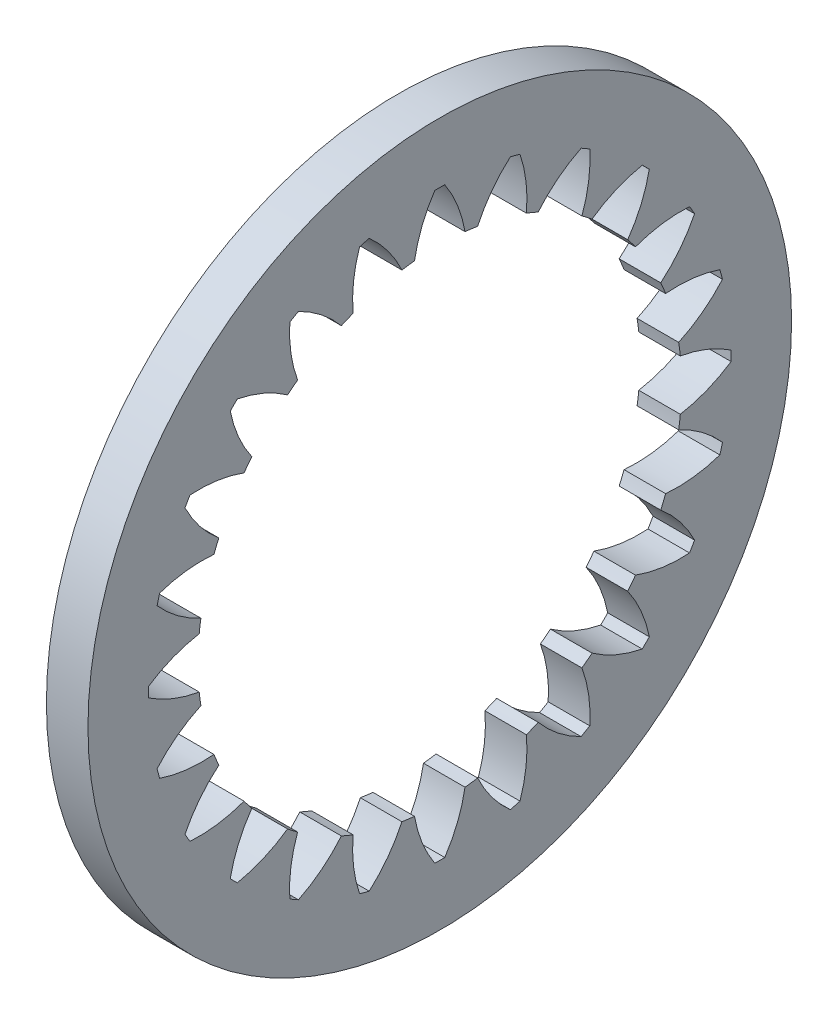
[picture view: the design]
ISO-10303-21;
HEADER;
FILE_DESCRIPTION(('STEP AP214'),'2;1');
FILE_NAME('part.step','',(''),(''),'','','');
FILE_SCHEMA(('AUTOMOTIVE_DESIGN { 1 0 10303 214 1 1 1 1 }'));
ENDSEC;
DATA;
#1=APPLICATION_CONTEXT('core data for automotive mechanical design processes');
#2=APPLICATION_PROTOCOL_DEFINITION('international standard','automotive_design',2000,#1);
#3=PRODUCT_CONTEXT('',#1,'mechanical');
#4=PRODUCT('Part','Part','',(#3));
#5=PRODUCT_RELATED_PRODUCT_CATEGORY('part','',(#4));
#6=PRODUCT_DEFINITION_FORMATION('','',#4);
#7=PRODUCT_DEFINITION_CONTEXT('part definition',#1,'design');
#8=PRODUCT_DEFINITION('design','',#6,#7);
#9=PRODUCT_DEFINITION_SHAPE('','',#8);
#10=(LENGTH_UNIT() NAMED_UNIT(*) SI_UNIT(.MILLI.,.METRE.));
#11=(NAMED_UNIT(*) PLANE_ANGLE_UNIT() SI_UNIT($,.RADIAN.));
#12=(NAMED_UNIT(*) SI_UNIT($,.STERADIAN.) SOLID_ANGLE_UNIT());
#13=UNCERTAINTY_MEASURE_WITH_UNIT(LENGTH_MEASURE(1.E-05),#10,'distance_accuracy_value','');
#14=(GEOMETRIC_REPRESENTATION_CONTEXT(3) GLOBAL_UNCERTAINTY_ASSIGNED_CONTEXT((#13)) GLOBAL_UNIT_ASSIGNED_CONTEXT((#10,
#11,#12)) REPRESENTATION_CONTEXT('',''));
#15=CARTESIAN_POINT('',(0.,0.,0.));
#16=DIRECTION('',(0.,0.,1.));
#17=DIRECTION('',(1.,0.,0.));
#18=AXIS2_PLACEMENT_3D('',#15,#16,#17);
#19=CARTESIAN_POINT('',(-10.,0.,0.));
#20=DIRECTION('',(-1.,0.,0.));
#21=DIRECTION('',(0.,0.,1.));
#22=AXIS2_PLACEMENT_3D('',#19,#20,#21);
#23=CYLINDRICAL_SURFACE('',#22,69.85);
#24=DIRECTION('',(-1.,0.,0.));
#25=VECTOR('',#24,1.);
#26=CARTESIAN_POINT('',(6.,68.9883009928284,-10.9378620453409));
#27=LINE('',#26,#25);
#28=CARTESIAN_POINT('',(12.,68.9883009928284,-10.9378620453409));
#29=VERTEX_POINT('',#28);
#30=CARTESIAN_POINT('',(0.,68.9883009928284,-10.9378620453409));
#31=VERTEX_POINT('',#30);
#32=EDGE_CURVE('E656',#29,#31,#27,.T.);
#33=ORIENTED_EDGE('',*,*,#32,.F.);
#34=CARTESIAN_POINT('',(12.,0.,0.));
#35=DIRECTION('',(-1.,0.,0.));
#36=DIRECTION('',(0.,0.,1.));
#37=AXIS2_PLACEMENT_3D('',#34,#35,#36);
#38=CIRCLE('',#37,69.85);
#39=CARTESIAN_POINT('',(12.,69.4685086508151,-7.29032275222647));
#40=VERTEX_POINT('',#39);
#41=EDGE_CURVE('E647',#40,#29,#38,.T.);
#42=ORIENTED_EDGE('',*,*,#41,.F.);
#43=DIRECTION('',(-1.,0.,0.));
#44=VECTOR('',#43,1.);
#45=CARTESIAN_POINT('',(6.,69.4685086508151,-7.29032275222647));
#46=LINE('',#45,#44);
#47=CARTESIAN_POINT('',(0.,69.4685086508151,-7.29032275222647));
#48=VERTEX_POINT('',#47);
#49=EDGE_CURVE('E1201',#48,#40,#46,.F.);
#50=ORIENTED_EDGE('',*,*,#49,.F.);
#51=CARTESIAN_POINT('',(0.,0.,0.));
#52=DIRECTION('',(-1.,0.,0.));
#53=DIRECTION('',(0.,0.,1.));
#54=AXIS2_PLACEMENT_3D('',#51,#52,#53);
#55=CIRCLE('',#54,69.85);
#56=EDGE_CURVE('E1207',#48,#31,#55,.T.);
#57=ORIENTED_EDGE('',*,*,#56,.T.);
#58=EDGE_LOOP('',(#33,#42,#50,#57));
#59=FACE_BOUND('',#58,.T.);
#60=ADVANCED_FACE('F33',(#59),#23,.F.);
#61=DIRECTION('',(-1.,0.,0.));
#62=VECTOR('',#61,1.);
#63=CARTESIAN_POINT('',(6.,65.2145522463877,-25.0216841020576));
#64=LINE('',#63,#62);
#65=CARTESIAN_POINT('',(0.,65.2145522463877,-25.0216841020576));
#66=VERTEX_POINT('',#65);
#67=CARTESIAN_POINT('',(12.,65.2145522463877,-25.0216841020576));
#68=VERTEX_POINT('',#67);
#69=EDGE_CURVE('E641',#66,#68,#64,.F.);
#70=ORIENTED_EDGE('',*,*,#69,.F.);
#71=CARTESIAN_POINT('',(0.,63.8066546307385,-28.4206496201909));
#72=VERTEX_POINT('',#71);
#73=EDGE_CURVE('E1211',#66,#72,#55,.T.);
#74=ORIENTED_EDGE('',*,*,#73,.T.);
#75=DIRECTION('',(-1.,0.,0.));
#76=VECTOR('',#75,1.);
#77=CARTESIAN_POINT('',(6.,63.8066546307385,-28.4206496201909));
#78=LINE('',#77,#76);
#79=CARTESIAN_POINT('',(12.,63.8066546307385,-28.4206496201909));
#80=VERTEX_POINT('',#79);
#81=EDGE_CURVE('E675',#80,#72,#78,.T.);
#82=ORIENTED_EDGE('',*,*,#81,.F.);
#83=EDGE_CURVE('E1220',#68,#80,#38,.T.);
#84=ORIENTED_EDGE('',*,*,#83,.F.);
#85=EDGE_LOOP('',(#70,#74,#82,#84));
#86=FACE_BOUND('',#85,.T.);
#87=ADVANCED_FACE('F1405',(#86),#23,.F.);
#88=CARTESIAN_POINT('',(12.,0.,-69.85));
#89=DIRECTION('',(-1.,0.,0.));
#90=DIRECTION('',(0.,0.,1.));
#91=AXIS2_PLACEMENT_3D('',#88,#89,#90);
#92=PLANE('',#91);
#93=CARTESIAN_POINT('',(12.,0.,0.));
#94=DIRECTION('',(-1.,0.,0.));
#95=DIRECTION('',(0.,0.,1.));
#96=AXIS2_PLACEMENT_3D('',#93,#94,#95);
#97=CIRCLE('',#96,101.6);
#98=CARTESIAN_POINT('',(12.,0.,101.6));
#99=VERTEX_POINT('',#98);
#100=EDGE_CURVE('E1214',#99,#99,#97,.T.);
#101=ORIENTED_EDGE('',*,*,#100,.F.);
#102=EDGE_LOOP('',(#101));
#103=FACE_BOUND('',#102,.T.);
#104=CARTESIAN_POINT('',(12.,53.0089651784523,-45.5250103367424));
#105=DIRECTION('',(1.,0.,0.));
#106=DIRECTION('',(0.,-0.258819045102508,-0.965925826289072));
#107=AXIS2_PLACEMENT_3D('',#104,#105,#106);
#108=CIRCLE('',#107,38.1);
#109=CARTESIAN_POINT('',(12.,81.6332099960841,-20.3801776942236));
#110=VERTEX_POINT('',#109);
#111=EDGE_CURVE('E634',#110,#29,#108,.T.);
#112=ORIENTED_EDGE('',*,*,#111,.F.);
#113=CARTESIAN_POINT('',(12.,0.,0.));
#114=DIRECTION('',(1.,0.,0.));
#115=DIRECTION('',(0.,-0.258819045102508,-0.965925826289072));
#116=AXIS2_PLACEMENT_3D('',#113,#114,#115);
#117=CIRCLE('',#116,84.13877);
#118=CARTESIAN_POINT('',(12.,80.886522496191,-23.1668533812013));
#119=VERTEX_POINT('',#118);
#120=EDGE_CURVE('E626',#119,#110,#117,.T.);
#121=ORIENTED_EDGE('',*,*,#120,.F.);
#122=CARTESIAN_POINT('',(12.,68.6696156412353,12.9213328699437));
#123=DIRECTION('',(1.,0.,0.));
#124=DIRECTION('',(0.,-0.258819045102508,-0.965925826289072));
#125=AXIS2_PLACEMENT_3D('',#122,#123,#124);
#126=CIRCLE('',#125,38.1);
#127=EDGE_CURVE('E648',#68,#119,#126,.T.);
#128=ORIENTED_EDGE('',*,*,#127,.F.);
#129=ORIENTED_EDGE('',*,*,#83,.T.);
#130=CARTESIAN_POINT('',(12.,39.4199887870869,-57.6935129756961));
#131=DIRECTION('',(1.,0.,0.));
#132=DIRECTION('',(0.,-0.499999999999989,-0.866025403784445));
#133=AXIS2_PLACEMENT_3D('',#130,#131,#132);
#134=CIRCLE('',#133,38.1);
#135=CARTESIAN_POINT('',(12.,73.5768476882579,-40.813969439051));
#136=VERTEX_POINT('',#135);
#137=EDGE_CURVE('E660',#136,#80,#134,.T.);
#138=ORIENTED_EDGE('',*,*,#137,.F.);
#139=CARTESIAN_POINT('',(12.,0.,0.));
#140=DIRECTION('',(1.,0.,0.));
#141=DIRECTION('',(0.,-0.499999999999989,-0.866025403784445));
#142=AXIS2_PLACEMENT_3D('',#139,#140,#141);
#143=CIRCLE('',#142,84.13877);
#144=CARTESIAN_POINT('',(12.,72.13435820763,-43.3124345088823));
#145=VERTEX_POINT('',#144);
#146=EDGE_CURVE('E658',#145,#136,#143,.T.);
#147=ORIENTED_EDGE('',*,*,#146,.F.);
#148=CARTESIAN_POINT('',(12.,69.6740422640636,-5.29195521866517));
#149=DIRECTION('',(1.,0.,0.));
#150=DIRECTION('',(0.,-0.499999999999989,-0.866025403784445));
#151=AXIS2_PLACEMENT_3D('',#148,#149,#150);
#152=CIRCLE('',#151,38.1);
#153=CARTESIAN_POINT('',(12.,56.5163318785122,-41.0478590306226));
#154=VERTEX_POINT('',#153);
#155=EDGE_CURVE('E664',#154,#145,#152,.T.);
#156=ORIENTED_EDGE('',*,*,#155,.F.);
#157=CARTESIAN_POINT('',(12.,54.2766902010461,-43.9666168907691));
#158=VERTEX_POINT('',#157);
#159=EDGE_CURVE('E1275',#154,#158,#38,.T.);
#160=ORIENTED_EDGE('',*,*,#159,.T.);
#161=CARTESIAN_POINT('',(12.,23.1446053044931,-65.9302980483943));
#162=DIRECTION('',(1.,0.,0.));
#163=DIRECTION('',(0.,-0.707106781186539,-0.707106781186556));
#164=AXIS2_PLACEMENT_3D('',#161,#162,#163);
#165=CIRCLE('',#164,38.1);
#166=CARTESIAN_POINT('',(12.,60.5063448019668,-58.4663566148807));
#167=VERTEX_POINT('',#166);
#168=EDGE_CURVE('E681',#167,#158,#165,.T.);
#169=ORIENTED_EDGE('',*,*,#168,.F.);
#170=CARTESIAN_POINT('',(12.,0.,0.));
#171=DIRECTION('',(1.,0.,0.));
#172=DIRECTION('',(0.,-0.707106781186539,-0.707106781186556));
#173=AXIS2_PLACEMENT_3D('',#170,#171,#172);
#174=CIRCLE('',#173,84.13877);
#175=CARTESIAN_POINT('',(12.,58.4663566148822,-60.5063448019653));
#176=VERTEX_POINT('',#175);
#177=EDGE_CURVE('E679',#176,#167,#174,.T.);
#178=ORIENTED_EDGE('',*,*,#177,.F.);
#179=CARTESIAN_POINT('',(12.,65.9302980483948,-23.1446053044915));
#180=DIRECTION('',(1.,0.,0.));
#181=DIRECTION('',(0.,-0.707106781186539,-0.707106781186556));
#182=AXIS2_PLACEMENT_3D('',#179,#180,#181);
#183=CIRCLE('',#182,38.1);
#184=CARTESIAN_POINT('',(12.,43.9666168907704,-54.2766902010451));
#185=VERTEX_POINT('',#184);
#186=EDGE_CURVE('E685',#185,#176,#183,.T.);
#187=ORIENTED_EDGE('',*,*,#186,.F.);
#188=CARTESIAN_POINT('',(12.,41.047859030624,-56.5163318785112));
#189=VERTEX_POINT('',#188);
#190=EDGE_CURVE('E1408',#185,#189,#38,.T.);
#191=ORIENTED_EDGE('',*,*,#190,.T.);
#192=CARTESIAN_POINT('',(12.,5.29195521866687,-69.6740422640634));
#193=DIRECTION('',(1.,0.,0.));
#194=DIRECTION('',(0.,-0.866025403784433,-0.50000000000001));
#195=AXIS2_PLACEMENT_3D('',#192,#193,#194);
#196=CIRCLE('',#195,38.1);
#197=CARTESIAN_POINT('',(12.,43.3124345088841,-72.1343582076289));
#198=VERTEX_POINT('',#197);
#199=EDGE_CURVE('E705',#198,#189,#196,.T.);
#200=ORIENTED_EDGE('',*,*,#199,.F.);
#201=CARTESIAN_POINT('',(12.,0.,0.));
#202=DIRECTION('',(1.,0.,0.));
#203=DIRECTION('',(0.,-0.866025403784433,-0.50000000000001));
#204=AXIS2_PLACEMENT_3D('',#201,#202,#203);
#205=CIRCLE('',#204,84.13877);
#206=CARTESIAN_POINT('',(12.,40.8139694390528,-73.5768476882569));
#207=VERTEX_POINT('',#206);
#208=EDGE_CURVE('E703',#207,#198,#205,.T.);
#209=ORIENTED_EDGE('',*,*,#208,.F.);
#210=CARTESIAN_POINT('',(12.,57.6935129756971,-39.4199887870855));
#211=DIRECTION('',(1.,0.,0.));
#212=DIRECTION('',(0.,-0.866025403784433,-0.50000000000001));
#213=AXIS2_PLACEMENT_3D('',#210,#211,#212);
#214=CIRCLE('',#213,38.1);
#215=CARTESIAN_POINT('',(12.,28.4206496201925,-63.8066546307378));
#216=VERTEX_POINT('',#215);
#217=EDGE_CURVE('E709',#216,#207,#214,.T.);
#218=ORIENTED_EDGE('',*,*,#217,.F.);
#219=CARTESIAN_POINT('',(12.,25.0216841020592,-65.2145522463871));
#220=VERTEX_POINT('',#219);
#221=EDGE_CURVE('E1410',#216,#220,#38,.T.);
#222=ORIENTED_EDGE('',*,*,#221,.T.);
#223=CARTESIAN_POINT('',(12.,-12.9213328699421,-68.6696156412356));
#224=DIRECTION('',(1.,0.,0.));
#225=DIRECTION('',(0.,-0.965925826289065,-0.258819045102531));
#226=AXIS2_PLACEMENT_3D('',#223,#224,#225);
#227=CIRCLE('',#226,38.1);
#228=CARTESIAN_POINT('',(12.,23.1668533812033,-80.8865224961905));
#229=VERTEX_POINT('',#228);
#230=EDGE_CURVE('E729',#229,#220,#227,.T.);
#231=ORIENTED_EDGE('',*,*,#230,.F.);
#232=CARTESIAN_POINT('',(12.,0.,0.));
#233=DIRECTION('',(1.,0.,0.));
#234=DIRECTION('',(0.,-0.965925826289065,-0.258819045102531));
#235=AXIS2_PLACEMENT_3D('',#232,#233,#234);
#236=CIRCLE('',#235,84.13877);
#237=CARTESIAN_POINT('',(12.,20.3801776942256,-81.6332099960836));
#238=VERTEX_POINT('',#237);
#239=EDGE_CURVE('E727',#238,#229,#236,.T.);
#240=ORIENTED_EDGE('',*,*,#239,.F.);
#241=CARTESIAN_POINT('',(12.,45.5250103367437,-53.0089651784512));
#242=DIRECTION('',(1.,0.,0.));
#243=DIRECTION('',(0.,-0.965925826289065,-0.258819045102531));
#244=AXIS2_PLACEMENT_3D('',#241,#242,#243);
#245=CIRCLE('',#244,38.1);
#246=CARTESIAN_POINT('',(12.,10.9378620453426,-68.9883009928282));
#247=VERTEX_POINT('',#246);
#248=EDGE_CURVE('E733',#247,#238,#245,.T.);
#249=ORIENTED_EDGE('',*,*,#248,.F.);
#250=CARTESIAN_POINT('',(12.,7.2903227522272,-69.468508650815));
#251=VERTEX_POINT('',#250);
#252=EDGE_CURVE('E1414',#247,#251,#38,.T.);
#253=ORIENTED_EDGE('',*,*,#252,.T.);
#254=CARTESIAN_POINT('',(12.,-30.2540534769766,-62.985468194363));
#255=DIRECTION('',(1.,0.,0.));
#256=DIRECTION('',(0.,-1.,0.));
#257=AXIS2_PLACEMENT_3D('',#254,#255,#256);
#258=CIRCLE('',#257,38.1);
#259=CARTESIAN_POINT('',(12.,1.44248948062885,-84.1264039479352));
#260=VERTEX_POINT('',#259);
#261=EDGE_CURVE('E753',#260,#251,#258,.T.);
#262=ORIENTED_EDGE('',*,*,#261,.F.);
#263=CARTESIAN_POINT('',(12.,0.,0.));
#264=DIRECTION('',(1.,0.,0.));
#265=DIRECTION('',(0.,-1.,0.));
#266=AXIS2_PLACEMENT_3D('',#263,#264,#265);
#267=CIRCLE('',#266,84.13877);
#268=CARTESIAN_POINT('',(12.,-1.44248948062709,-84.1264039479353));
#269=VERTEX_POINT('',#268);
#270=EDGE_CURVE('E751',#269,#260,#267,.T.);
#271=ORIENTED_EDGE('',*,*,#270,.F.);
#272=CARTESIAN_POINT('',(12.,30.254053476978,-62.9854681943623));
#273=DIRECTION('',(1.,0.,0.));
#274=DIRECTION('',(0.,-1.,0.));
#275=AXIS2_PLACEMENT_3D('',#272,#273,#274);
#276=CIRCLE('',#275,38.1);
#277=CARTESIAN_POINT('',(12.,-7.29032275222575,-69.4685086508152));
#278=VERTEX_POINT('',#277);
#279=EDGE_CURVE('E757',#278,#269,#276,.T.);
#280=ORIENTED_EDGE('',*,*,#279,.F.);
#281=CARTESIAN_POINT('',(12.,-10.9378620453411,-68.9883009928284));
#282=VERTEX_POINT('',#281);
#283=EDGE_CURVE('E1418',#278,#282,#38,.T.);
#284=ORIENTED_EDGE('',*,*,#283,.T.);
#285=CARTESIAN_POINT('',(12.,-45.5250103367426,-53.0089651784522));
#286=DIRECTION('',(1.,0.,0.));
#287=DIRECTION('',(0.,-0.965925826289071,0.258819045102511));
#288=AXIS2_PLACEMENT_3D('',#285,#286,#287);
#289=CIRCLE('',#288,38.1);
#290=CARTESIAN_POINT('',(12.,-20.3801776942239,-81.6332099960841));
#291=VERTEX_POINT('',#290);
#292=EDGE_CURVE('E777',#291,#282,#289,.T.);
#293=ORIENTED_EDGE('',*,*,#292,.F.);
#294=CARTESIAN_POINT('',(12.,0.,0.));
#295=DIRECTION('',(1.,0.,0.));
#296=DIRECTION('',(0.,-0.965925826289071,0.258819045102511));
#297=AXIS2_PLACEMENT_3D('',#294,#295,#296);
#298=CIRCLE('',#297,84.13877);
#299=CARTESIAN_POINT('',(12.,-23.1668533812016,-80.886522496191));
#300=VERTEX_POINT('',#299);
#301=EDGE_CURVE('E775',#300,#291,#298,.T.);
#302=ORIENTED_EDGE('',*,*,#301,.F.);
#303=CARTESIAN_POINT('',(12.,12.9213328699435,-68.6696156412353));
#304=DIRECTION('',(1.,0.,0.));
#305=DIRECTION('',(0.,-0.965925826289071,0.258819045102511));
#306=AXIS2_PLACEMENT_3D('',#303,#304,#305);
#307=CIRCLE('',#306,38.1);
#308=CARTESIAN_POINT('',(12.,-25.0216841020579,-65.2145522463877));
#309=VERTEX_POINT('',#308);
#310=EDGE_CURVE('E781',#309,#300,#307,.T.);
#311=ORIENTED_EDGE('',*,*,#310,.F.);
#312=CARTESIAN_POINT('',(12.,-28.4206496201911,-63.8066546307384));
#313=VERTEX_POINT('',#312);
#314=EDGE_CURVE('E1422',#309,#313,#38,.T.);
#315=ORIENTED_EDGE('',*,*,#314,.T.);
#316=CARTESIAN_POINT('',(12.,-57.6935129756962,-39.4199887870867));
#317=DIRECTION('',(1.,0.,0.));
#318=DIRECTION('',(0.,-0.866025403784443,0.499999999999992));
#319=AXIS2_PLACEMENT_3D('',#316,#317,#318);
#320=CIRCLE('',#319,38.1);
#321=CARTESIAN_POINT('',(12.,-40.8139694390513,-73.5768476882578));
#322=VERTEX_POINT('',#321);
#323=EDGE_CURVE('E801',#322,#313,#320,.T.);
#324=ORIENTED_EDGE('',*,*,#323,.F.);
#325=CARTESIAN_POINT('',(12.,0.,0.));
#326=DIRECTION('',(1.,0.,0.));
#327=DIRECTION('',(0.,-0.866025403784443,0.499999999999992));
#328=AXIS2_PLACEMENT_3D('',#325,#326,#327);
#329=CIRCLE('',#328,84.13877);
#330=CARTESIAN_POINT('',(12.,-43.3124345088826,-72.1343582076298));
#331=VERTEX_POINT('',#330);
#332=EDGE_CURVE('E799',#331,#322,#329,.T.);
#333=ORIENTED_EDGE('',*,*,#332,.F.);
#334=CARTESIAN_POINT('',(12.,-5.29195521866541,-69.6740422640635));
#335=DIRECTION('',(1.,0.,0.));
#336=DIRECTION('',(0.,-0.866025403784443,0.499999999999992));
#337=AXIS2_PLACEMENT_3D('',#334,#335,#336);
#338=CIRCLE('',#337,38.1);
#339=CARTESIAN_POINT('',(12.,-41.0478590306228,-56.516331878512));
#340=VERTEX_POINT('',#339);
#341=EDGE_CURVE('E805',#340,#331,#338,.T.);
#342=ORIENTED_EDGE('',*,*,#341,.F.);
#343=CARTESIAN_POINT('',(12.,-43.9666168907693,-54.276690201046));
#344=VERTEX_POINT('',#343);
#345=EDGE_CURVE('E1426',#340,#344,#38,.T.);
#346=ORIENTED_EDGE('',*,*,#345,.T.);
#347=CARTESIAN_POINT('',(12.,-65.9302980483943,-23.1446053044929));
#348=DIRECTION('',(1.,0.,0.));
#349=DIRECTION('',(0.,-0.707106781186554,0.707106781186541));
#350=AXIS2_PLACEMENT_3D('',#347,#348,#349);
#351=CIRCLE('',#350,38.1);
#352=CARTESIAN_POINT('',(12.,-58.4663566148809,-60.5063448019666));
#353=VERTEX_POINT('',#352);
#354=EDGE_CURVE('E825',#353,#344,#351,.T.);
#355=ORIENTED_EDGE('',*,*,#354,.F.);
#356=CARTESIAN_POINT('',(12.,0.,0.));
#357=DIRECTION('',(1.,0.,0.));
#358=DIRECTION('',(0.,-0.707106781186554,0.707106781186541));
#359=AXIS2_PLACEMENT_3D('',#356,#357,#358);
#360=CIRCLE('',#359,84.13877);
#361=CARTESIAN_POINT('',(12.,-60.5063448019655,-58.466356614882));
#362=VERTEX_POINT('',#361);
#363=EDGE_CURVE('E823',#362,#353,#360,.T.);
#364=ORIENTED_EDGE('',*,*,#363,.F.);
#365=CARTESIAN_POINT('',(12.,-23.1446053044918,-65.9302980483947));
#366=DIRECTION('',(1.,0.,0.));
#367=DIRECTION('',(0.,-0.707106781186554,0.707106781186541));
#368=AXIS2_PLACEMENT_3D('',#365,#366,#367);
#369=CIRCLE('',#368,38.1);
#370=CARTESIAN_POINT('',(12.,-54.2766902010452,-43.9666168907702));
#371=VERTEX_POINT('',#370);
#372=EDGE_CURVE('E829',#371,#362,#369,.T.);
#373=ORIENTED_EDGE('',*,*,#372,.F.);
#374=CARTESIAN_POINT('',(12.,-56.5163318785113,-41.0478590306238));
#375=VERTEX_POINT('',#374);
#376=EDGE_CURVE('E1430',#371,#375,#38,.T.);
#377=ORIENTED_EDGE('',*,*,#376,.T.);
#378=CARTESIAN_POINT('',(12.,-69.6740422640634,-5.29195521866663));
#379=DIRECTION('',(1.,0.,0.));
#380=DIRECTION('',(0.,-0.500000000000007,0.866025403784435));
#381=AXIS2_PLACEMENT_3D('',#378,#379,#380);
#382=CIRCLE('',#381,38.1);
#383=CARTESIAN_POINT('',(12.,-72.1343582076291,-43.3124345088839));
#384=VERTEX_POINT('',#383);
#385=EDGE_CURVE('E849',#384,#375,#382,.T.);
#386=ORIENTED_EDGE('',*,*,#385,.F.);
#387=CARTESIAN_POINT('',(12.,0.,0.));
#388=DIRECTION('',(1.,0.,0.));
#389=DIRECTION('',(0.,-0.500000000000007,0.866025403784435));
#390=AXIS2_PLACEMENT_3D('',#387,#388,#389);
#391=CIRCLE('',#390,84.13877);
#392=CARTESIAN_POINT('',(12.,-73.5768476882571,-40.8139694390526));
#393=VERTEX_POINT('',#392);
#394=EDGE_CURVE('E847',#393,#384,#391,.T.);
#395=ORIENTED_EDGE('',*,*,#394,.F.);
#396=CARTESIAN_POINT('',(12.,-39.4199887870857,-57.6935129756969));
#397=DIRECTION('',(1.,0.,0.));
#398=DIRECTION('',(0.,-0.500000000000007,0.866025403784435));
#399=AXIS2_PLACEMENT_3D('',#396,#397,#398);
#400=CIRCLE('',#399,38.1);
#401=CARTESIAN_POINT('',(12.,-63.8066546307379,-28.4206496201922));
#402=VERTEX_POINT('',#401);
#403=EDGE_CURVE('E853',#402,#393,#400,.T.);
#404=ORIENTED_EDGE('',*,*,#403,.F.);
#405=CARTESIAN_POINT('',(12.,-65.2145522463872,-25.021684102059));
#406=VERTEX_POINT('',#405);
#407=EDGE_CURVE('E1434',#402,#406,#38,.T.);
#408=ORIENTED_EDGE('',*,*,#407,.T.);
#409=CARTESIAN_POINT('',(12.,-68.6696156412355,12.9213328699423));
#410=DIRECTION('',(1.,0.,0.));
#411=DIRECTION('',(0.,-0.258819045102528,0.965925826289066));
#412=AXIS2_PLACEMENT_3D('',#409,#410,#411);
#413=CIRCLE('',#412,38.1);
#414=CARTESIAN_POINT('',(12.,-80.8865224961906,-23.166853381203));
#415=VERTEX_POINT('',#414);
#416=EDGE_CURVE('E873',#415,#406,#413,.T.);
#417=ORIENTED_EDGE('',*,*,#416,.F.);
#418=CARTESIAN_POINT('',(12.,0.,0.));
#419=DIRECTION('',(1.,0.,0.));
#420=DIRECTION('',(0.,-0.258819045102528,0.965925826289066));
#421=AXIS2_PLACEMENT_3D('',#418,#419,#420);
#422=CIRCLE('',#421,84.13877);
#423=CARTESIAN_POINT('',(12.,-81.6332099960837,-20.3801776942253));
#424=VERTEX_POINT('',#423);
#425=EDGE_CURVE('E871',#424,#415,#422,.T.);
#426=ORIENTED_EDGE('',*,*,#425,.F.);
#427=CARTESIAN_POINT('',(12.,-53.0089651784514,-45.5250103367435));
#428=DIRECTION('',(1.,0.,0.));
#429=DIRECTION('',(0.,-0.258819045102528,0.965925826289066));
#430=AXIS2_PLACEMENT_3D('',#427,#428,#429);
#431=CIRCLE('',#430,38.1);
#432=CARTESIAN_POINT('',(12.,-68.9883009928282,-10.9378620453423));
#433=VERTEX_POINT('',#432);
#434=EDGE_CURVE('E877',#433,#424,#431,.T.);
#435=ORIENTED_EDGE('',*,*,#434,.F.);
#436=CARTESIAN_POINT('',(12.,-69.468508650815,-7.29032275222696));
#437=VERTEX_POINT('',#436);
#438=EDGE_CURVE('E1438',#433,#437,#38,.T.);
#439=ORIENTED_EDGE('',*,*,#438,.T.);
#440=CARTESIAN_POINT('',(12.,-62.9854681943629,30.2540534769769));
#441=DIRECTION('',(1.,0.,0.));
#442=DIRECTION('',(0.,0.,1.));
#443=AXIS2_PLACEMENT_3D('',#440,#441,#442);
#444=CIRCLE('',#443,38.1);
#445=CARTESIAN_POINT('',(12.,-84.1264039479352,-1.44248948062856));
#446=VERTEX_POINT('',#445);
#447=EDGE_CURVE('E897',#446,#437,#444,.T.);
#448=ORIENTED_EDGE('',*,*,#447,.F.);
#449=CARTESIAN_POINT('',(12.,0.,0.));
#450=DIRECTION('',(1.,0.,0.));
#451=DIRECTION('',(0.,0.,1.));
#452=AXIS2_PLACEMENT_3D('',#449,#450,#451);
#453=CIRCLE('',#452,84.13877);
#454=CARTESIAN_POINT('',(12.,-84.1264039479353,1.44248948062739));
#455=VERTEX_POINT('',#454);
#456=EDGE_CURVE('E895',#455,#446,#453,.T.);
#457=ORIENTED_EDGE('',*,*,#456,.F.);
#458=CARTESIAN_POINT('',(12.,-62.9854681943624,-30.2540534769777));
#459=DIRECTION('',(1.,0.,0.));
#460=DIRECTION('',(0.,0.,1.));
#461=AXIS2_PLACEMENT_3D('',#458,#459,#460);
#462=CIRCLE('',#461,38.1);
#463=CARTESIAN_POINT('',(12.,-69.4685086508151,7.29032275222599));
#464=VERTEX_POINT('',#463);
#465=EDGE_CURVE('E901',#464,#455,#462,.T.);
#466=ORIENTED_EDGE('',*,*,#465,.F.);
#467=CARTESIAN_POINT('',(12.,-68.9883009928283,10.9378620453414));
#468=VERTEX_POINT('',#467);
#469=EDGE_CURVE('E1442',#464,#468,#38,.T.);
#470=ORIENTED_EDGE('',*,*,#469,.T.);
#471=CARTESIAN_POINT('',(12.,-53.008965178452,45.5250103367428));
#472=DIRECTION('',(1.,0.,0.));
#473=DIRECTION('',(0.,0.258819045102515,0.96592582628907));
#474=AXIS2_PLACEMENT_3D('',#471,#472,#473);
#475=CIRCLE('',#474,38.1);
#476=CARTESIAN_POINT('',(12.,-81.633209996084,20.3801776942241));
#477=VERTEX_POINT('',#476);
#478=EDGE_CURVE('E921',#477,#468,#475,.T.);
#479=ORIENTED_EDGE('',*,*,#478,.F.);
#480=CARTESIAN_POINT('',(12.,0.,0.));
#481=DIRECTION('',(1.,0.,0.));
#482=DIRECTION('',(0.,0.258819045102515,0.96592582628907));
#483=AXIS2_PLACEMENT_3D('',#480,#481,#482);
#484=CIRCLE('',#483,84.13877);
#485=CARTESIAN_POINT('',(12.,-80.8865224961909,23.1668533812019));
#486=VERTEX_POINT('',#485);
#487=EDGE_CURVE('E919',#486,#477,#484,.T.);
#488=ORIENTED_EDGE('',*,*,#487,.F.);
#489=CARTESIAN_POINT('',(12.,-68.6696156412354,-12.9213328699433));
#490=DIRECTION('',(1.,0.,0.));
#491=DIRECTION('',(0.,0.258819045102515,0.96592582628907));
#492=AXIS2_PLACEMENT_3D('',#489,#490,#491);
#493=CIRCLE('',#492,38.1);
#494=CARTESIAN_POINT('',(12.,-65.2145522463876,25.0216841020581));
#495=VERTEX_POINT('',#494);
#496=EDGE_CURVE('E925',#495,#486,#493,.T.);
#497=ORIENTED_EDGE('',*,*,#496,.F.);
#498=CARTESIAN_POINT('',(12.,-63.8066546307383,28.4206496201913));
#499=VERTEX_POINT('',#498);
#500=EDGE_CURVE('E1446',#495,#499,#38,.T.);
#501=ORIENTED_EDGE('',*,*,#500,.T.);
#502=CARTESIAN_POINT('',(12.,-39.4199887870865,57.6935129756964));
#503=DIRECTION('',(1.,0.,0.));
#504=DIRECTION('',(0.,0.499999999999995,0.866025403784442));
#505=AXIS2_PLACEMENT_3D('',#502,#503,#504);
#506=CIRCLE('',#505,38.1);
#507=CARTESIAN_POINT('',(12.,-73.5768476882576,40.8139694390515));
#508=VERTEX_POINT('',#507);
#509=EDGE_CURVE('E945',#508,#499,#506,.T.);
#510=ORIENTED_EDGE('',*,*,#509,.F.);
#511=CARTESIAN_POINT('',(12.,0.,0.));
#512=DIRECTION('',(1.,0.,0.));
#513=DIRECTION('',(0.,0.499999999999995,0.866025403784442));
#514=AXIS2_PLACEMENT_3D('',#511,#512,#513);
#515=CIRCLE('',#514,84.13877);
#516=CARTESIAN_POINT('',(12.,-72.1343582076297,43.3124345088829));
#517=VERTEX_POINT('',#516);
#518=EDGE_CURVE('E943',#517,#508,#515,.T.);
#519=ORIENTED_EDGE('',*,*,#518,.F.);
#520=CARTESIAN_POINT('',(12.,-69.6740422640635,5.29195521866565));
#521=DIRECTION('',(1.,0.,0.));
#522=DIRECTION('',(0.,0.499999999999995,0.866025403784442));
#523=AXIS2_PLACEMENT_3D('',#520,#521,#522);
#524=CIRCLE('',#523,38.1);
#525=CARTESIAN_POINT('',(12.,-56.5163318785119,41.047859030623));
#526=VERTEX_POINT('',#525);
#527=EDGE_CURVE('E949',#526,#517,#524,.T.);
#528=ORIENTED_EDGE('',*,*,#527,.F.);
#529=CARTESIAN_POINT('',(12.,-54.2766902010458,43.9666168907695));
#530=VERTEX_POINT('',#529);
#531=EDGE_CURVE('E1450',#526,#530,#38,.T.);
#532=ORIENTED_EDGE('',*,*,#531,.T.);
#533=CARTESIAN_POINT('',(12.,-23.1446053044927,65.9302980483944));
#534=DIRECTION('',(1.,0.,0.));
#535=DIRECTION('',(0.,0.707106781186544,0.707106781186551));
#536=AXIS2_PLACEMENT_3D('',#533,#534,#535);
#537=CIRCLE('',#536,38.1);
#538=CARTESIAN_POINT('',(12.,-60.5063448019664,58.4663566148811));
#539=VERTEX_POINT('',#538);
#540=EDGE_CURVE('E969',#539,#530,#537,.T.);
#541=ORIENTED_EDGE('',*,*,#540,.F.);
#542=CARTESIAN_POINT('',(12.,0.,0.));
#543=DIRECTION('',(1.,0.,0.));
#544=DIRECTION('',(0.,0.707106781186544,0.707106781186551));
#545=AXIS2_PLACEMENT_3D('',#542,#543,#544);
#546=CIRCLE('',#545,84.13877);
#547=CARTESIAN_POINT('',(12.,-58.4663566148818,60.5063448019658));
#548=VERTEX_POINT('',#547);
#549=EDGE_CURVE('E967',#548,#539,#546,.T.);
#550=ORIENTED_EDGE('',*,*,#549,.F.);
#551=CARTESIAN_POINT('',(12.,-65.9302980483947,23.144605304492));
#552=DIRECTION('',(1.,0.,0.));
#553=DIRECTION('',(0.,0.707106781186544,0.707106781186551));
#554=AXIS2_PLACEMENT_3D('',#551,#552,#553);
#555=CIRCLE('',#554,38.1);
#556=CARTESIAN_POINT('',(12.,-43.9666168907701,54.2766902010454));
#557=VERTEX_POINT('',#556);
#558=EDGE_CURVE('E973',#557,#548,#555,.T.);
#559=ORIENTED_EDGE('',*,*,#558,.F.);
#560=CARTESIAN_POINT('',(12.,-41.0478590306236,56.5163318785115));
#561=VERTEX_POINT('',#560);
#562=EDGE_CURVE('E1454',#557,#561,#38,.T.);
#563=ORIENTED_EDGE('',*,*,#562,.T.);
#564=CARTESIAN_POINT('',(12.,-5.29195521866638,69.6740422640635));
#565=DIRECTION('',(1.,0.,0.));
#566=DIRECTION('',(0.,0.866025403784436,0.500000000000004));
#567=AXIS2_PLACEMENT_3D('',#564,#565,#566);
#568=CIRCLE('',#567,38.1);
#569=CARTESIAN_POINT('',(12.,-43.3124345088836,72.1343582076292));
#570=VERTEX_POINT('',#569);
#571=EDGE_CURVE('E993',#570,#561,#568,.T.);
#572=ORIENTED_EDGE('',*,*,#571,.F.);
#573=CARTESIAN_POINT('',(12.,0.,0.));
#574=DIRECTION('',(1.,0.,0.));
#575=DIRECTION('',(0.,0.866025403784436,0.500000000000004));
#576=AXIS2_PLACEMENT_3D('',#573,#574,#575);
#577=CIRCLE('',#576,84.13877);
#578=CARTESIAN_POINT('',(12.,-40.8139694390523,73.5768476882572));
#579=VERTEX_POINT('',#578);
#580=EDGE_CURVE('E991',#579,#570,#577,.T.);
#581=ORIENTED_EDGE('',*,*,#580,.F.);
#582=CARTESIAN_POINT('',(12.,-57.6935129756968,39.4199887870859));
#583=DIRECTION('',(1.,0.,0.));
#584=DIRECTION('',(0.,0.866025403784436,0.500000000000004));
#585=AXIS2_PLACEMENT_3D('',#582,#583,#584);
#586=CIRCLE('',#585,38.1);
#587=CARTESIAN_POINT('',(12.,-28.420649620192,63.806654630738));
#588=VERTEX_POINT('',#587);
#589=EDGE_CURVE('E997',#588,#579,#586,.T.);
#590=ORIENTED_EDGE('',*,*,#589,.F.);
#591=CARTESIAN_POINT('',(12.,-25.0216841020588,65.2145522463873));
#592=VERTEX_POINT('',#591);
#593=EDGE_CURVE('E1458',#588,#592,#38,.T.);
#594=ORIENTED_EDGE('',*,*,#593,.T.);
#595=CARTESIAN_POINT('',(12.,12.9213328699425,68.6696156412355));
#596=DIRECTION('',(1.,0.,0.));
#597=DIRECTION('',(0.,0.965925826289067,0.258819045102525));
#598=AXIS2_PLACEMENT_3D('',#595,#596,#597);
#599=CIRCLE('',#598,38.1);
#600=CARTESIAN_POINT('',(12.,-23.1668533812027,80.8865224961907));
#601=VERTEX_POINT('',#600);
#602=EDGE_CURVE('E1017',#601,#592,#599,.T.);
#603=ORIENTED_EDGE('',*,*,#602,.F.);
#604=CARTESIAN_POINT('',(12.,0.,0.));
#605=DIRECTION('',(1.,0.,0.));
#606=DIRECTION('',(0.,0.965925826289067,0.258819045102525));
#607=AXIS2_PLACEMENT_3D('',#604,#605,#606);
#608=CIRCLE('',#607,84.13877);
#609=CARTESIAN_POINT('',(12.,-20.380177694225,81.6332099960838));
#610=VERTEX_POINT('',#609);
#611=EDGE_CURVE('E1015',#610,#601,#608,.T.);
#612=ORIENTED_EDGE('',*,*,#611,.F.);
#613=CARTESIAN_POINT('',(12.,-45.5250103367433,53.0089651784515));
#614=DIRECTION('',(1.,0.,0.));
#615=DIRECTION('',(0.,0.965925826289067,0.258819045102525));
#616=AXIS2_PLACEMENT_3D('',#613,#614,#615);
#617=CIRCLE('',#616,38.1);
#618=CARTESIAN_POINT('',(12.,-10.9378620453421,68.9883009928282));
#619=VERTEX_POINT('',#618);
#620=EDGE_CURVE('E1021',#619,#610,#617,.T.);
#621=ORIENTED_EDGE('',*,*,#620,.F.);
#622=CARTESIAN_POINT('',(12.,-7.29032275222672,69.4685086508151));
#623=VERTEX_POINT('',#622);
#624=EDGE_CURVE('E1462',#619,#623,#38,.T.);
#625=ORIENTED_EDGE('',*,*,#624,.T.);
#626=CARTESIAN_POINT('',(12.,30.2540534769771,62.9854681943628));
#627=DIRECTION('',(1.,0.,0.));
#628=DIRECTION('',(0.,1.,0.));
#629=AXIS2_PLACEMENT_3D('',#626,#627,#628);
#630=CIRCLE('',#629,38.1);
#631=CARTESIAN_POINT('',(12.,-1.44248948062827,84.1264039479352));
#632=VERTEX_POINT('',#631);
#633=EDGE_CURVE('E1041',#632,#623,#630,.T.);
#634=ORIENTED_EDGE('',*,*,#633,.F.);
#635=CARTESIAN_POINT('',(12.,0.,0.));
#636=DIRECTION('',(1.,0.,0.));
#637=DIRECTION('',(0.,1.,0.));
#638=AXIS2_PLACEMENT_3D('',#635,#636,#637);
#639=CIRCLE('',#638,84.13877);
#640=CARTESIAN_POINT('',(12.,1.44248948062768,84.1264039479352));
#641=VERTEX_POINT('',#640);
#642=EDGE_CURVE('E1039',#641,#632,#639,.T.);
#643=ORIENTED_EDGE('',*,*,#642,.F.);
#644=CARTESIAN_POINT('',(12.,-30.2540534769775,62.9854681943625));
#645=DIRECTION('',(1.,0.,0.));
#646=DIRECTION('',(0.,1.,0.));
#647=AXIS2_PLACEMENT_3D('',#644,#645,#646);
#648=CIRCLE('',#647,38.1);
#649=CARTESIAN_POINT('',(12.,7.29032275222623,69.4685086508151));
#650=VERTEX_POINT('',#649);
#651=EDGE_CURVE('E1045',#650,#641,#648,.T.);
#652=ORIENTED_EDGE('',*,*,#651,.F.);
#653=CARTESIAN_POINT('',(12.,10.9378620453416,68.9883009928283));
#654=VERTEX_POINT('',#653);
#655=EDGE_CURVE('E1466',#650,#654,#38,.T.);
#656=ORIENTED_EDGE('',*,*,#655,.T.);
#657=CARTESIAN_POINT('',(12.,45.5250103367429,53.0089651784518));
#658=DIRECTION('',(1.,0.,0.));
#659=DIRECTION('',(0.,0.965925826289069,-0.258819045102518));
#660=AXIS2_PLACEMENT_3D('',#657,#658,#659);
#661=CIRCLE('',#660,38.1);
#662=CARTESIAN_POINT('',(12.,20.3801776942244,81.6332099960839));
#663=VERTEX_POINT('',#662);
#664=EDGE_CURVE('E1065',#663,#654,#661,.T.);
#665=ORIENTED_EDGE('',*,*,#664,.F.);
#666=CARTESIAN_POINT('',(12.,0.,0.));
#667=DIRECTION('',(1.,0.,0.));
#668=DIRECTION('',(0.,0.965925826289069,-0.258819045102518));
#669=AXIS2_PLACEMENT_3D('',#666,#667,#668);
#670=CIRCLE('',#669,84.13877);
#671=CARTESIAN_POINT('',(12.,23.1668533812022,80.8865224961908));
#672=VERTEX_POINT('',#671);
#673=EDGE_CURVE('E1063',#672,#663,#670,.T.);
#674=ORIENTED_EDGE('',*,*,#673,.F.);
#675=CARTESIAN_POINT('',(12.,-12.921332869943,68.6696156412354));
#676=DIRECTION('',(1.,0.,0.));
#677=DIRECTION('',(0.,0.965925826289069,-0.258819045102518));
#678=AXIS2_PLACEMENT_3D('',#675,#676,#677);
#679=CIRCLE('',#678,38.1);
#680=CARTESIAN_POINT('',(12.,25.0216841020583,65.2145522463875));
#681=VERTEX_POINT('',#680);
#682=EDGE_CURVE('E1069',#681,#672,#679,.T.);
#683=ORIENTED_EDGE('',*,*,#682,.F.);
#684=CARTESIAN_POINT('',(12.,28.4206496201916,63.8066546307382));
#685=VERTEX_POINT('',#684);
#686=EDGE_CURVE('E1470',#681,#685,#38,.T.);
#687=ORIENTED_EDGE('',*,*,#686,.T.);
#688=CARTESIAN_POINT('',(12.,57.6935129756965,39.4199887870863));
#689=DIRECTION('',(1.,0.,0.));
#690=DIRECTION('',(0.,0.86602540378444,-0.499999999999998));
#691=AXIS2_PLACEMENT_3D('',#688,#689,#690);
#692=CIRCLE('',#691,38.1);
#693=CARTESIAN_POINT('',(12.,40.8139694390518,73.5768476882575));
#694=VERTEX_POINT('',#693);
#695=EDGE_CURVE('E1089',#694,#685,#692,.T.);
#696=ORIENTED_EDGE('',*,*,#695,.F.);
#697=CARTESIAN_POINT('',(12.,0.,0.));
#698=DIRECTION('',(1.,0.,0.));
#699=DIRECTION('',(0.,0.86602540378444,-0.499999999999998));
#700=AXIS2_PLACEMENT_3D('',#697,#698,#699);
#701=CIRCLE('',#700,84.13877);
#702=CARTESIAN_POINT('',(12.,43.3124345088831,72.1343582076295));
#703=VERTEX_POINT('',#702);
#704=EDGE_CURVE('E1087',#703,#694,#701,.T.);
#705=ORIENTED_EDGE('',*,*,#704,.F.);
#706=CARTESIAN_POINT('',(12.,5.2919552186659,69.6740422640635));
#707=DIRECTION('',(1.,0.,0.));
#708=DIRECTION('',(0.,0.86602540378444,-0.499999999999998));
#709=AXIS2_PLACEMENT_3D('',#706,#707,#708);
#710=CIRCLE('',#709,38.1);
#711=CARTESIAN_POINT('',(12.,41.0478590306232,56.5163318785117));
#712=VERTEX_POINT('',#711);
#713=EDGE_CURVE('E1093',#712,#703,#710,.T.);
#714=ORIENTED_EDGE('',*,*,#713,.F.);
#715=CARTESIAN_POINT('',(12.,43.9666168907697,54.2766902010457));
#716=VERTEX_POINT('',#715);
#717=EDGE_CURVE('E1474',#712,#716,#38,.T.);
#718=ORIENTED_EDGE('',*,*,#717,.T.);
#719=CARTESIAN_POINT('',(12.,65.9302980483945,23.1446053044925));
#720=DIRECTION('',(1.,0.,0.));
#721=DIRECTION('',(0.,0.707106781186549,-0.707106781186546));
#722=AXIS2_PLACEMENT_3D('',#719,#720,#721);
#723=CIRCLE('',#722,38.1);
#724=CARTESIAN_POINT('',(12.,58.4663566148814,60.5063448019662));
#725=VERTEX_POINT('',#724);
#726=EDGE_CURVE('E1113',#725,#716,#723,.T.);
#727=ORIENTED_EDGE('',*,*,#726,.F.);
#728=CARTESIAN_POINT('',(12.,0.,0.));
#729=DIRECTION('',(1.,0.,0.));
#730=DIRECTION('',(0.,0.707106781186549,-0.707106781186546));
#731=AXIS2_PLACEMENT_3D('',#728,#729,#730);
#732=CIRCLE('',#731,84.13877);
#733=CARTESIAN_POINT('',(12.,60.506344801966,58.4663566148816));
#734=VERTEX_POINT('',#733);
#735=EDGE_CURVE('E1111',#734,#725,#732,.T.);
#736=ORIENTED_EDGE('',*,*,#735,.F.);
#737=CARTESIAN_POINT('',(12.,23.1446053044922,65.9302980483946));
#738=DIRECTION('',(1.,0.,0.));
#739=DIRECTION('',(0.,0.707106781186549,-0.707106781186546));
#740=AXIS2_PLACEMENT_3D('',#737,#738,#739);
#741=CIRCLE('',#740,38.1);
#742=CARTESIAN_POINT('',(12.,54.2766902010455,43.9666168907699));
#743=VERTEX_POINT('',#742);
#744=EDGE_CURVE('E1117',#743,#734,#741,.T.);
#745=ORIENTED_EDGE('',*,*,#744,.F.);
#746=CARTESIAN_POINT('',(12.,56.5163318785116,41.0478590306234));
#747=VERTEX_POINT('',#746);
#748=EDGE_CURVE('E1478',#743,#747,#38,.T.);
#749=ORIENTED_EDGE('',*,*,#748,.T.);
#750=CARTESIAN_POINT('',(12.,69.6740422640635,5.29195521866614));
#751=DIRECTION('',(1.,0.,0.));
#752=DIRECTION('',(0.,0.500000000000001,-0.866025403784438));
#753=AXIS2_PLACEMENT_3D('',#750,#751,#752);
#754=CIRCLE('',#753,38.1);
#755=CARTESIAN_POINT('',(12.,72.1343582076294,43.3124345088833));
#756=VERTEX_POINT('',#755);
#757=EDGE_CURVE('E1137',#756,#747,#754,.T.);
#758=ORIENTED_EDGE('',*,*,#757,.F.);
#759=CARTESIAN_POINT('',(12.,0.,0.));
#760=DIRECTION('',(1.,0.,0.));
#761=DIRECTION('',(0.,0.500000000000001,-0.866025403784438));
#762=AXIS2_PLACEMENT_3D('',#759,#760,#761);
#763=CIRCLE('',#762,84.13877);
#764=CARTESIAN_POINT('',(12.,73.5768476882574,40.8139694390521));
#765=VERTEX_POINT('',#764);
#766=EDGE_CURVE('E1135',#765,#756,#763,.T.);
#767=ORIENTED_EDGE('',*,*,#766,.F.);
#768=CARTESIAN_POINT('',(12.,39.4199887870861,57.6935129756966));
#769=DIRECTION('',(1.,0.,0.));
#770=DIRECTION('',(0.,0.500000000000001,-0.866025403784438));
#771=AXIS2_PLACEMENT_3D('',#768,#769,#770);
#772=CIRCLE('',#771,38.1);
#773=CARTESIAN_POINT('',(12.,63.8066546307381,28.4206496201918));
#774=VERTEX_POINT('',#773);
#775=EDGE_CURVE('E1141',#774,#765,#772,.T.);
#776=ORIENTED_EDGE('',*,*,#775,.F.);
#777=CARTESIAN_POINT('',(12.,65.2145522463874,25.0216841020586));
#778=VERTEX_POINT('',#777);
#779=EDGE_CURVE('E1482',#774,#778,#38,.T.);
#780=ORIENTED_EDGE('',*,*,#779,.T.);
#781=CARTESIAN_POINT('',(12.,68.6696156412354,-12.9213328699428));
#782=DIRECTION('',(1.,0.,0.));
#783=DIRECTION('',(0.,0.258819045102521,-0.965925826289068));
#784=AXIS2_PLACEMENT_3D('',#781,#782,#783);
#785=CIRCLE('',#784,38.1);
#786=CARTESIAN_POINT('',(12.,80.8865224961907,23.1668533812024));
#787=VERTEX_POINT('',#786);
#788=EDGE_CURVE('E1161',#787,#778,#785,.T.);
#789=ORIENTED_EDGE('',*,*,#788,.F.);
#790=CARTESIAN_POINT('',(12.,0.,0.));
#791=DIRECTION('',(1.,0.,0.));
#792=DIRECTION('',(0.,0.258819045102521,-0.965925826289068));
#793=AXIS2_PLACEMENT_3D('',#790,#791,#792);
#794=CIRCLE('',#793,84.13877);
#795=CARTESIAN_POINT('',(12.,81.6332099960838,20.3801776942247));
#796=VERTEX_POINT('',#795);
#797=EDGE_CURVE('E1159',#796,#787,#794,.T.);
#798=ORIENTED_EDGE('',*,*,#797,.F.);
#799=CARTESIAN_POINT('',(12.,53.0089651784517,45.5250103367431));
#800=DIRECTION('',(1.,0.,0.));
#801=DIRECTION('',(0.,0.258819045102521,-0.965925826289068));
#802=AXIS2_PLACEMENT_3D('',#799,#800,#801);
#803=CIRCLE('',#802,38.1);
#804=CARTESIAN_POINT('',(12.,68.9883009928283,10.9378620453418));
#805=VERTEX_POINT('',#804);
#806=EDGE_CURVE('E1165',#805,#796,#803,.T.);
#807=ORIENTED_EDGE('',*,*,#806,.F.);
#808=CARTESIAN_POINT('',(12.,69.4685086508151,7.29032275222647));
#809=VERTEX_POINT('',#808);
#810=EDGE_CURVE('E1217',#805,#809,#38,.T.);
#811=ORIENTED_EDGE('',*,*,#810,.T.);
#812=CARTESIAN_POINT('',(12.,62.9854681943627,-30.2540534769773));
#813=DIRECTION('',(1.,0.,0.));
#814=DIRECTION('',(0.,0.,-1.));
#815=AXIS2_PLACEMENT_3D('',#812,#813,#814);
#816=CIRCLE('',#815,38.1);
#817=CARTESIAN_POINT('',(12.,84.1264039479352,1.44248948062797));
#818=VERTEX_POINT('',#817);
#819=EDGE_CURVE('E1185',#818,#809,#816,.T.);
#820=ORIENTED_EDGE('',*,*,#819,.F.);
#821=CARTESIAN_POINT('',(12.,0.,0.));
#822=DIRECTION('',(1.,0.,0.));
#823=DIRECTION('',(0.,0.,-1.));
#824=AXIS2_PLACEMENT_3D('',#821,#822,#823);
#825=CIRCLE('',#824,84.13877);
#826=CARTESIAN_POINT('',(12.,84.1264039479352,-1.44248948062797));
#827=VERTEX_POINT('',#826);
#828=EDGE_CURVE('E1183',#827,#818,#825,.T.);
#829=ORIENTED_EDGE('',*,*,#828,.F.);
#830=CARTESIAN_POINT('',(12.,62.9854681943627,30.2540534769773));
#831=DIRECTION('',(1.,0.,0.));
#832=DIRECTION('',(0.,0.,-1.));
#833=AXIS2_PLACEMENT_3D('',#830,#831,#832);
#834=CIRCLE('',#833,38.1);
#835=EDGE_CURVE('E1189',#40,#827,#834,.T.);
#836=ORIENTED_EDGE('',*,*,#835,.F.);
#837=ORIENTED_EDGE('',*,*,#41,.T.);
#838=EDGE_LOOP('',(#112,#121,#128,#129,#138,#147,#156,#160,#169,#178,#187,#191,#200,#209,#218,
#222,#231,#240,#249,#253,#262,#271,#280,#284,#293,#302,#311,#315,#324,#333,#342,#346,#355,#364,
#373,#377,#386,#395,#404,#408,#417,#426,#435,#439,#448,#457,#466,#470,#479,#488,#497,#501,#510,
#519,#528,#532,#541,#550,#559,#563,#572,#581,#590,#594,#603,#612,#621,#625,#634,#643,#652,#656,
#665,#674,#683,#687,#696,#705,#714,#718,#727,#736,#745,#749,#758,#767,#776,#780,#789,#798,#807,
#811,#820,#829,#836,#837));
#839=FACE_BOUND('',#838,.T.);
#840=ADVANCED_FACE('F644',(#103,#839),#92,.F.);
#841=CARTESIAN_POINT('',(0.,0.,-69.85));
#842=DIRECTION('',(1.,0.,0.));
#843=DIRECTION('',(0.,0.,-1.));
#844=AXIS2_PLACEMENT_3D('',#841,#842,#843);
#845=PLANE('',#844);
#846=CARTESIAN_POINT('',(0.,0.,0.));
#847=DIRECTION('',(-1.,0.,0.));
#848=DIRECTION('',(0.,0.,1.));
#849=AXIS2_PLACEMENT_3D('',#846,#847,#848);
#850=CIRCLE('',#849,101.6);
#851=CARTESIAN_POINT('',(0.,0.,101.6));
#852=VERTEX_POINT('',#851);
#853=EDGE_CURVE('E1210',#852,#852,#850,.T.);
#854=ORIENTED_EDGE('',*,*,#853,.T.);
#855=EDGE_LOOP('',(#854));
#856=FACE_BOUND('',#855,.T.);
#857=CARTESIAN_POINT('',(0.,53.0089651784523,-45.5250103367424));
#858=DIRECTION('',(1.,0.,0.));
#859=DIRECTION('',(0.,-0.258819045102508,-0.965925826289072));
#860=AXIS2_PLACEMENT_3D('',#857,#858,#859);
#861=CIRCLE('',#860,38.1);
#862=CARTESIAN_POINT('',(0.,81.6332099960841,-20.3801776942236));
#863=VERTEX_POINT('',#862);
#864=EDGE_CURVE('E635',#863,#31,#861,.T.);
#865=ORIENTED_EDGE('',*,*,#864,.T.);
#866=ORIENTED_EDGE('',*,*,#56,.F.);
#867=CARTESIAN_POINT('',(0.,62.9854681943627,30.2540534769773));
#868=DIRECTION('',(1.,0.,0.));
#869=DIRECTION('',(0.,0.,-1.));
#870=AXIS2_PLACEMENT_3D('',#867,#868,#869);
#871=CIRCLE('',#870,38.1);
#872=CARTESIAN_POINT('',(0.,84.1264039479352,-1.44248948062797));
#873=VERTEX_POINT('',#872);
#874=EDGE_CURVE('E1219',#873,#48,#871,.F.);
#875=ORIENTED_EDGE('',*,*,#874,.F.);
#876=CARTESIAN_POINT('',(0.,0.,0.));
#877=DIRECTION('',(1.,0.,0.));
#878=DIRECTION('',(0.,0.,-1.));
#879=AXIS2_PLACEMENT_3D('',#876,#877,#878);
#880=CIRCLE('',#879,84.13877);
#881=CARTESIAN_POINT('',(0.,84.1264039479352,1.44248948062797));
#882=VERTEX_POINT('',#881);
#883=EDGE_CURVE('E1182',#873,#882,#880,.T.);
#884=ORIENTED_EDGE('',*,*,#883,.T.);
#885=CARTESIAN_POINT('',(0.,62.9854681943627,-30.2540534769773));
#886=DIRECTION('',(1.,0.,0.));
#887=DIRECTION('',(0.,0.,-1.));
#888=AXIS2_PLACEMENT_3D('',#885,#886,#887);
#889=CIRCLE('',#888,38.1);
#890=CARTESIAN_POINT('',(0.,69.4685086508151,7.29032275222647));
#891=VERTEX_POINT('',#890);
#892=EDGE_CURVE('E1186',#882,#891,#889,.T.);
#893=ORIENTED_EDGE('',*,*,#892,.T.);
#894=CARTESIAN_POINT('',(0.,68.9883009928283,10.9378620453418));
#895=VERTEX_POINT('',#894);
#896=EDGE_CURVE('E1206',#895,#891,#55,.T.);
#897=ORIENTED_EDGE('',*,*,#896,.F.);
#898=CARTESIAN_POINT('',(0.,53.0089651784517,45.5250103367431));
#899=DIRECTION('',(1.,0.,0.));
#900=DIRECTION('',(0.,0.,-1.));
#901=AXIS2_PLACEMENT_3D('',#898,#899,#900);
#902=CIRCLE('',#901,38.1);
#903=CARTESIAN_POINT('',(0.,81.6332099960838,20.3801776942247));
#904=VERTEX_POINT('',#903);
#905=EDGE_CURVE('E1222',#904,#895,#902,.F.);
#906=ORIENTED_EDGE('',*,*,#905,.F.);
#907=CARTESIAN_POINT('',(0.,0.,0.));
#908=DIRECTION('',(1.,0.,0.));
#909=DIRECTION('',(0.,0.258819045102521,-0.965925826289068));
#910=AXIS2_PLACEMENT_3D('',#907,#908,#909);
#911=CIRCLE('',#910,84.13877);
#912=CARTESIAN_POINT('',(0.,80.8865224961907,23.1668533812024));
#913=VERTEX_POINT('',#912);
#914=EDGE_CURVE('E1158',#904,#913,#911,.T.);
#915=ORIENTED_EDGE('',*,*,#914,.T.);
#916=CARTESIAN_POINT('',(0.,68.6696156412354,-12.9213328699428));
#917=DIRECTION('',(1.,0.,0.));
#918=DIRECTION('',(0.,0.258819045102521,-0.965925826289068));
#919=AXIS2_PLACEMENT_3D('',#916,#917,#918);
#920=CIRCLE('',#919,38.1);
#921=CARTESIAN_POINT('',(0.,65.2145522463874,25.0216841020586));
#922=VERTEX_POINT('',#921);
#923=EDGE_CURVE('E1162',#913,#922,#920,.T.);
#924=ORIENTED_EDGE('',*,*,#923,.T.);
#925=CARTESIAN_POINT('',(0.,63.8066546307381,28.4206496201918));
#926=VERTEX_POINT('',#925);
#927=EDGE_CURVE('E1368',#926,#922,#55,.T.);
#928=ORIENTED_EDGE('',*,*,#927,.F.);
#929=CARTESIAN_POINT('',(0.,39.4199887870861,57.6935129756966));
#930=DIRECTION('',(1.,0.,0.));
#931=DIRECTION('',(0.,0.,-1.));
#932=AXIS2_PLACEMENT_3D('',#929,#930,#931);
#933=CIRCLE('',#932,38.1);
#934=CARTESIAN_POINT('',(0.,73.5768476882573,40.8139694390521));
#935=VERTEX_POINT('',#934);
#936=EDGE_CURVE('E1224',#935,#926,#933,.F.);
#937=ORIENTED_EDGE('',*,*,#936,.F.);
#938=CARTESIAN_POINT('',(0.,0.,0.));
#939=DIRECTION('',(1.,0.,0.));
#940=DIRECTION('',(0.,0.500000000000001,-0.866025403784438));
#941=AXIS2_PLACEMENT_3D('',#938,#939,#940);
#942=CIRCLE('',#941,84.13877);
#943=CARTESIAN_POINT('',(0.,72.1343582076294,43.3124345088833));
#944=VERTEX_POINT('',#943);
#945=EDGE_CURVE('E1134',#935,#944,#942,.T.);
#946=ORIENTED_EDGE('',*,*,#945,.T.);
#947=CARTESIAN_POINT('',(0.,69.6740422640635,5.29195521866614));
#948=DIRECTION('',(1.,0.,0.));
#949=DIRECTION('',(0.,0.500000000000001,-0.866025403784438));
#950=AXIS2_PLACEMENT_3D('',#947,#948,#949);
#951=CIRCLE('',#950,38.1);
#952=CARTESIAN_POINT('',(0.,56.5163318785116,41.0478590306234));
#953=VERTEX_POINT('',#952);
#954=EDGE_CURVE('E1138',#944,#953,#951,.T.);
#955=ORIENTED_EDGE('',*,*,#954,.T.);
#956=CARTESIAN_POINT('',(0.,54.2766902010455,43.9666168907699));
#957=VERTEX_POINT('',#956);
#958=EDGE_CURVE('E1363',#957,#953,#55,.T.);
#959=ORIENTED_EDGE('',*,*,#958,.F.);
#960=CARTESIAN_POINT('',(0.,23.1446053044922,65.9302980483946));
#961=DIRECTION('',(1.,0.,0.));
#962=DIRECTION('',(0.,0.,-1.));
#963=AXIS2_PLACEMENT_3D('',#960,#961,#962);
#964=CIRCLE('',#963,38.1);
#965=CARTESIAN_POINT('',(0.,60.506344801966,58.4663566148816));
#966=VERTEX_POINT('',#965);
#967=EDGE_CURVE('E1226',#966,#957,#964,.F.);
#968=ORIENTED_EDGE('',*,*,#967,.F.);
#969=CARTESIAN_POINT('',(0.,0.,0.));
#970=DIRECTION('',(1.,0.,0.));
#971=DIRECTION('',(0.,0.707106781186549,-0.707106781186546));
#972=AXIS2_PLACEMENT_3D('',#969,#970,#971);
#973=CIRCLE('',#972,84.13877);
#974=CARTESIAN_POINT('',(0.,58.4663566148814,60.5063448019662));
#975=VERTEX_POINT('',#974);
#976=EDGE_CURVE('E1110',#966,#975,#973,.T.);
#977=ORIENTED_EDGE('',*,*,#976,.T.);
#978=CARTESIAN_POINT('',(0.,65.9302980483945,23.1446053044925));
#979=DIRECTION('',(1.,0.,0.));
#980=DIRECTION('',(0.,0.707106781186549,-0.707106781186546));
#981=AXIS2_PLACEMENT_3D('',#978,#979,#980);
#982=CIRCLE('',#981,38.1);
#983=CARTESIAN_POINT('',(0.,43.9666168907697,54.2766902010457));
#984=VERTEX_POINT('',#983);
#985=EDGE_CURVE('E1114',#975,#984,#982,.T.);
#986=ORIENTED_EDGE('',*,*,#985,.T.);
#987=CARTESIAN_POINT('',(0.,41.0478590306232,56.5163318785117));
#988=VERTEX_POINT('',#987);
#989=EDGE_CURVE('E1358',#988,#984,#55,.T.);
#990=ORIENTED_EDGE('',*,*,#989,.F.);
#991=CARTESIAN_POINT('',(0.,5.2919552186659,69.6740422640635));
#992=DIRECTION('',(1.,0.,0.));
#993=DIRECTION('',(0.,0.,-1.));
#994=AXIS2_PLACEMENT_3D('',#991,#992,#993);
#995=CIRCLE('',#994,38.1);
#996=CARTESIAN_POINT('',(0.,43.3124345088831,72.1343582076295));
#997=VERTEX_POINT('',#996);
#998=EDGE_CURVE('E1228',#997,#988,#995,.F.);
#999=ORIENTED_EDGE('',*,*,#998,.F.);
#1000=CARTESIAN_POINT('',(0.,0.,0.));
#1001=DIRECTION('',(1.,0.,0.));
#1002=DIRECTION('',(0.,0.86602540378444,-0.499999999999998));
#1003=AXIS2_PLACEMENT_3D('',#1000,#1001,#1002);
#1004=CIRCLE('',#1003,84.13877);
#1005=CARTESIAN_POINT('',(0.,40.8139694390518,73.5768476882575));
#1006=VERTEX_POINT('',#1005);
#1007=EDGE_CURVE('E1086',#997,#1006,#1004,.T.);
#1008=ORIENTED_EDGE('',*,*,#1007,.T.);
#1009=CARTESIAN_POINT('',(0.,57.6935129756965,39.4199887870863));
#1010=DIRECTION('',(1.,0.,0.));
#1011=DIRECTION('',(0.,0.86602540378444,-0.499999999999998));
#1012=AXIS2_PLACEMENT_3D('',#1009,#1010,#1011);
#1013=CIRCLE('',#1012,38.1);
#1014=CARTESIAN_POINT('',(0.,28.4206496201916,63.8066546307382));
#1015=VERTEX_POINT('',#1014);
#1016=EDGE_CURVE('E1090',#1006,#1015,#1013,.T.);
#1017=ORIENTED_EDGE('',*,*,#1016,.T.);
#1018=CARTESIAN_POINT('',(0.,25.0216841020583,65.2145522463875));
#1019=VERTEX_POINT('',#1018);
#1020=EDGE_CURVE('E1353',#1019,#1015,#55,.T.);
#1021=ORIENTED_EDGE('',*,*,#1020,.F.);
#1022=CARTESIAN_POINT('',(0.,-12.921332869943,68.6696156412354));
#1023=DIRECTION('',(1.,0.,0.));
#1024=DIRECTION('',(0.,0.,-1.));
#1025=AXIS2_PLACEMENT_3D('',#1022,#1023,#1024);
#1026=CIRCLE('',#1025,38.1);
#1027=CARTESIAN_POINT('',(0.,23.1668533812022,80.8865224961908));
#1028=VERTEX_POINT('',#1027);
#1029=EDGE_CURVE('E1230',#1028,#1019,#1026,.F.);
#1030=ORIENTED_EDGE('',*,*,#1029,.F.);
#1031=CARTESIAN_POINT('',(0.,0.,0.));
#1032=DIRECTION('',(1.,0.,0.));
#1033=DIRECTION('',(0.,0.965925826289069,-0.258819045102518));
#1034=AXIS2_PLACEMENT_3D('',#1031,#1032,#1033);
#1035=CIRCLE('',#1034,84.13877);
#1036=CARTESIAN_POINT('',(0.,20.3801776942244,81.6332099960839));
#1037=VERTEX_POINT('',#1036);
#1038=EDGE_CURVE('E1062',#1028,#1037,#1035,.T.);
#1039=ORIENTED_EDGE('',*,*,#1038,.T.);
#1040=CARTESIAN_POINT('',(0.,45.5250103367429,53.0089651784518));
#1041=DIRECTION('',(1.,0.,0.));
#1042=DIRECTION('',(0.,0.965925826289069,-0.258819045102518));
#1043=AXIS2_PLACEMENT_3D('',#1040,#1041,#1042);
#1044=CIRCLE('',#1043,38.1);
#1045=CARTESIAN_POINT('',(0.,10.9378620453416,68.9883009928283));
#1046=VERTEX_POINT('',#1045);
#1047=EDGE_CURVE('E1066',#1037,#1046,#1044,.T.);
#1048=ORIENTED_EDGE('',*,*,#1047,.T.);
#1049=CARTESIAN_POINT('',(0.,7.29032275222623,69.4685086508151));
#1050=VERTEX_POINT('',#1049);
#1051=EDGE_CURVE('E1348',#1050,#1046,#55,.T.);
#1052=ORIENTED_EDGE('',*,*,#1051,.F.);
#1053=CARTESIAN_POINT('',(0.,-30.2540534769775,62.9854681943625));
#1054=DIRECTION('',(1.,0.,0.));
#1055=DIRECTION('',(0.,0.,-1.));
#1056=AXIS2_PLACEMENT_3D('',#1053,#1054,#1055);
#1057=CIRCLE('',#1056,38.1);
#1058=CARTESIAN_POINT('',(0.,1.44248948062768,84.1264039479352));
#1059=VERTEX_POINT('',#1058);
#1060=EDGE_CURVE('E1232',#1059,#1050,#1057,.F.);
#1061=ORIENTED_EDGE('',*,*,#1060,.F.);
#1062=CARTESIAN_POINT('',(0.,0.,0.));
#1063=DIRECTION('',(1.,0.,0.));
#1064=DIRECTION('',(0.,1.,0.));
#1065=AXIS2_PLACEMENT_3D('',#1062,#1063,#1064);
#1066=CIRCLE('',#1065,84.13877);
#1067=CARTESIAN_POINT('',(0.,-1.44248948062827,84.1264039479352));
#1068=VERTEX_POINT('',#1067);
#1069=EDGE_CURVE('E1038',#1059,#1068,#1066,.T.);
#1070=ORIENTED_EDGE('',*,*,#1069,.T.);
#1071=CARTESIAN_POINT('',(0.,30.2540534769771,62.9854681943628));
#1072=DIRECTION('',(1.,0.,0.));
#1073=DIRECTION('',(0.,1.,0.));
#1074=AXIS2_PLACEMENT_3D('',#1071,#1072,#1073);
#1075=CIRCLE('',#1074,38.1);
#1076=CARTESIAN_POINT('',(0.,-7.29032275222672,69.4685086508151));
#1077=VERTEX_POINT('',#1076);
#1078=EDGE_CURVE('E1042',#1068,#1077,#1075,.T.);
#1079=ORIENTED_EDGE('',*,*,#1078,.T.);
#1080=CARTESIAN_POINT('',(0.,-10.9378620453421,68.9883009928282));
#1081=VERTEX_POINT('',#1080);
#1082=EDGE_CURVE('E1343',#1081,#1077,#55,.T.);
#1083=ORIENTED_EDGE('',*,*,#1082,.F.);
#1084=CARTESIAN_POINT('',(0.,-45.5250103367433,53.0089651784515));
#1085=DIRECTION('',(1.,0.,0.));
#1086=DIRECTION('',(0.,0.,-1.));
#1087=AXIS2_PLACEMENT_3D('',#1084,#1085,#1086);
#1088=CIRCLE('',#1087,38.1);
#1089=CARTESIAN_POINT('',(0.,-20.380177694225,81.6332099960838));
#1090=VERTEX_POINT('',#1089);
#1091=EDGE_CURVE('E1234',#1090,#1081,#1088,.F.);
#1092=ORIENTED_EDGE('',*,*,#1091,.F.);
#1093=CARTESIAN_POINT('',(0.,0.,0.));
#1094=DIRECTION('',(1.,0.,0.));
#1095=DIRECTION('',(0.,0.965925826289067,0.258819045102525));
#1096=AXIS2_PLACEMENT_3D('',#1093,#1094,#1095);
#1097=CIRCLE('',#1096,84.13877);
#1098=CARTESIAN_POINT('',(0.,-23.1668533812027,80.8865224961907));
#1099=VERTEX_POINT('',#1098);
#1100=EDGE_CURVE('E1014',#1090,#1099,#1097,.T.);
#1101=ORIENTED_EDGE('',*,*,#1100,.T.);
#1102=CARTESIAN_POINT('',(0.,12.9213328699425,68.6696156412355));
#1103=DIRECTION('',(1.,0.,0.));
#1104=DIRECTION('',(0.,0.965925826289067,0.258819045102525));
#1105=AXIS2_PLACEMENT_3D('',#1102,#1103,#1104);
#1106=CIRCLE('',#1105,38.1);
#1107=CARTESIAN_POINT('',(0.,-25.0216841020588,65.2145522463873));
#1108=VERTEX_POINT('',#1107);
#1109=EDGE_CURVE('E1018',#1099,#1108,#1106,.T.);
#1110=ORIENTED_EDGE('',*,*,#1109,.T.);
#1111=CARTESIAN_POINT('',(0.,-28.420649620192,63.806654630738));
#1112=VERTEX_POINT('',#1111);
#1113=EDGE_CURVE('E1338',#1112,#1108,#55,.T.);
#1114=ORIENTED_EDGE('',*,*,#1113,.F.);
#1115=CARTESIAN_POINT('',(0.,-57.6935129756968,39.4199887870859));
#1116=DIRECTION('',(1.,0.,0.));
#1117=DIRECTION('',(0.,0.,-1.));
#1118=AXIS2_PLACEMENT_3D('',#1115,#1116,#1117);
#1119=CIRCLE('',#1118,38.1);
#1120=CARTESIAN_POINT('',(0.,-40.8139694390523,73.5768476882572));
#1121=VERTEX_POINT('',#1120);
#1122=EDGE_CURVE('E1236',#1121,#1112,#1119,.F.);
#1123=ORIENTED_EDGE('',*,*,#1122,.F.);
#1124=CARTESIAN_POINT('',(0.,0.,0.));
#1125=DIRECTION('',(1.,0.,0.));
#1126=DIRECTION('',(0.,0.866025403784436,0.500000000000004));
#1127=AXIS2_PLACEMENT_3D('',#1124,#1125,#1126);
#1128=CIRCLE('',#1127,84.13877);
#1129=CARTESIAN_POINT('',(0.,-43.3124345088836,72.1343582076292));
#1130=VERTEX_POINT('',#1129);
#1131=EDGE_CURVE('E990',#1121,#1130,#1128,.T.);
#1132=ORIENTED_EDGE('',*,*,#1131,.T.);
#1133=CARTESIAN_POINT('',(0.,-5.29195521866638,69.6740422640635));
#1134=DIRECTION('',(1.,0.,0.));
#1135=DIRECTION('',(0.,0.866025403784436,0.500000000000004));
#1136=AXIS2_PLACEMENT_3D('',#1133,#1134,#1135);
#1137=CIRCLE('',#1136,38.1);
#1138=CARTESIAN_POINT('',(0.,-41.0478590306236,56.5163318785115));
#1139=VERTEX_POINT('',#1138);
#1140=EDGE_CURVE('E994',#1130,#1139,#1137,.T.);
#1141=ORIENTED_EDGE('',*,*,#1140,.T.);
#1142=CARTESIAN_POINT('',(0.,-43.9666168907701,54.2766902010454));
#1143=VERTEX_POINT('',#1142);
#1144=EDGE_CURVE('E1333',#1143,#1139,#55,.T.);
#1145=ORIENTED_EDGE('',*,*,#1144,.F.);
#1146=CARTESIAN_POINT('',(0.,-65.9302980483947,23.144605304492));
#1147=DIRECTION('',(1.,0.,0.));
#1148=DIRECTION('',(0.,0.,-1.));
#1149=AXIS2_PLACEMENT_3D('',#1146,#1147,#1148);
#1150=CIRCLE('',#1149,38.1);
#1151=CARTESIAN_POINT('',(0.,-58.4663566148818,60.5063448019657));
#1152=VERTEX_POINT('',#1151);
#1153=EDGE_CURVE('E1238',#1152,#1143,#1150,.F.);
#1154=ORIENTED_EDGE('',*,*,#1153,.F.);
#1155=CARTESIAN_POINT('',(0.,0.,0.));
#1156=DIRECTION('',(1.,0.,0.));
#1157=DIRECTION('',(0.,0.707106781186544,0.707106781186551));
#1158=AXIS2_PLACEMENT_3D('',#1155,#1156,#1157);
#1159=CIRCLE('',#1158,84.13877);
#1160=CARTESIAN_POINT('',(0.,-60.5063448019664,58.4663566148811));
#1161=VERTEX_POINT('',#1160);
#1162=EDGE_CURVE('E966',#1152,#1161,#1159,.T.);
#1163=ORIENTED_EDGE('',*,*,#1162,.T.);
#1164=CARTESIAN_POINT('',(0.,-23.1446053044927,65.9302980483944));
#1165=DIRECTION('',(1.,0.,0.));
#1166=DIRECTION('',(0.,0.707106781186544,0.707106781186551));
#1167=AXIS2_PLACEMENT_3D('',#1164,#1165,#1166);
#1168=CIRCLE('',#1167,38.1);
#1169=CARTESIAN_POINT('',(0.,-54.2766902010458,43.9666168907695));
#1170=VERTEX_POINT('',#1169);
#1171=EDGE_CURVE('E970',#1161,#1170,#1168,.T.);
#1172=ORIENTED_EDGE('',*,*,#1171,.T.);
#1173=CARTESIAN_POINT('',(0.,-56.5163318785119,41.047859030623));
#1174=VERTEX_POINT('',#1173);
#1175=EDGE_CURVE('E1328',#1174,#1170,#55,.T.);
#1176=ORIENTED_EDGE('',*,*,#1175,.F.);
#1177=CARTESIAN_POINT('',(0.,-69.6740422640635,5.29195521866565));
#1178=DIRECTION('',(1.,0.,0.));
#1179=DIRECTION('',(0.,0.,-1.));
#1180=AXIS2_PLACEMENT_3D('',#1177,#1178,#1179);
#1181=CIRCLE('',#1180,38.1);
#1182=CARTESIAN_POINT('',(0.,-72.1343582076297,43.3124345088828));
#1183=VERTEX_POINT('',#1182);
#1184=EDGE_CURVE('E1240',#1183,#1174,#1181,.F.);
#1185=ORIENTED_EDGE('',*,*,#1184,.F.);
#1186=CARTESIAN_POINT('',(0.,0.,0.));
#1187=DIRECTION('',(1.,0.,0.));
#1188=DIRECTION('',(0.,0.499999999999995,0.866025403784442));
#1189=AXIS2_PLACEMENT_3D('',#1186,#1187,#1188);
#1190=CIRCLE('',#1189,84.13877);
#1191=CARTESIAN_POINT('',(0.,-73.5768476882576,40.8139694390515));
#1192=VERTEX_POINT('',#1191);
#1193=EDGE_CURVE('E942',#1183,#1192,#1190,.T.);
#1194=ORIENTED_EDGE('',*,*,#1193,.T.);
#1195=CARTESIAN_POINT('',(0.,-39.4199887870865,57.6935129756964));
#1196=DIRECTION('',(1.,0.,0.));
#1197=DIRECTION('',(0.,0.499999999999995,0.866025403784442));
#1198=AXIS2_PLACEMENT_3D('',#1195,#1196,#1197);
#1199=CIRCLE('',#1198,38.1);
#1200=CARTESIAN_POINT('',(0.,-63.8066546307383,28.4206496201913));
#1201=VERTEX_POINT('',#1200);
#1202=EDGE_CURVE('E946',#1192,#1201,#1199,.T.);
#1203=ORIENTED_EDGE('',*,*,#1202,.T.);
#1204=CARTESIAN_POINT('',(0.,-65.2145522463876,25.0216841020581));
#1205=VERTEX_POINT('',#1204);
#1206=EDGE_CURVE('E1323',#1205,#1201,#55,.T.);
#1207=ORIENTED_EDGE('',*,*,#1206,.F.);
#1208=CARTESIAN_POINT('',(0.,-68.6696156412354,-12.9213328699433));
#1209=DIRECTION('',(1.,0.,0.));
#1210=DIRECTION('',(0.,0.,-1.));
#1211=AXIS2_PLACEMENT_3D('',#1208,#1209,#1210);
#1212=CIRCLE('',#1211,38.1);
#1213=CARTESIAN_POINT('',(0.,-80.8865224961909,23.1668533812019));
#1214=VERTEX_POINT('',#1213);
#1215=EDGE_CURVE('E1242',#1214,#1205,#1212,.F.);
#1216=ORIENTED_EDGE('',*,*,#1215,.F.);
#1217=CARTESIAN_POINT('',(0.,0.,0.));
#1218=DIRECTION('',(1.,0.,0.));
#1219=DIRECTION('',(0.,0.258819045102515,0.96592582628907));
#1220=AXIS2_PLACEMENT_3D('',#1217,#1218,#1219);
#1221=CIRCLE('',#1220,84.13877);
#1222=CARTESIAN_POINT('',(0.,-81.633209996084,20.3801776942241));
#1223=VERTEX_POINT('',#1222);
#1224=EDGE_CURVE('E918',#1214,#1223,#1221,.T.);
#1225=ORIENTED_EDGE('',*,*,#1224,.T.);
#1226=CARTESIAN_POINT('',(0.,-53.008965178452,45.5250103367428));
#1227=DIRECTION('',(1.,0.,0.));
#1228=DIRECTION('',(0.,0.258819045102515,0.96592582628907));
#1229=AXIS2_PLACEMENT_3D('',#1226,#1227,#1228);
#1230=CIRCLE('',#1229,38.1);
#1231=CARTESIAN_POINT('',(0.,-68.9883009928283,10.9378620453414));
#1232=VERTEX_POINT('',#1231);
#1233=EDGE_CURVE('E922',#1223,#1232,#1230,.T.);
#1234=ORIENTED_EDGE('',*,*,#1233,.T.);
#1235=CARTESIAN_POINT('',(0.,-69.4685086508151,7.29032275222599));
#1236=VERTEX_POINT('',#1235);
#1237=EDGE_CURVE('E1318',#1236,#1232,#55,.T.);
#1238=ORIENTED_EDGE('',*,*,#1237,.F.);
#1239=CARTESIAN_POINT('',(0.,-62.9854681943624,-30.2540534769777));
#1240=DIRECTION('',(1.,0.,0.));
#1241=DIRECTION('',(0.,0.,-1.));
#1242=AXIS2_PLACEMENT_3D('',#1239,#1240,#1241);
#1243=CIRCLE('',#1242,38.1);
#1244=CARTESIAN_POINT('',(0.,-84.1264039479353,1.44248948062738));
#1245=VERTEX_POINT('',#1244);
#1246=EDGE_CURVE('E1244',#1245,#1236,#1243,.F.);
#1247=ORIENTED_EDGE('',*,*,#1246,.F.);
#1248=CARTESIAN_POINT('',(0.,0.,0.));
#1249=DIRECTION('',(1.,0.,0.));
#1250=DIRECTION('',(0.,0.,1.));
#1251=AXIS2_PLACEMENT_3D('',#1248,#1249,#1250);
#1252=CIRCLE('',#1251,84.13877);
#1253=CARTESIAN_POINT('',(0.,-84.1264039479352,-1.44248948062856));
#1254=VERTEX_POINT('',#1253);
#1255=EDGE_CURVE('E894',#1245,#1254,#1252,.T.);
#1256=ORIENTED_EDGE('',*,*,#1255,.T.);
#1257=CARTESIAN_POINT('',(0.,-62.9854681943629,30.2540534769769));
#1258=DIRECTION('',(1.,0.,0.));
#1259=DIRECTION('',(0.,0.,1.));
#1260=AXIS2_PLACEMENT_3D('',#1257,#1258,#1259);
#1261=CIRCLE('',#1260,38.1);
#1262=CARTESIAN_POINT('',(0.,-69.468508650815,-7.29032275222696));
#1263=VERTEX_POINT('',#1262);
#1264=EDGE_CURVE('E898',#1254,#1263,#1261,.T.);
#1265=ORIENTED_EDGE('',*,*,#1264,.T.);
#1266=CARTESIAN_POINT('',(0.,-68.9883009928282,-10.9378620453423));
#1267=VERTEX_POINT('',#1266);
#1268=EDGE_CURVE('E1313',#1267,#1263,#55,.T.);
#1269=ORIENTED_EDGE('',*,*,#1268,.F.);
#1270=CARTESIAN_POINT('',(0.,-53.0089651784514,-45.5250103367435));
#1271=DIRECTION('',(1.,0.,0.));
#1272=DIRECTION('',(0.,0.,-1.));
#1273=AXIS2_PLACEMENT_3D('',#1270,#1271,#1272);
#1274=CIRCLE('',#1273,38.1);
#1275=CARTESIAN_POINT('',(0.,-81.6332099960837,-20.3801776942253));
#1276=VERTEX_POINT('',#1275);
#1277=EDGE_CURVE('E1246',#1276,#1267,#1274,.F.);
#1278=ORIENTED_EDGE('',*,*,#1277,.F.);
#1279=CARTESIAN_POINT('',(0.,0.,0.));
#1280=DIRECTION('',(1.,0.,0.));
#1281=DIRECTION('',(0.,-0.258819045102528,0.965925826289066));
#1282=AXIS2_PLACEMENT_3D('',#1279,#1280,#1281);
#1283=CIRCLE('',#1282,84.13877);
#1284=CARTESIAN_POINT('',(0.,-80.8865224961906,-23.166853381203));
#1285=VERTEX_POINT('',#1284);
#1286=EDGE_CURVE('E870',#1276,#1285,#1283,.T.);
#1287=ORIENTED_EDGE('',*,*,#1286,.T.);
#1288=CARTESIAN_POINT('',(0.,-68.6696156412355,12.9213328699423));
#1289=DIRECTION('',(1.,0.,0.));
#1290=DIRECTION('',(0.,-0.258819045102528,0.965925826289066));
#1291=AXIS2_PLACEMENT_3D('',#1288,#1289,#1290);
#1292=CIRCLE('',#1291,38.1);
#1293=CARTESIAN_POINT('',(0.,-65.2145522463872,-25.021684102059));
#1294=VERTEX_POINT('',#1293);
#1295=EDGE_CURVE('E874',#1285,#1294,#1292,.T.);
#1296=ORIENTED_EDGE('',*,*,#1295,.T.);
#1297=CARTESIAN_POINT('',(0.,-63.8066546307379,-28.4206496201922));
#1298=VERTEX_POINT('',#1297);
#1299=EDGE_CURVE('E1308',#1298,#1294,#55,.T.);
#1300=ORIENTED_EDGE('',*,*,#1299,.F.);
#1301=CARTESIAN_POINT('',(0.,-39.4199887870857,-57.6935129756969));
#1302=DIRECTION('',(1.,0.,0.));
#1303=DIRECTION('',(0.,0.,-1.));
#1304=AXIS2_PLACEMENT_3D('',#1301,#1302,#1303);
#1305=CIRCLE('',#1304,38.1);
#1306=CARTESIAN_POINT('',(0.,-73.5768476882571,-40.8139694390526));
#1307=VERTEX_POINT('',#1306);
#1308=EDGE_CURVE('E1248',#1307,#1298,#1305,.F.);
#1309=ORIENTED_EDGE('',*,*,#1308,.F.);
#1310=CARTESIAN_POINT('',(0.,0.,0.));
#1311=DIRECTION('',(1.,0.,0.));
#1312=DIRECTION('',(0.,-0.500000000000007,0.866025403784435));
#1313=AXIS2_PLACEMENT_3D('',#1310,#1311,#1312);
#1314=CIRCLE('',#1313,84.13877);
#1315=CARTESIAN_POINT('',(0.,-72.1343582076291,-43.3124345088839));
#1316=VERTEX_POINT('',#1315);
#1317=EDGE_CURVE('E846',#1307,#1316,#1314,.T.);
#1318=ORIENTED_EDGE('',*,*,#1317,.T.);
#1319=CARTESIAN_POINT('',(0.,-69.6740422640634,-5.29195521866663));
#1320=DIRECTION('',(1.,0.,0.));
#1321=DIRECTION('',(0.,-0.500000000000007,0.866025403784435));
#1322=AXIS2_PLACEMENT_3D('',#1319,#1320,#1321);
#1323=CIRCLE('',#1322,38.1);
#1324=CARTESIAN_POINT('',(0.,-56.5163318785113,-41.0478590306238));
#1325=VERTEX_POINT('',#1324);
#1326=EDGE_CURVE('E850',#1316,#1325,#1323,.T.);
#1327=ORIENTED_EDGE('',*,*,#1326,.T.);
#1328=CARTESIAN_POINT('',(0.,-54.2766902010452,-43.9666168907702));
#1329=VERTEX_POINT('',#1328);
#1330=EDGE_CURVE('E1303',#1329,#1325,#55,.T.);
#1331=ORIENTED_EDGE('',*,*,#1330,.F.);
#1332=CARTESIAN_POINT('',(0.,-23.1446053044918,-65.9302980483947));
#1333=DIRECTION('',(1.,0.,0.));
#1334=DIRECTION('',(0.,0.,-1.));
#1335=AXIS2_PLACEMENT_3D('',#1332,#1333,#1334);
#1336=CIRCLE('',#1335,38.1);
#1337=CARTESIAN_POINT('',(0.,-60.5063448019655,-58.466356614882));
#1338=VERTEX_POINT('',#1337);
#1339=EDGE_CURVE('E1250',#1338,#1329,#1336,.F.);
#1340=ORIENTED_EDGE('',*,*,#1339,.F.);
#1341=CARTESIAN_POINT('',(0.,0.,0.));
#1342=DIRECTION('',(1.,0.,0.));
#1343=DIRECTION('',(0.,-0.707106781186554,0.707106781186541));
#1344=AXIS2_PLACEMENT_3D('',#1341,#1342,#1343);
#1345=CIRCLE('',#1344,84.13877);
#1346=CARTESIAN_POINT('',(0.,-58.4663566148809,-60.5063448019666));
#1347=VERTEX_POINT('',#1346);
#1348=EDGE_CURVE('E822',#1338,#1347,#1345,.T.);
#1349=ORIENTED_EDGE('',*,*,#1348,.T.);
#1350=CARTESIAN_POINT('',(0.,-65.9302980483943,-23.1446053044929));
#1351=DIRECTION('',(1.,0.,0.));
#1352=DIRECTION('',(0.,-0.707106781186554,0.707106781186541));
#1353=AXIS2_PLACEMENT_3D('',#1350,#1351,#1352);
#1354=CIRCLE('',#1353,38.1);
#1355=CARTESIAN_POINT('',(0.,-43.9666168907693,-54.276690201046));
#1356=VERTEX_POINT('',#1355);
#1357=EDGE_CURVE('E826',#1347,#1356,#1354,.T.);
#1358=ORIENTED_EDGE('',*,*,#1357,.T.);
#1359=CARTESIAN_POINT('',(0.,-41.0478590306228,-56.516331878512));
#1360=VERTEX_POINT('',#1359);
#1361=EDGE_CURVE('E1298',#1360,#1356,#55,.T.);
#1362=ORIENTED_EDGE('',*,*,#1361,.F.);
#1363=CARTESIAN_POINT('',(0.,-5.29195521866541,-69.6740422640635));
#1364=DIRECTION('',(1.,0.,0.));
#1365=DIRECTION('',(0.,0.,-1.));
#1366=AXIS2_PLACEMENT_3D('',#1363,#1364,#1365);
#1367=CIRCLE('',#1366,38.1);
#1368=CARTESIAN_POINT('',(0.,-43.3124345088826,-72.1343582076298));
#1369=VERTEX_POINT('',#1368);
#1370=EDGE_CURVE('E1252',#1369,#1360,#1367,.F.);
#1371=ORIENTED_EDGE('',*,*,#1370,.F.);
#1372=CARTESIAN_POINT('',(0.,0.,0.));
#1373=DIRECTION('',(1.,0.,0.));
#1374=DIRECTION('',(0.,-0.866025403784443,0.499999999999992));
#1375=AXIS2_PLACEMENT_3D('',#1372,#1373,#1374);
#1376=CIRCLE('',#1375,84.13877);
#1377=CARTESIAN_POINT('',(0.,-40.8139694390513,-73.5768476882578));
#1378=VERTEX_POINT('',#1377);
#1379=EDGE_CURVE('E798',#1369,#1378,#1376,.T.);
#1380=ORIENTED_EDGE('',*,*,#1379,.T.);
#1381=CARTESIAN_POINT('',(0.,-57.6935129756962,-39.4199887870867));
#1382=DIRECTION('',(1.,0.,0.));
#1383=DIRECTION('',(0.,-0.866025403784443,0.499999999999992));
#1384=AXIS2_PLACEMENT_3D('',#1381,#1382,#1383);
#1385=CIRCLE('',#1384,38.1);
#1386=CARTESIAN_POINT('',(0.,-28.4206496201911,-63.8066546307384));
#1387=VERTEX_POINT('',#1386);
#1388=EDGE_CURVE('E802',#1378,#1387,#1385,.T.);
#1389=ORIENTED_EDGE('',*,*,#1388,.T.);
#1390=CARTESIAN_POINT('',(0.,-25.0216841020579,-65.2145522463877));
#1391=VERTEX_POINT('',#1390);
#1392=EDGE_CURVE('E1293',#1391,#1387,#55,.T.);
#1393=ORIENTED_EDGE('',*,*,#1392,.F.);
#1394=CARTESIAN_POINT('',(0.,12.9213328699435,-68.6696156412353));
#1395=DIRECTION('',(1.,0.,0.));
#1396=DIRECTION('',(0.,0.,-1.));
#1397=AXIS2_PLACEMENT_3D('',#1394,#1395,#1396);
#1398=CIRCLE('',#1397,38.1);
#1399=CARTESIAN_POINT('',(0.,-23.1668533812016,-80.886522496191));
#1400=VERTEX_POINT('',#1399);
#1401=EDGE_CURVE('E1254',#1400,#1391,#1398,.F.);
#1402=ORIENTED_EDGE('',*,*,#1401,.F.);
#1403=CARTESIAN_POINT('',(0.,0.,0.));
#1404=DIRECTION('',(1.,0.,0.));
#1405=DIRECTION('',(0.,-0.965925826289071,0.258819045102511));
#1406=AXIS2_PLACEMENT_3D('',#1403,#1404,#1405);
#1407=CIRCLE('',#1406,84.13877);
#1408=CARTESIAN_POINT('',(0.,-20.3801776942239,-81.6332099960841));
#1409=VERTEX_POINT('',#1408);
#1410=EDGE_CURVE('E774',#1400,#1409,#1407,.T.);
#1411=ORIENTED_EDGE('',*,*,#1410,.T.);
#1412=CARTESIAN_POINT('',(0.,-45.5250103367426,-53.0089651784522));
#1413=DIRECTION('',(1.,0.,0.));
#1414=DIRECTION('',(0.,-0.965925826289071,0.258819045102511));
#1415=AXIS2_PLACEMENT_3D('',#1412,#1413,#1414);
#1416=CIRCLE('',#1415,38.1);
#1417=CARTESIAN_POINT('',(0.,-10.9378620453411,-68.9883009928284));
#1418=VERTEX_POINT('',#1417);
#1419=EDGE_CURVE('E778',#1409,#1418,#1416,.T.);
#1420=ORIENTED_EDGE('',*,*,#1419,.T.);
#1421=CARTESIAN_POINT('',(0.,-7.29032275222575,-69.4685086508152));
#1422=VERTEX_POINT('',#1421);
#1423=EDGE_CURVE('E1288',#1422,#1418,#55,.T.);
#1424=ORIENTED_EDGE('',*,*,#1423,.F.);
#1425=CARTESIAN_POINT('',(0.,30.254053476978,-62.9854681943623));
#1426=DIRECTION('',(1.,0.,0.));
#1427=DIRECTION('',(0.,0.,-1.));
#1428=AXIS2_PLACEMENT_3D('',#1425,#1426,#1427);
#1429=CIRCLE('',#1428,38.1);
#1430=CARTESIAN_POINT('',(0.,-1.44248948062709,-84.1264039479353));
#1431=VERTEX_POINT('',#1430);
#1432=EDGE_CURVE('E1256',#1431,#1422,#1429,.F.);
#1433=ORIENTED_EDGE('',*,*,#1432,.F.);
#1434=CARTESIAN_POINT('',(0.,0.,0.));
#1435=DIRECTION('',(1.,0.,0.));
#1436=DIRECTION('',(0.,-1.,0.));
#1437=AXIS2_PLACEMENT_3D('',#1434,#1435,#1436);
#1438=CIRCLE('',#1437,84.13877);
#1439=CARTESIAN_POINT('',(0.,1.44248948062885,-84.1264039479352));
#1440=VERTEX_POINT('',#1439);
#1441=EDGE_CURVE('E750',#1431,#1440,#1438,.T.);
#1442=ORIENTED_EDGE('',*,*,#1441,.T.);
#1443=CARTESIAN_POINT('',(0.,-30.2540534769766,-62.985468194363));
#1444=DIRECTION('',(1.,0.,0.));
#1445=DIRECTION('',(0.,-1.,0.));
#1446=AXIS2_PLACEMENT_3D('',#1443,#1444,#1445);
#1447=CIRCLE('',#1446,38.1);
#1448=CARTESIAN_POINT('',(0.,7.2903227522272,-69.468508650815));
#1449=VERTEX_POINT('',#1448);
#1450=EDGE_CURVE('E754',#1440,#1449,#1447,.T.);
#1451=ORIENTED_EDGE('',*,*,#1450,.T.);
#1452=CARTESIAN_POINT('',(0.,10.9378620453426,-68.9883009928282));
#1453=VERTEX_POINT('',#1452);
#1454=EDGE_CURVE('E1283',#1453,#1449,#55,.T.);
#1455=ORIENTED_EDGE('',*,*,#1454,.F.);
#1456=CARTESIAN_POINT('',(0.,45.5250103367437,-53.0089651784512));
#1457=DIRECTION('',(1.,0.,0.));
#1458=DIRECTION('',(0.,0.,-1.));
#1459=AXIS2_PLACEMENT_3D('',#1456,#1457,#1458);
#1460=CIRCLE('',#1459,38.1);
#1461=CARTESIAN_POINT('',(0.,20.3801776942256,-81.6332099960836));
#1462=VERTEX_POINT('',#1461);
#1463=EDGE_CURVE('E1258',#1462,#1453,#1460,.F.);
#1464=ORIENTED_EDGE('',*,*,#1463,.F.);
#1465=CARTESIAN_POINT('',(0.,0.,0.));
#1466=DIRECTION('',(1.,0.,0.));
#1467=DIRECTION('',(0.,-0.965925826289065,-0.258819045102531));
#1468=AXIS2_PLACEMENT_3D('',#1465,#1466,#1467);
#1469=CIRCLE('',#1468,84.13877);
#1470=CARTESIAN_POINT('',(0.,23.1668533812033,-80.8865224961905));
#1471=VERTEX_POINT('',#1470);
#1472=EDGE_CURVE('E726',#1462,#1471,#1469,.T.);
#1473=ORIENTED_EDGE('',*,*,#1472,.T.);
#1474=CARTESIAN_POINT('',(0.,-12.9213328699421,-68.6696156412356));
#1475=DIRECTION('',(1.,0.,0.));
#1476=DIRECTION('',(0.,-0.965925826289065,-0.258819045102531));
#1477=AXIS2_PLACEMENT_3D('',#1474,#1475,#1476);
#1478=CIRCLE('',#1477,38.1);
#1479=CARTESIAN_POINT('',(0.,25.0216841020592,-65.2145522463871));
#1480=VERTEX_POINT('',#1479);
#1481=EDGE_CURVE('E730',#1471,#1480,#1478,.T.);
#1482=ORIENTED_EDGE('',*,*,#1481,.T.);
#1483=CARTESIAN_POINT('',(0.,28.4206496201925,-63.8066546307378));
#1484=VERTEX_POINT('',#1483);
#1485=EDGE_CURVE('E1278',#1484,#1480,#55,.T.);
#1486=ORIENTED_EDGE('',*,*,#1485,.F.);
#1487=CARTESIAN_POINT('',(0.,57.6935129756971,-39.4199887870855));
#1488=DIRECTION('',(1.,0.,0.));
#1489=DIRECTION('',(0.,0.,-1.));
#1490=AXIS2_PLACEMENT_3D('',#1487,#1488,#1489);
#1491=CIRCLE('',#1490,38.1);
#1492=CARTESIAN_POINT('',(0.,40.8139694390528,-73.5768476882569));
#1493=VERTEX_POINT('',#1492);
#1494=EDGE_CURVE('E1260',#1493,#1484,#1491,.F.);
#1495=ORIENTED_EDGE('',*,*,#1494,.F.);
#1496=CARTESIAN_POINT('',(0.,0.,0.));
#1497=DIRECTION('',(1.,0.,0.));
#1498=DIRECTION('',(0.,-0.866025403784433,-0.50000000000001));
#1499=AXIS2_PLACEMENT_3D('',#1496,#1497,#1498);
#1500=CIRCLE('',#1499,84.13877);
#1501=CARTESIAN_POINT('',(0.,43.3124345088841,-72.1343582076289));
#1502=VERTEX_POINT('',#1501);
#1503=EDGE_CURVE('E702',#1493,#1502,#1500,.T.);
#1504=ORIENTED_EDGE('',*,*,#1503,.T.);
#1505=CARTESIAN_POINT('',(0.,5.29195521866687,-69.6740422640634));
#1506=DIRECTION('',(1.,0.,0.));
#1507=DIRECTION('',(0.,-0.866025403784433,-0.50000000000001));
#1508=AXIS2_PLACEMENT_3D('',#1505,#1506,#1507);
#1509=CIRCLE('',#1508,38.1);
#1510=CARTESIAN_POINT('',(0.,41.047859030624,-56.5163318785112));
#1511=VERTEX_POINT('',#1510);
#1512=EDGE_CURVE('E706',#1502,#1511,#1509,.T.);
#1513=ORIENTED_EDGE('',*,*,#1512,.T.);
#1514=CARTESIAN_POINT('',(0.,43.9666168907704,-54.2766902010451));
#1515=VERTEX_POINT('',#1514);
#1516=EDGE_CURVE('E1277',#1515,#1511,#55,.T.);
#1517=ORIENTED_EDGE('',*,*,#1516,.F.);
#1518=CARTESIAN_POINT('',(0.,65.9302980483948,-23.1446053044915));
#1519=DIRECTION('',(1.,0.,0.));
#1520=DIRECTION('',(0.,0.,-1.));
#1521=AXIS2_PLACEMENT_3D('',#1518,#1519,#1520);
#1522=CIRCLE('',#1521,38.1);
#1523=CARTESIAN_POINT('',(0.,58.4663566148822,-60.5063448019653));
#1524=VERTEX_POINT('',#1523);
#1525=EDGE_CURVE('E1262',#1524,#1515,#1522,.F.);
#1526=ORIENTED_EDGE('',*,*,#1525,.F.);
#1527=CARTESIAN_POINT('',(0.,0.,0.));
#1528=DIRECTION('',(1.,0.,0.));
#1529=DIRECTION('',(0.,-0.707106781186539,-0.707106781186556));
#1530=AXIS2_PLACEMENT_3D('',#1527,#1528,#1529);
#1531=CIRCLE('',#1530,84.13877);
#1532=CARTESIAN_POINT('',(0.,60.5063448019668,-58.4663566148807));
#1533=VERTEX_POINT('',#1532);
#1534=EDGE_CURVE('E678',#1524,#1533,#1531,.T.);
#1535=ORIENTED_EDGE('',*,*,#1534,.T.);
#1536=CARTESIAN_POINT('',(0.,23.1446053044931,-65.9302980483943));
#1537=DIRECTION('',(1.,0.,0.));
#1538=DIRECTION('',(0.,-0.707106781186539,-0.707106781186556));
#1539=AXIS2_PLACEMENT_3D('',#1536,#1537,#1538);
#1540=CIRCLE('',#1539,38.1);
#1541=CARTESIAN_POINT('',(0.,54.2766902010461,-43.9666168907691));
#1542=VERTEX_POINT('',#1541);
#1543=EDGE_CURVE('E682',#1533,#1542,#1540,.T.);
#1544=ORIENTED_EDGE('',*,*,#1543,.T.);
#1545=CARTESIAN_POINT('',(0.,56.5163318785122,-41.0478590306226));
#1546=VERTEX_POINT('',#1545);
#1547=EDGE_CURVE('E1274',#1546,#1542,#55,.T.);
#1548=ORIENTED_EDGE('',*,*,#1547,.F.);
#1549=CARTESIAN_POINT('',(0.,69.6740422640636,-5.29195521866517));
#1550=DIRECTION('',(1.,0.,0.));
#1551=DIRECTION('',(0.,0.,-1.));
#1552=AXIS2_PLACEMENT_3D('',#1549,#1550,#1551);
#1553=CIRCLE('',#1552,38.1);
#1554=CARTESIAN_POINT('',(0.,72.13435820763,-43.3124345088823));
#1555=VERTEX_POINT('',#1554);
#1556=EDGE_CURVE('E40',#1555,#1546,#1553,.F.);
#1557=ORIENTED_EDGE('',*,*,#1556,.F.);
#1558=CARTESIAN_POINT('',(0.,0.,0.));
#1559=DIRECTION('',(1.,0.,0.));
#1560=DIRECTION('',(0.,-0.499999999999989,-0.866025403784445));
#1561=AXIS2_PLACEMENT_3D('',#1558,#1559,#1560);
#1562=CIRCLE('',#1561,84.13877);
#1563=CARTESIAN_POINT('',(0.,73.5768476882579,-40.813969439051));
#1564=VERTEX_POINT('',#1563);
#1565=EDGE_CURVE('E55',#1555,#1564,#1562,.T.);
#1566=ORIENTED_EDGE('',*,*,#1565,.T.);
#1567=CARTESIAN_POINT('',(0.,39.4199887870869,-57.6935129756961));
#1568=DIRECTION('',(1.,0.,0.));
#1569=DIRECTION('',(0.,-0.499999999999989,-0.866025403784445));
#1570=AXIS2_PLACEMENT_3D('',#1567,#1568,#1569);
#1571=CIRCLE('',#1570,38.1);
#1572=EDGE_CURVE('E661',#1564,#72,#1571,.T.);
#1573=ORIENTED_EDGE('',*,*,#1572,.T.);
#1574=ORIENTED_EDGE('',*,*,#73,.F.);
#1575=CARTESIAN_POINT('',(0.,68.6696156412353,12.9213328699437));
#1576=DIRECTION('',(1.,0.,0.));
#1577=DIRECTION('',(0.,0.,-1.));
#1578=AXIS2_PLACEMENT_3D('',#1575,#1576,#1577);
#1579=CIRCLE('',#1578,38.1);
#1580=CARTESIAN_POINT('',(0.,80.886522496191,-23.1668533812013));
#1581=VERTEX_POINT('',#1580);
#1582=EDGE_CURVE('E11',#1581,#66,#1579,.F.);
#1583=ORIENTED_EDGE('',*,*,#1582,.F.);
#1584=CARTESIAN_POINT('',(0.,0.,0.));
#1585=DIRECTION('',(1.,0.,0.));
#1586=DIRECTION('',(0.,-0.258819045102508,-0.965925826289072));
#1587=AXIS2_PLACEMENT_3D('',#1584,#1585,#1586);
#1588=CIRCLE('',#1587,84.13877);
#1589=EDGE_CURVE('E47',#1581,#863,#1588,.T.);
#1590=ORIENTED_EDGE('',*,*,#1589,.T.);
#1591=EDGE_LOOP('',(#865,#866,#875,#884,#893,#897,#906,#915,#924,#928,#937,#946,#955,#959,#968,
#977,#986,#990,#999,#1008,#1017,#1021,#1030,#1039,#1048,#1052,#1061,#1070,#1079,#1083,#1092,
#1101,#1110,#1114,#1123,#1132,#1141,#1145,#1154,#1163,#1172,#1176,#1185,#1194,#1203,#1207,#1216,
#1225,#1234,#1238,#1247,#1256,#1265,#1269,#1278,#1287,#1296,#1300,#1309,#1318,#1327,#1331,#1340,
#1349,#1358,#1362,#1371,#1380,#1389,#1393,#1402,#1411,#1420,#1424,#1433,#1442,#1451,#1455,#1464,
#1473,#1482,#1486,#1495,#1504,#1513,#1517,#1526,#1535,#1544,#1548,#1557,#1566,#1573,#1574,#1583,#1590));
#1592=FACE_BOUND('',#1591,.T.);
#1593=ADVANCED_FACE('F1276',(#856,#1592),#845,.F.);
#1594=DIRECTION('',(-1.,0.,0.));
#1595=VECTOR('',#1594,1.);
#1596=CARTESIAN_POINT('',(6.,56.5163318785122,-41.0478590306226));
#1597=LINE('',#1596,#1595);
#1598=EDGE_CURVE('E673',#1546,#154,#1597,.F.);
#1599=ORIENTED_EDGE('',*,*,#1598,.F.);
#1600=ORIENTED_EDGE('',*,*,#1547,.T.);
#1601=DIRECTION('',(-1.,0.,0.));
#1602=VECTOR('',#1601,1.);
#1603=CARTESIAN_POINT('',(6.,54.2766902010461,-43.9666168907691));
#1604=LINE('',#1603,#1602);
#1605=EDGE_CURVE('E699',#158,#1542,#1604,.T.);
#1606=ORIENTED_EDGE('',*,*,#1605,.F.);
#1607=ORIENTED_EDGE('',*,*,#159,.F.);
#1608=EDGE_LOOP('',(#1599,#1600,#1606,#1607));
#1609=FACE_BOUND('',#1608,.T.);
#1610=ADVANCED_FACE('F1272',(#1609),#23,.F.);
#1611=DIRECTION('',(-1.,0.,0.));
#1612=VECTOR('',#1611,1.);
#1613=CARTESIAN_POINT('',(6.,43.9666168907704,-54.2766902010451));
#1614=LINE('',#1613,#1612);
#1615=EDGE_CURVE('E697',#1515,#185,#1614,.F.);
#1616=ORIENTED_EDGE('',*,*,#1615,.F.);
#1617=ORIENTED_EDGE('',*,*,#1516,.T.);
#1618=DIRECTION('',(-1.,0.,0.));
#1619=VECTOR('',#1618,1.);
#1620=CARTESIAN_POINT('',(6.,41.047859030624,-56.5163318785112));
#1621=LINE('',#1620,#1619);
#1622=EDGE_CURVE('E723',#189,#1511,#1621,.T.);
#1623=ORIENTED_EDGE('',*,*,#1622,.F.);
#1624=ORIENTED_EDGE('',*,*,#190,.F.);
#1625=EDGE_LOOP('',(#1616,#1617,#1623,#1624));
#1626=FACE_BOUND('',#1625,.T.);
#1627=ADVANCED_FACE('F1551',(#1626),#23,.F.);
#1628=DIRECTION('',(-1.,0.,0.));
#1629=VECTOR('',#1628,1.);
#1630=CARTESIAN_POINT('',(6.,28.4206496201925,-63.8066546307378));
#1631=LINE('',#1630,#1629);
#1632=EDGE_CURVE('E721',#1484,#216,#1631,.F.);
#1633=ORIENTED_EDGE('',*,*,#1632,.F.);
#1634=ORIENTED_EDGE('',*,*,#1485,.T.);
#1635=DIRECTION('',(-1.,0.,0.));
#1636=VECTOR('',#1635,1.);
#1637=CARTESIAN_POINT('',(6.,25.0216841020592,-65.2145522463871));
#1638=LINE('',#1637,#1636);
#1639=EDGE_CURVE('E747',#220,#1480,#1638,.T.);
#1640=ORIENTED_EDGE('',*,*,#1639,.F.);
#1641=ORIENTED_EDGE('',*,*,#221,.F.);
#1642=EDGE_LOOP('',(#1633,#1634,#1640,#1641));
#1643=FACE_BOUND('',#1642,.T.);
#1644=ADVANCED_FACE('F1555',(#1643),#23,.F.);
#1645=DIRECTION('',(-1.,0.,0.));
#1646=VECTOR('',#1645,1.);
#1647=CARTESIAN_POINT('',(6.,10.9378620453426,-68.9883009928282));
#1648=LINE('',#1647,#1646);
#1649=EDGE_CURVE('E745',#1453,#247,#1648,.F.);
#1650=ORIENTED_EDGE('',*,*,#1649,.F.);
#1651=ORIENTED_EDGE('',*,*,#1454,.T.);
#1652=DIRECTION('',(-1.,0.,0.));
#1653=VECTOR('',#1652,1.);
#1654=CARTESIAN_POINT('',(6.,7.2903227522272,-69.468508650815));
#1655=LINE('',#1654,#1653);
#1656=EDGE_CURVE('E771',#251,#1449,#1655,.T.);
#1657=ORIENTED_EDGE('',*,*,#1656,.F.);
#1658=ORIENTED_EDGE('',*,*,#252,.F.);
#1659=EDGE_LOOP('',(#1650,#1651,#1657,#1658));
#1660=FACE_BOUND('',#1659,.T.);
#1661=ADVANCED_FACE('F1559',(#1660),#23,.F.);
#1662=DIRECTION('',(-1.,0.,0.));
#1663=VECTOR('',#1662,1.);
#1664=CARTESIAN_POINT('',(6.,-7.29032275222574,-69.4685086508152));
#1665=LINE('',#1664,#1663);
#1666=EDGE_CURVE('E769',#1422,#278,#1665,.F.);
#1667=ORIENTED_EDGE('',*,*,#1666,.F.);
#1668=ORIENTED_EDGE('',*,*,#1423,.T.);
#1669=DIRECTION('',(-1.,0.,0.));
#1670=VECTOR('',#1669,1.);
#1671=CARTESIAN_POINT('',(6.,-10.9378620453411,-68.9883009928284));
#1672=LINE('',#1671,#1670);
#1673=EDGE_CURVE('E795',#282,#1418,#1672,.T.);
#1674=ORIENTED_EDGE('',*,*,#1673,.F.);
#1675=ORIENTED_EDGE('',*,*,#283,.F.);
#1676=EDGE_LOOP('',(#1667,#1668,#1674,#1675));
#1677=FACE_BOUND('',#1676,.T.);
#1678=ADVANCED_FACE('F1591',(#1677),#23,.F.);
#1679=DIRECTION('',(-1.,0.,0.));
#1680=VECTOR('',#1679,1.);
#1681=CARTESIAN_POINT('',(6.,-25.0216841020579,-65.2145522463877));
#1682=LINE('',#1681,#1680);
#1683=EDGE_CURVE('E793',#1391,#309,#1682,.F.);
#1684=ORIENTED_EDGE('',*,*,#1683,.F.);
#1685=ORIENTED_EDGE('',*,*,#1392,.T.);
#1686=DIRECTION('',(-1.,0.,0.));
#1687=VECTOR('',#1686,1.);
#1688=CARTESIAN_POINT('',(6.,-28.4206496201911,-63.8066546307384));
#1689=LINE('',#1688,#1687);
#1690=EDGE_CURVE('E819',#313,#1387,#1689,.T.);
#1691=ORIENTED_EDGE('',*,*,#1690,.F.);
#1692=ORIENTED_EDGE('',*,*,#314,.F.);
#1693=EDGE_LOOP('',(#1684,#1685,#1691,#1692));
#1694=FACE_BOUND('',#1693,.T.);
#1695=ADVANCED_FACE('F1602',(#1694),#23,.F.);
#1696=DIRECTION('',(-1.,0.,0.));
#1697=VECTOR('',#1696,1.);
#1698=CARTESIAN_POINT('',(6.,-41.0478590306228,-56.516331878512));
#1699=LINE('',#1698,#1697);
#1700=EDGE_CURVE('E817',#1360,#340,#1699,.F.);
#1701=ORIENTED_EDGE('',*,*,#1700,.F.);
#1702=ORIENTED_EDGE('',*,*,#1361,.T.);
#1703=DIRECTION('',(-1.,0.,0.));
#1704=VECTOR('',#1703,1.);
#1705=CARTESIAN_POINT('',(6.,-43.9666168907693,-54.276690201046));
#1706=LINE('',#1705,#1704);
#1707=EDGE_CURVE('E843',#344,#1356,#1706,.T.);
#1708=ORIENTED_EDGE('',*,*,#1707,.F.);
#1709=ORIENTED_EDGE('',*,*,#345,.F.);
#1710=EDGE_LOOP('',(#1701,#1702,#1708,#1709));
#1711=FACE_BOUND('',#1710,.T.);
#1712=ADVANCED_FACE('F1613',(#1711),#23,.F.);
#1713=DIRECTION('',(-1.,0.,0.));
#1714=VECTOR('',#1713,1.);
#1715=CARTESIAN_POINT('',(6.,-54.2766902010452,-43.9666168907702));
#1716=LINE('',#1715,#1714);
#1717=EDGE_CURVE('E841',#1329,#371,#1716,.F.);
#1718=ORIENTED_EDGE('',*,*,#1717,.F.);
#1719=ORIENTED_EDGE('',*,*,#1330,.T.);
#1720=DIRECTION('',(-1.,0.,0.));
#1721=VECTOR('',#1720,1.);
#1722=CARTESIAN_POINT('',(6.,-56.5163318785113,-41.0478590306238));
#1723=LINE('',#1722,#1721);
#1724=EDGE_CURVE('E867',#375,#1325,#1723,.T.);
#1725=ORIENTED_EDGE('',*,*,#1724,.F.);
#1726=ORIENTED_EDGE('',*,*,#376,.F.);
#1727=EDGE_LOOP('',(#1718,#1719,#1725,#1726));
#1728=FACE_BOUND('',#1727,.T.);
#1729=ADVANCED_FACE('F1624',(#1728),#23,.F.);
#1730=DIRECTION('',(-1.,0.,0.));
#1731=VECTOR('',#1730,1.);
#1732=CARTESIAN_POINT('',(6.,-63.8066546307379,-28.4206496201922));
#1733=LINE('',#1732,#1731);
#1734=EDGE_CURVE('E865',#1298,#402,#1733,.F.);
#1735=ORIENTED_EDGE('',*,*,#1734,.F.);
#1736=ORIENTED_EDGE('',*,*,#1299,.T.);
#1737=DIRECTION('',(-1.,0.,0.));
#1738=VECTOR('',#1737,1.);
#1739=CARTESIAN_POINT('',(6.,-65.2145522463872,-25.021684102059));
#1740=LINE('',#1739,#1738);
#1741=EDGE_CURVE('E891',#406,#1294,#1740,.T.);
#1742=ORIENTED_EDGE('',*,*,#1741,.F.);
#1743=ORIENTED_EDGE('',*,*,#407,.F.);
#1744=EDGE_LOOP('',(#1735,#1736,#1742,#1743));
#1745=FACE_BOUND('',#1744,.T.);
#1746=ADVANCED_FACE('F1635',(#1745),#23,.F.);
#1747=DIRECTION('',(-1.,0.,0.));
#1748=VECTOR('',#1747,1.);
#1749=CARTESIAN_POINT('',(6.,-68.9883009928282,-10.9378620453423));
#1750=LINE('',#1749,#1748);
#1751=EDGE_CURVE('E889',#1267,#433,#1750,.F.);
#1752=ORIENTED_EDGE('',*,*,#1751,.F.);
#1753=ORIENTED_EDGE('',*,*,#1268,.T.);
#1754=DIRECTION('',(-1.,0.,0.));
#1755=VECTOR('',#1754,1.);
#1756=CARTESIAN_POINT('',(6.,-69.468508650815,-7.29032275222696));
#1757=LINE('',#1756,#1755);
#1758=EDGE_CURVE('E915',#437,#1263,#1757,.T.);
#1759=ORIENTED_EDGE('',*,*,#1758,.F.);
#1760=ORIENTED_EDGE('',*,*,#438,.F.);
#1761=EDGE_LOOP('',(#1752,#1753,#1759,#1760));
#1762=FACE_BOUND('',#1761,.T.);
#1763=ADVANCED_FACE('F1646',(#1762),#23,.F.);
#1764=DIRECTION('',(-1.,0.,0.));
#1765=VECTOR('',#1764,1.);
#1766=CARTESIAN_POINT('',(6.,-69.4685086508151,7.29032275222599));
#1767=LINE('',#1766,#1765);
#1768=EDGE_CURVE('E913',#1236,#464,#1767,.F.);
#1769=ORIENTED_EDGE('',*,*,#1768,.F.);
#1770=ORIENTED_EDGE('',*,*,#1237,.T.);
#1771=DIRECTION('',(-1.,0.,0.));
#1772=VECTOR('',#1771,1.);
#1773=CARTESIAN_POINT('',(6.,-68.9883009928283,10.9378620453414));
#1774=LINE('',#1773,#1772);
#1775=EDGE_CURVE('E939',#468,#1232,#1774,.T.);
#1776=ORIENTED_EDGE('',*,*,#1775,.F.);
#1777=ORIENTED_EDGE('',*,*,#469,.F.);
#1778=EDGE_LOOP('',(#1769,#1770,#1776,#1777));
#1779=FACE_BOUND('',#1778,.T.);
#1780=ADVANCED_FACE('F1657',(#1779),#23,.F.);
#1781=DIRECTION('',(-1.,0.,0.));
#1782=VECTOR('',#1781,1.);
#1783=CARTESIAN_POINT('',(6.,-65.2145522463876,25.0216841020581));
#1784=LINE('',#1783,#1782);
#1785=EDGE_CURVE('E937',#1205,#495,#1784,.F.);
#1786=ORIENTED_EDGE('',*,*,#1785,.F.);
#1787=ORIENTED_EDGE('',*,*,#1206,.T.);
#1788=DIRECTION('',(-1.,0.,0.));
#1789=VECTOR('',#1788,1.);
#1790=CARTESIAN_POINT('',(6.,-63.8066546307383,28.4206496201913));
#1791=LINE('',#1790,#1789);
#1792=EDGE_CURVE('E963',#499,#1201,#1791,.T.);
#1793=ORIENTED_EDGE('',*,*,#1792,.F.);
#1794=ORIENTED_EDGE('',*,*,#500,.F.);
#1795=EDGE_LOOP('',(#1786,#1787,#1793,#1794));
#1796=FACE_BOUND('',#1795,.T.);
#1797=ADVANCED_FACE('F1668',(#1796),#23,.F.);
#1798=DIRECTION('',(-1.,0.,0.));
#1799=VECTOR('',#1798,1.);
#1800=CARTESIAN_POINT('',(6.,-56.5163318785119,41.047859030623));
#1801=LINE('',#1800,#1799);
#1802=EDGE_CURVE('E961',#1174,#526,#1801,.F.);
#1803=ORIENTED_EDGE('',*,*,#1802,.F.);
#1804=ORIENTED_EDGE('',*,*,#1175,.T.);
#1805=DIRECTION('',(-1.,0.,0.));
#1806=VECTOR('',#1805,1.);
#1807=CARTESIAN_POINT('',(6.,-54.2766902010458,43.9666168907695));
#1808=LINE('',#1807,#1806);
#1809=EDGE_CURVE('E987',#530,#1170,#1808,.T.);
#1810=ORIENTED_EDGE('',*,*,#1809,.F.);
#1811=ORIENTED_EDGE('',*,*,#531,.F.);
#1812=EDGE_LOOP('',(#1803,#1804,#1810,#1811));
#1813=FACE_BOUND('',#1812,.T.);
#1814=ADVANCED_FACE('F1679',(#1813),#23,.F.);
#1815=DIRECTION('',(-1.,0.,0.));
#1816=VECTOR('',#1815,1.);
#1817=CARTESIAN_POINT('',(6.,-43.9666168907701,54.2766902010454));
#1818=LINE('',#1817,#1816);
#1819=EDGE_CURVE('E985',#1143,#557,#1818,.F.);
#1820=ORIENTED_EDGE('',*,*,#1819,.F.);
#1821=ORIENTED_EDGE('',*,*,#1144,.T.);
#1822=DIRECTION('',(-1.,0.,0.));
#1823=VECTOR('',#1822,1.);
#1824=CARTESIAN_POINT('',(6.,-41.0478590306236,56.5163318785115));
#1825=LINE('',#1824,#1823);
#1826=EDGE_CURVE('E1011',#561,#1139,#1825,.T.);
#1827=ORIENTED_EDGE('',*,*,#1826,.F.);
#1828=ORIENTED_EDGE('',*,*,#562,.F.);
#1829=EDGE_LOOP('',(#1820,#1821,#1827,#1828));
#1830=FACE_BOUND('',#1829,.T.);
#1831=ADVANCED_FACE('F1690',(#1830),#23,.F.);
#1832=DIRECTION('',(-1.,0.,0.));
#1833=VECTOR('',#1832,1.);
#1834=CARTESIAN_POINT('',(6.,-28.420649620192,63.806654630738));
#1835=LINE('',#1834,#1833);
#1836=EDGE_CURVE('E1009',#1112,#588,#1835,.F.);
#1837=ORIENTED_EDGE('',*,*,#1836,.F.);
#1838=ORIENTED_EDGE('',*,*,#1113,.T.);
#1839=DIRECTION('',(-1.,0.,0.));
#1840=VECTOR('',#1839,1.);
#1841=CARTESIAN_POINT('',(6.,-25.0216841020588,65.2145522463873));
#1842=LINE('',#1841,#1840);
#1843=EDGE_CURVE('E1035',#592,#1108,#1842,.T.);
#1844=ORIENTED_EDGE('',*,*,#1843,.F.);
#1845=ORIENTED_EDGE('',*,*,#593,.F.);
#1846=EDGE_LOOP('',(#1837,#1838,#1844,#1845));
#1847=FACE_BOUND('',#1846,.T.);
#1848=ADVANCED_FACE('F1701',(#1847),#23,.F.);
#1849=DIRECTION('',(-1.,0.,0.));
#1850=VECTOR('',#1849,1.);
#1851=CARTESIAN_POINT('',(6.,-10.9378620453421,68.9883009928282));
#1852=LINE('',#1851,#1850);
#1853=EDGE_CURVE('E1033',#1081,#619,#1852,.F.);
#1854=ORIENTED_EDGE('',*,*,#1853,.F.);
#1855=ORIENTED_EDGE('',*,*,#1082,.T.);
#1856=DIRECTION('',(-1.,0.,0.));
#1857=VECTOR('',#1856,1.);
#1858=CARTESIAN_POINT('',(6.,-7.29032275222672,69.4685086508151));
#1859=LINE('',#1858,#1857);
#1860=EDGE_CURVE('E1059',#623,#1077,#1859,.T.);
#1861=ORIENTED_EDGE('',*,*,#1860,.F.);
#1862=ORIENTED_EDGE('',*,*,#624,.F.);
#1863=EDGE_LOOP('',(#1854,#1855,#1861,#1862));
#1864=FACE_BOUND('',#1863,.T.);
#1865=ADVANCED_FACE('F1712',(#1864),#23,.F.);
#1866=DIRECTION('',(-1.,0.,0.));
#1867=VECTOR('',#1866,1.);
#1868=CARTESIAN_POINT('',(6.,7.29032275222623,69.4685086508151));
#1869=LINE('',#1868,#1867);
#1870=EDGE_CURVE('E1057',#1050,#650,#1869,.F.);
#1871=ORIENTED_EDGE('',*,*,#1870,.F.);
#1872=ORIENTED_EDGE('',*,*,#1051,.T.);
#1873=DIRECTION('',(-1.,0.,0.));
#1874=VECTOR('',#1873,1.);
#1875=CARTESIAN_POINT('',(6.,10.9378620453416,68.9883009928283));
#1876=LINE('',#1875,#1874);
#1877=EDGE_CURVE('E1083',#654,#1046,#1876,.T.);
#1878=ORIENTED_EDGE('',*,*,#1877,.F.);
#1879=ORIENTED_EDGE('',*,*,#655,.F.);
#1880=EDGE_LOOP('',(#1871,#1872,#1878,#1879));
#1881=FACE_BOUND('',#1880,.T.);
#1882=ADVANCED_FACE('F1723',(#1881),#23,.F.);
#1883=DIRECTION('',(-1.,0.,0.));
#1884=VECTOR('',#1883,1.);
#1885=CARTESIAN_POINT('',(6.,25.0216841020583,65.2145522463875));
#1886=LINE('',#1885,#1884);
#1887=EDGE_CURVE('E1081',#1019,#681,#1886,.F.);
#1888=ORIENTED_EDGE('',*,*,#1887,.F.);
#1889=ORIENTED_EDGE('',*,*,#1020,.T.);
#1890=DIRECTION('',(-1.,0.,0.));
#1891=VECTOR('',#1890,1.);
#1892=CARTESIAN_POINT('',(6.,28.4206496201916,63.8066546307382));
#1893=LINE('',#1892,#1891);
#1894=EDGE_CURVE('E1107',#685,#1015,#1893,.T.);
#1895=ORIENTED_EDGE('',*,*,#1894,.F.);
#1896=ORIENTED_EDGE('',*,*,#686,.F.);
#1897=EDGE_LOOP('',(#1888,#1889,#1895,#1896));
#1898=FACE_BOUND('',#1897,.T.);
#1899=ADVANCED_FACE('F1521',(#1898),#23,.F.);
#1900=DIRECTION('',(-1.,0.,0.));
#1901=VECTOR('',#1900,1.);
#1902=CARTESIAN_POINT('',(6.,41.0478590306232,56.5163318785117));
#1903=LINE('',#1902,#1901);
#1904=EDGE_CURVE('E1105',#988,#712,#1903,.F.);
#1905=ORIENTED_EDGE('',*,*,#1904,.F.);
#1906=ORIENTED_EDGE('',*,*,#989,.T.);
#1907=DIRECTION('',(-1.,0.,0.));
#1908=VECTOR('',#1907,1.);
#1909=CARTESIAN_POINT('',(6.,43.9666168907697,54.2766902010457));
#1910=LINE('',#1909,#1908);
#1911=EDGE_CURVE('E1131',#716,#984,#1910,.T.);
#1912=ORIENTED_EDGE('',*,*,#1911,.F.);
#1913=ORIENTED_EDGE('',*,*,#717,.F.);
#1914=EDGE_LOOP('',(#1905,#1906,#1912,#1913));
#1915=FACE_BOUND('',#1914,.T.);
#1916=ADVANCED_FACE('F1516',(#1915),#23,.F.);
#1917=DIRECTION('',(-1.,0.,0.));
#1918=VECTOR('',#1917,1.);
#1919=CARTESIAN_POINT('',(6.,54.2766902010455,43.9666168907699));
#1920=LINE('',#1919,#1918);
#1921=EDGE_CURVE('E1129',#957,#743,#1920,.F.);
#1922=ORIENTED_EDGE('',*,*,#1921,.F.);
#1923=ORIENTED_EDGE('',*,*,#958,.T.);
#1924=DIRECTION('',(-1.,0.,0.));
#1925=VECTOR('',#1924,1.);
#1926=CARTESIAN_POINT('',(6.,56.5163318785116,41.0478590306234));
#1927=LINE('',#1926,#1925);
#1928=EDGE_CURVE('E1155',#747,#953,#1927,.T.);
#1929=ORIENTED_EDGE('',*,*,#1928,.F.);
#1930=ORIENTED_EDGE('',*,*,#748,.F.);
#1931=EDGE_LOOP('',(#1922,#1923,#1929,#1930));
#1932=FACE_BOUND('',#1931,.T.);
#1933=ADVANCED_FACE('F1514',(#1932),#23,.F.);
#1934=DIRECTION('',(-1.,0.,0.));
#1935=VECTOR('',#1934,1.);
#1936=CARTESIAN_POINT('',(6.,63.8066546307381,28.4206496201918));
#1937=LINE('',#1936,#1935);
#1938=EDGE_CURVE('E1153',#926,#774,#1937,.F.);
#1939=ORIENTED_EDGE('',*,*,#1938,.F.);
#1940=ORIENTED_EDGE('',*,*,#927,.T.);
#1941=DIRECTION('',(-1.,0.,0.));
#1942=VECTOR('',#1941,1.);
#1943=CARTESIAN_POINT('',(6.,65.2145522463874,25.0216841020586));
#1944=LINE('',#1943,#1942);
#1945=EDGE_CURVE('E1179',#778,#922,#1944,.T.);
#1946=ORIENTED_EDGE('',*,*,#1945,.F.);
#1947=ORIENTED_EDGE('',*,*,#779,.F.);
#1948=EDGE_LOOP('',(#1939,#1940,#1946,#1947));
#1949=FACE_BOUND('',#1948,.T.);
#1950=ADVANCED_FACE('F1500',(#1949),#23,.F.);
#1951=DIRECTION('',(-1.,0.,0.));
#1952=VECTOR('',#1951,1.);
#1953=CARTESIAN_POINT('',(6.,68.9883009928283,10.9378620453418));
#1954=LINE('',#1953,#1952);
#1955=EDGE_CURVE('E1177',#895,#805,#1954,.F.);
#1956=ORIENTED_EDGE('',*,*,#1955,.F.);
#1957=ORIENTED_EDGE('',*,*,#896,.T.);
#1958=DIRECTION('',(-1.,0.,0.));
#1959=VECTOR('',#1958,1.);
#1960=CARTESIAN_POINT('',(6.,69.4685086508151,7.29032275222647));
#1961=LINE('',#1960,#1959);
#1962=EDGE_CURVE('E1203',#809,#891,#1961,.T.);
#1963=ORIENTED_EDGE('',*,*,#1962,.F.);
#1964=ORIENTED_EDGE('',*,*,#810,.F.);
#1965=EDGE_LOOP('',(#1956,#1957,#1963,#1964));
#1966=FACE_BOUND('',#1965,.T.);
#1967=ADVANCED_FACE('F1381',(#1966),#23,.F.);
#1968=CARTESIAN_POINT('',(-10.,0.,0.));
#1969=DIRECTION('',(-1.,0.,0.));
#1970=DIRECTION('',(0.,0.,1.));
#1971=AXIS2_PLACEMENT_3D('',#1968,#1969,#1970);
#1972=CYLINDRICAL_SURFACE('',#1971,101.6);
#1973=ORIENTED_EDGE('',*,*,#853,.F.);
#1974=EDGE_LOOP('',(#1973));
#1975=FACE_BOUND('',#1974,.T.);
#1976=ORIENTED_EDGE('',*,*,#100,.T.);
#1977=EDGE_LOOP('',(#1976));
#1978=FACE_BOUND('',#1977,.T.);
#1979=ADVANCED_FACE('F1527',(#1975,#1978),#1972,.T.);
#1980=CARTESIAN_POINT('',(12.,62.9854681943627,-30.2540534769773));
#1981=DIRECTION('',(-1.,0.,0.));
#1982=DIRECTION('',(0.,0.,1.));
#1983=AXIS2_PLACEMENT_3D('',#1980,#1981,#1982);
#1984=CYLINDRICAL_SURFACE('',#1983,38.1);
#1985=ORIENTED_EDGE('',*,*,#1962,.T.);
#1986=ORIENTED_EDGE('',*,*,#892,.F.);
#1987=DIRECTION('',(-1.,0.,0.));
#1988=VECTOR('',#1987,1.);
#1989=CARTESIAN_POINT('',(12.,84.1264039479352,1.44248948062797));
#1990=LINE('',#1989,#1988);
#1991=EDGE_CURVE('E1198',#818,#882,#1990,.T.);
#1992=ORIENTED_EDGE('',*,*,#1991,.F.);
#1993=ORIENTED_EDGE('',*,*,#819,.T.);
#1994=EDGE_LOOP('',(#1985,#1986,#1992,#1993));
#1995=FACE_BOUND('',#1994,.T.);
#1996=ADVANCED_FACE('F1385',(#1995),#1984,.F.);
#1997=CARTESIAN_POINT('',(12.,62.9854681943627,30.2540534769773));
#1998=DIRECTION('',(-1.,0.,0.));
#1999=DIRECTION('',(0.,0.,1.));
#2000=AXIS2_PLACEMENT_3D('',#1997,#1998,#1999);
#2001=CYLINDRICAL_SURFACE('',#2000,38.1);
#2002=ORIENTED_EDGE('',*,*,#49,.T.);
#2003=ORIENTED_EDGE('',*,*,#835,.T.);
#2004=DIRECTION('',(-1.,0.,0.));
#2005=VECTOR('',#2004,1.);
#2006=CARTESIAN_POINT('',(12.,84.1264039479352,-1.44248948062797));
#2007=LINE('',#2006,#2005);
#2008=EDGE_CURVE('E1191',#827,#873,#2007,.T.);
#2009=ORIENTED_EDGE('',*,*,#2008,.T.);
#2010=ORIENTED_EDGE('',*,*,#874,.T.);
#2011=EDGE_LOOP('',(#2002,#2003,#2009,#2010));
#2012=FACE_BOUND('',#2011,.T.);
#2013=ADVANCED_FACE('F1395',(#2012),#2001,.F.);
#2014=CARTESIAN_POINT('',(12.,0.,0.));
#2015=DIRECTION('',(-1.,0.,0.));
#2016=DIRECTION('',(0.,0.,1.));
#2017=AXIS2_PLACEMENT_3D('',#2014,#2015,#2016);
#2018=CYLINDRICAL_SURFACE('',#2017,84.13877);
#2019=ORIENTED_EDGE('',*,*,#883,.F.);
#2020=ORIENTED_EDGE('',*,*,#2008,.F.);
#2021=ORIENTED_EDGE('',*,*,#828,.T.);
#2022=ORIENTED_EDGE('',*,*,#1991,.T.);
#2023=EDGE_LOOP('',(#2019,#2020,#2021,#2022));
#2024=FACE_BOUND('',#2023,.T.);
#2025=ADVANCED_FACE('F1392',(#2024),#2018,.F.);
#2026=CARTESIAN_POINT('',(12.,68.6696156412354,-12.9213328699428));
#2027=DIRECTION('',(-1.,0.,0.));
#2028=DIRECTION('',(0.,0.,1.));
#2029=AXIS2_PLACEMENT_3D('',#2026,#2027,#2028);
#2030=CYLINDRICAL_SURFACE('',#2029,38.1);
#2031=ORIENTED_EDGE('',*,*,#1945,.T.);
#2032=ORIENTED_EDGE('',*,*,#923,.F.);
#2033=DIRECTION('',(-1.,0.,0.));
#2034=VECTOR('',#2033,1.);
#2035=CARTESIAN_POINT('',(12.,80.8865224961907,23.1668533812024));
#2036=LINE('',#2035,#2034);
#2037=EDGE_CURVE('E1174',#787,#913,#2036,.T.);
#2038=ORIENTED_EDGE('',*,*,#2037,.F.);
#2039=ORIENTED_EDGE('',*,*,#788,.T.);
#2040=EDGE_LOOP('',(#2031,#2032,#2038,#2039));
#2041=FACE_BOUND('',#2040,.T.);
#2042=ADVANCED_FACE('F1499',(#2041),#2030,.F.);
#2043=CARTESIAN_POINT('',(12.,53.0089651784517,45.5250103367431));
#2044=DIRECTION('',(-1.,0.,0.));
#2045=DIRECTION('',(0.,0.,1.));
#2046=AXIS2_PLACEMENT_3D('',#2043,#2044,#2045);
#2047=CYLINDRICAL_SURFACE('',#2046,38.1);
#2048=ORIENTED_EDGE('',*,*,#1955,.T.);
#2049=ORIENTED_EDGE('',*,*,#806,.T.);
#2050=DIRECTION('',(-1.,0.,0.));
#2051=VECTOR('',#2050,1.);
#2052=CARTESIAN_POINT('',(12.,81.6332099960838,20.3801776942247));
#2053=LINE('',#2052,#2051);
#2054=EDGE_CURVE('E1167',#796,#904,#2053,.T.);
#2055=ORIENTED_EDGE('',*,*,#2054,.T.);
#2056=ORIENTED_EDGE('',*,*,#905,.T.);
#2057=EDGE_LOOP('',(#2048,#2049,#2055,#2056));
#2058=FACE_BOUND('',#2057,.T.);
#2059=ADVANCED_FACE('F1493',(#2058),#2047,.F.);
#2060=CARTESIAN_POINT('',(12.,0.,0.));
#2061=DIRECTION('',(-1.,0.,0.));
#2062=DIRECTION('',(0.,0.,1.));
#2063=AXIS2_PLACEMENT_3D('',#2060,#2061,#2062);
#2064=CYLINDRICAL_SURFACE('',#2063,84.13877);
#2065=ORIENTED_EDGE('',*,*,#914,.F.);
#2066=ORIENTED_EDGE('',*,*,#2054,.F.);
#2067=ORIENTED_EDGE('',*,*,#797,.T.);
#2068=ORIENTED_EDGE('',*,*,#2037,.T.);
#2069=EDGE_LOOP('',(#2065,#2066,#2067,#2068));
#2070=FACE_BOUND('',#2069,.T.);
#2071=ADVANCED_FACE('F1495',(#2070),#2064,.F.);
#2072=CARTESIAN_POINT('',(12.,69.6740422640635,5.29195521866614));
#2073=DIRECTION('',(-1.,0.,0.));
#2074=DIRECTION('',(0.,0.,1.));
#2075=AXIS2_PLACEMENT_3D('',#2072,#2073,#2074);
#2076=CYLINDRICAL_SURFACE('',#2075,38.1);
#2077=ORIENTED_EDGE('',*,*,#1928,.T.);
#2078=ORIENTED_EDGE('',*,*,#954,.F.);
#2079=DIRECTION('',(-1.,0.,0.));
#2080=VECTOR('',#2079,1.);
#2081=CARTESIAN_POINT('',(12.,72.1343582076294,43.3124345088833));
#2082=LINE('',#2081,#2080);
#2083=EDGE_CURVE('E1150',#756,#944,#2082,.T.);
#2084=ORIENTED_EDGE('',*,*,#2083,.F.);
#2085=ORIENTED_EDGE('',*,*,#757,.T.);
#2086=EDGE_LOOP('',(#2077,#2078,#2084,#2085));
#2087=FACE_BOUND('',#2086,.T.);
#2088=ADVANCED_FACE('F1509',(#2087),#2076,.F.);
#2089=CARTESIAN_POINT('',(12.,39.4199887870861,57.6935129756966));
#2090=DIRECTION('',(-1.,0.,0.));
#2091=DIRECTION('',(0.,0.,1.));
#2092=AXIS2_PLACEMENT_3D('',#2089,#2090,#2091);
#2093=CYLINDRICAL_SURFACE('',#2092,38.1);
#2094=ORIENTED_EDGE('',*,*,#1938,.T.);
#2095=ORIENTED_EDGE('',*,*,#775,.T.);
#2096=DIRECTION('',(-1.,0.,0.));
#2097=VECTOR('',#2096,1.);
#2098=CARTESIAN_POINT('',(12.,73.5768476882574,40.8139694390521));
#2099=LINE('',#2098,#2097);
#2100=EDGE_CURVE('E1143',#765,#935,#2099,.T.);
#2101=ORIENTED_EDGE('',*,*,#2100,.T.);
#2102=ORIENTED_EDGE('',*,*,#936,.T.);
#2103=EDGE_LOOP('',(#2094,#2095,#2101,#2102));
#2104=FACE_BOUND('',#2103,.T.);
#2105=ADVANCED_FACE('F1502',(#2104),#2093,.F.);
#2106=CARTESIAN_POINT('',(12.,0.,0.));
#2107=DIRECTION('',(-1.,0.,0.));
#2108=DIRECTION('',(0.,0.,1.));
#2109=AXIS2_PLACEMENT_3D('',#2106,#2107,#2108);
#2110=CYLINDRICAL_SURFACE('',#2109,84.13877);
#2111=ORIENTED_EDGE('',*,*,#945,.F.);
#2112=ORIENTED_EDGE('',*,*,#2100,.F.);
#2113=ORIENTED_EDGE('',*,*,#766,.T.);
#2114=ORIENTED_EDGE('',*,*,#2083,.T.);
#2115=EDGE_LOOP('',(#2111,#2112,#2113,#2114));
#2116=FACE_BOUND('',#2115,.T.);
#2117=ADVANCED_FACE('F1507',(#2116),#2110,.F.);
#2118=CARTESIAN_POINT('',(12.,65.9302980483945,23.1446053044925));
#2119=DIRECTION('',(-1.,0.,0.));
#2120=DIRECTION('',(0.,0.,1.));
#2121=AXIS2_PLACEMENT_3D('',#2118,#2119,#2120);
#2122=CYLINDRICAL_SURFACE('',#2121,38.1);
#2123=ORIENTED_EDGE('',*,*,#1911,.T.);
#2124=ORIENTED_EDGE('',*,*,#985,.F.);
#2125=DIRECTION('',(-1.,0.,0.));
#2126=VECTOR('',#2125,1.);
#2127=CARTESIAN_POINT('',(12.,58.4663566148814,60.5063448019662));
#2128=LINE('',#2127,#2126);
#2129=EDGE_CURVE('E1126',#725,#975,#2128,.T.);
#2130=ORIENTED_EDGE('',*,*,#2129,.F.);
#2131=ORIENTED_EDGE('',*,*,#726,.T.);
#2132=EDGE_LOOP('',(#2123,#2124,#2130,#2131));
#2133=FACE_BOUND('',#2132,.T.);
#2134=ADVANCED_FACE('F1745',(#2133),#2122,.F.);
#2135=CARTESIAN_POINT('',(12.,23.1446053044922,65.9302980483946));
#2136=DIRECTION('',(-1.,0.,0.));
#2137=DIRECTION('',(0.,0.,1.));
#2138=AXIS2_PLACEMENT_3D('',#2135,#2136,#2137);
#2139=CYLINDRICAL_SURFACE('',#2138,38.1);
#2140=ORIENTED_EDGE('',*,*,#1921,.T.);
#2141=ORIENTED_EDGE('',*,*,#744,.T.);
#2142=DIRECTION('',(-1.,0.,0.));
#2143=VECTOR('',#2142,1.);
#2144=CARTESIAN_POINT('',(12.,60.506344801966,58.4663566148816));
#2145=LINE('',#2144,#2143);
#2146=EDGE_CURVE('E1119',#734,#966,#2145,.T.);
#2147=ORIENTED_EDGE('',*,*,#2146,.T.);
#2148=ORIENTED_EDGE('',*,*,#967,.T.);
#2149=EDGE_LOOP('',(#2140,#2141,#2147,#2148));
#2150=FACE_BOUND('',#2149,.T.);
#2151=ADVANCED_FACE('F1512',(#2150),#2139,.F.);
#2152=CARTESIAN_POINT('',(12.,0.,0.));
#2153=DIRECTION('',(-1.,0.,0.));
#2154=DIRECTION('',(0.,0.,1.));
#2155=AXIS2_PLACEMENT_3D('',#2152,#2153,#2154);
#2156=CYLINDRICAL_SURFACE('',#2155,84.13877);
#2157=ORIENTED_EDGE('',*,*,#976,.F.);
#2158=ORIENTED_EDGE('',*,*,#2146,.F.);
#2159=ORIENTED_EDGE('',*,*,#735,.T.);
#2160=ORIENTED_EDGE('',*,*,#2129,.T.);
#2161=EDGE_LOOP('',(#2157,#2158,#2159,#2160));
#2162=FACE_BOUND('',#2161,.T.);
#2163=ADVANCED_FACE('F1749',(#2162),#2156,.F.);
#2164=CARTESIAN_POINT('',(12.,57.6935129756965,39.4199887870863));
#2165=DIRECTION('',(-1.,0.,0.));
#2166=DIRECTION('',(0.,0.,1.));
#2167=AXIS2_PLACEMENT_3D('',#2164,#2165,#2166);
#2168=CYLINDRICAL_SURFACE('',#2167,38.1);
#2169=ORIENTED_EDGE('',*,*,#1894,.T.);
#2170=ORIENTED_EDGE('',*,*,#1016,.F.);
#2171=DIRECTION('',(-1.,0.,0.));
#2172=VECTOR('',#2171,1.);
#2173=CARTESIAN_POINT('',(12.,40.8139694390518,73.5768476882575));
#2174=LINE('',#2173,#2172);
#2175=EDGE_CURVE('E1102',#694,#1006,#2174,.T.);
#2176=ORIENTED_EDGE('',*,*,#2175,.F.);
#2177=ORIENTED_EDGE('',*,*,#695,.T.);
#2178=EDGE_LOOP('',(#2169,#2170,#2176,#2177));
#2179=FACE_BOUND('',#2178,.T.);
#2180=ADVANCED_FACE('F1735',(#2179),#2168,.F.);
#2181=CARTESIAN_POINT('',(12.,5.2919552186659,69.6740422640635));
#2182=DIRECTION('',(-1.,0.,0.));
#2183=DIRECTION('',(0.,0.,1.));
#2184=AXIS2_PLACEMENT_3D('',#2181,#2182,#2183);
#2185=CYLINDRICAL_SURFACE('',#2184,38.1);
#2186=ORIENTED_EDGE('',*,*,#1904,.T.);
#2187=ORIENTED_EDGE('',*,*,#713,.T.);
#2188=DIRECTION('',(-1.,0.,0.));
#2189=VECTOR('',#2188,1.);
#2190=CARTESIAN_POINT('',(12.,43.3124345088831,72.1343582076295));
#2191=LINE('',#2190,#2189);
#2192=EDGE_CURVE('E1095',#703,#997,#2191,.T.);
#2193=ORIENTED_EDGE('',*,*,#2192,.T.);
#2194=ORIENTED_EDGE('',*,*,#998,.T.);
#2195=EDGE_LOOP('',(#2186,#2187,#2193,#2194));
#2196=FACE_BOUND('',#2195,.T.);
#2197=ADVANCED_FACE('F1743',(#2196),#2185,.F.);
#2198=CARTESIAN_POINT('',(12.,0.,0.));
#2199=DIRECTION('',(-1.,0.,0.));
#2200=DIRECTION('',(0.,0.,1.));
#2201=AXIS2_PLACEMENT_3D('',#2198,#2199,#2200);
#2202=CYLINDRICAL_SURFACE('',#2201,84.13877);
#2203=ORIENTED_EDGE('',*,*,#1007,.F.);
#2204=ORIENTED_EDGE('',*,*,#2192,.F.);
#2205=ORIENTED_EDGE('',*,*,#704,.T.);
#2206=ORIENTED_EDGE('',*,*,#2175,.T.);
#2207=EDGE_LOOP('',(#2203,#2204,#2205,#2206));
#2208=FACE_BOUND('',#2207,.T.);
#2209=ADVANCED_FACE('F1740',(#2208),#2202,.F.);
#2210=CARTESIAN_POINT('',(12.,45.5250103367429,53.0089651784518));
#2211=DIRECTION('',(-1.,0.,0.));
#2212=DIRECTION('',(0.,0.,1.));
#2213=AXIS2_PLACEMENT_3D('',#2210,#2211,#2212);
#2214=CYLINDRICAL_SURFACE('',#2213,38.1);
#2215=ORIENTED_EDGE('',*,*,#1877,.T.);
#2216=ORIENTED_EDGE('',*,*,#1047,.F.);
#2217=DIRECTION('',(-1.,0.,0.));
#2218=VECTOR('',#2217,1.);
#2219=CARTESIAN_POINT('',(12.,20.3801776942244,81.6332099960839));
#2220=LINE('',#2219,#2218);
#2221=EDGE_CURVE('E1078',#663,#1037,#2220,.T.);
#2222=ORIENTED_EDGE('',*,*,#2221,.F.);
#2223=ORIENTED_EDGE('',*,*,#664,.T.);
#2224=EDGE_LOOP('',(#2215,#2216,#2222,#2223));
#2225=FACE_BOUND('',#2224,.T.);
#2226=ADVANCED_FACE('F1725',(#2225),#2214,.F.);
#2227=CARTESIAN_POINT('',(12.,-12.921332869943,68.6696156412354));
#2228=DIRECTION('',(-1.,0.,0.));
#2229=DIRECTION('',(0.,0.,1.));
#2230=AXIS2_PLACEMENT_3D('',#2227,#2228,#2229);
#2231=CYLINDRICAL_SURFACE('',#2230,38.1);
#2232=ORIENTED_EDGE('',*,*,#1887,.T.);
#2233=ORIENTED_EDGE('',*,*,#682,.T.);
#2234=DIRECTION('',(-1.,0.,0.));
#2235=VECTOR('',#2234,1.);
#2236=CARTESIAN_POINT('',(12.,23.1668533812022,80.8865224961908));
#2237=LINE('',#2236,#2235);
#2238=EDGE_CURVE('E1071',#672,#1028,#2237,.T.);
#2239=ORIENTED_EDGE('',*,*,#2238,.T.);
#2240=ORIENTED_EDGE('',*,*,#1029,.T.);
#2241=EDGE_LOOP('',(#2232,#2233,#2239,#2240));
#2242=FACE_BOUND('',#2241,.T.);
#2243=ADVANCED_FACE('F1733',(#2242),#2231,.F.);
#2244=CARTESIAN_POINT('',(12.,0.,0.));
#2245=DIRECTION('',(-1.,0.,0.));
#2246=DIRECTION('',(0.,0.,1.));
#2247=AXIS2_PLACEMENT_3D('',#2244,#2245,#2246);
#2248=CYLINDRICAL_SURFACE('',#2247,84.13877);
#2249=ORIENTED_EDGE('',*,*,#1038,.F.);
#2250=ORIENTED_EDGE('',*,*,#2238,.F.);
#2251=ORIENTED_EDGE('',*,*,#673,.T.);
#2252=ORIENTED_EDGE('',*,*,#2221,.T.);
#2253=EDGE_LOOP('',(#2249,#2250,#2251,#2252));
#2254=FACE_BOUND('',#2253,.T.);
#2255=ADVANCED_FACE('F1730',(#2254),#2248,.F.);
#2256=CARTESIAN_POINT('',(12.,30.2540534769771,62.9854681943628));
#2257=DIRECTION('',(-1.,0.,0.));
#2258=DIRECTION('',(0.,0.,1.));
#2259=AXIS2_PLACEMENT_3D('',#2256,#2257,#2258);
#2260=CYLINDRICAL_SURFACE('',#2259,38.1);
#2261=ORIENTED_EDGE('',*,*,#1860,.T.);
#2262=ORIENTED_EDGE('',*,*,#1078,.F.);
#2263=DIRECTION('',(-1.,0.,0.));
#2264=VECTOR('',#2263,1.);
#2265=CARTESIAN_POINT('',(12.,-1.44248948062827,84.1264039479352));
#2266=LINE('',#2265,#2264);
#2267=EDGE_CURVE('E1054',#632,#1068,#2266,.T.);
#2268=ORIENTED_EDGE('',*,*,#2267,.F.);
#2269=ORIENTED_EDGE('',*,*,#633,.T.);
#2270=EDGE_LOOP('',(#2261,#2262,#2268,#2269));
#2271=FACE_BOUND('',#2270,.T.);
#2272=ADVANCED_FACE('F1714',(#2271),#2260,.F.);
#2273=CARTESIAN_POINT('',(12.,-30.2540534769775,62.9854681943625));
#2274=DIRECTION('',(-1.,0.,0.));
#2275=DIRECTION('',(0.,0.,1.));
#2276=AXIS2_PLACEMENT_3D('',#2273,#2274,#2275);
#2277=CYLINDRICAL_SURFACE('',#2276,38.1);
#2278=ORIENTED_EDGE('',*,*,#1870,.T.);
#2279=ORIENTED_EDGE('',*,*,#651,.T.);
#2280=DIRECTION('',(-1.,0.,0.));
#2281=VECTOR('',#2280,1.);
#2282=CARTESIAN_POINT('',(12.,1.44248948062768,84.1264039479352));
#2283=LINE('',#2282,#2281);
#2284=EDGE_CURVE('E1047',#641,#1059,#2283,.T.);
#2285=ORIENTED_EDGE('',*,*,#2284,.T.);
#2286=ORIENTED_EDGE('',*,*,#1060,.T.);
#2287=EDGE_LOOP('',(#2278,#2279,#2285,#2286));
#2288=FACE_BOUND('',#2287,.T.);
#2289=ADVANCED_FACE('F1722',(#2288),#2277,.F.);
#2290=CARTESIAN_POINT('',(12.,0.,0.));
#2291=DIRECTION('',(-1.,0.,0.));
#2292=DIRECTION('',(0.,0.,1.));
#2293=AXIS2_PLACEMENT_3D('',#2290,#2291,#2292);
#2294=CYLINDRICAL_SURFACE('',#2293,84.13877);
#2295=ORIENTED_EDGE('',*,*,#1069,.F.);
#2296=ORIENTED_EDGE('',*,*,#2284,.F.);
#2297=ORIENTED_EDGE('',*,*,#642,.T.);
#2298=ORIENTED_EDGE('',*,*,#2267,.T.);
#2299=EDGE_LOOP('',(#2295,#2296,#2297,#2298));
#2300=FACE_BOUND('',#2299,.T.);
#2301=ADVANCED_FACE('F1719',(#2300),#2294,.F.);
#2302=CARTESIAN_POINT('',(12.,12.9213328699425,68.6696156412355));
#2303=DIRECTION('',(-1.,0.,0.));
#2304=DIRECTION('',(0.,0.,1.));
#2305=AXIS2_PLACEMENT_3D('',#2302,#2303,#2304);
#2306=CYLINDRICAL_SURFACE('',#2305,38.1);
#2307=ORIENTED_EDGE('',*,*,#1843,.T.);
#2308=ORIENTED_EDGE('',*,*,#1109,.F.);
#2309=DIRECTION('',(-1.,0.,0.));
#2310=VECTOR('',#2309,1.);
#2311=CARTESIAN_POINT('',(12.,-23.1668533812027,80.8865224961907));
#2312=LINE('',#2311,#2310);
#2313=EDGE_CURVE('E1030',#601,#1099,#2312,.T.);
#2314=ORIENTED_EDGE('',*,*,#2313,.F.);
#2315=ORIENTED_EDGE('',*,*,#602,.T.);
#2316=EDGE_LOOP('',(#2307,#2308,#2314,#2315));
#2317=FACE_BOUND('',#2316,.T.);
#2318=ADVANCED_FACE('F1703',(#2317),#2306,.F.);
#2319=CARTESIAN_POINT('',(12.,-45.5250103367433,53.0089651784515));
#2320=DIRECTION('',(-1.,0.,0.));
#2321=DIRECTION('',(0.,0.,1.));
#2322=AXIS2_PLACEMENT_3D('',#2319,#2320,#2321);
#2323=CYLINDRICAL_SURFACE('',#2322,38.1);
#2324=ORIENTED_EDGE('',*,*,#1853,.T.);
#2325=ORIENTED_EDGE('',*,*,#620,.T.);
#2326=DIRECTION('',(-1.,0.,0.));
#2327=VECTOR('',#2326,1.);
#2328=CARTESIAN_POINT('',(12.,-20.380177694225,81.6332099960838));
#2329=LINE('',#2328,#2327);
#2330=EDGE_CURVE('E1023',#610,#1090,#2329,.T.);
#2331=ORIENTED_EDGE('',*,*,#2330,.T.);
#2332=ORIENTED_EDGE('',*,*,#1091,.T.);
#2333=EDGE_LOOP('',(#2324,#2325,#2331,#2332));
#2334=FACE_BOUND('',#2333,.T.);
#2335=ADVANCED_FACE('F1711',(#2334),#2323,.F.);
#2336=CARTESIAN_POINT('',(12.,0.,0.));
#2337=DIRECTION('',(-1.,0.,0.));
#2338=DIRECTION('',(0.,0.,1.));
#2339=AXIS2_PLACEMENT_3D('',#2336,#2337,#2338);
#2340=CYLINDRICAL_SURFACE('',#2339,84.13877);
#2341=ORIENTED_EDGE('',*,*,#1100,.F.);
#2342=ORIENTED_EDGE('',*,*,#2330,.F.);
#2343=ORIENTED_EDGE('',*,*,#611,.T.);
#2344=ORIENTED_EDGE('',*,*,#2313,.T.);
#2345=EDGE_LOOP('',(#2341,#2342,#2343,#2344));
#2346=FACE_BOUND('',#2345,.T.);
#2347=ADVANCED_FACE('F1708',(#2346),#2340,.F.);
#2348=CARTESIAN_POINT('',(12.,-5.29195521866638,69.6740422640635));
#2349=DIRECTION('',(-1.,0.,0.));
#2350=DIRECTION('',(0.,0.,1.));
#2351=AXIS2_PLACEMENT_3D('',#2348,#2349,#2350);
#2352=CYLINDRICAL_SURFACE('',#2351,38.1);
#2353=ORIENTED_EDGE('',*,*,#1826,.T.);
#2354=ORIENTED_EDGE('',*,*,#1140,.F.);
#2355=DIRECTION('',(-1.,0.,0.));
#2356=VECTOR('',#2355,1.);
#2357=CARTESIAN_POINT('',(12.,-43.3124345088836,72.1343582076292));
#2358=LINE('',#2357,#2356);
#2359=EDGE_CURVE('E1006',#570,#1130,#2358,.T.);
#2360=ORIENTED_EDGE('',*,*,#2359,.F.);
#2361=ORIENTED_EDGE('',*,*,#571,.T.);
#2362=EDGE_LOOP('',(#2353,#2354,#2360,#2361));
#2363=FACE_BOUND('',#2362,.T.);
#2364=ADVANCED_FACE('F1692',(#2363),#2352,.F.);
#2365=CARTESIAN_POINT('',(12.,-57.6935129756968,39.4199887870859));
#2366=DIRECTION('',(-1.,0.,0.));
#2367=DIRECTION('',(0.,0.,1.));
#2368=AXIS2_PLACEMENT_3D('',#2365,#2366,#2367);
#2369=CYLINDRICAL_SURFACE('',#2368,38.1);
#2370=ORIENTED_EDGE('',*,*,#1836,.T.);
#2371=ORIENTED_EDGE('',*,*,#589,.T.);
#2372=DIRECTION('',(-1.,0.,0.));
#2373=VECTOR('',#2372,1.);
#2374=CARTESIAN_POINT('',(12.,-40.8139694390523,73.5768476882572));
#2375=LINE('',#2374,#2373);
#2376=EDGE_CURVE('E999',#579,#1121,#2375,.T.);
#2377=ORIENTED_EDGE('',*,*,#2376,.T.);
#2378=ORIENTED_EDGE('',*,*,#1122,.T.);
#2379=EDGE_LOOP('',(#2370,#2371,#2377,#2378));
#2380=FACE_BOUND('',#2379,.T.);
#2381=ADVANCED_FACE('F1700',(#2380),#2369,.F.);
#2382=CARTESIAN_POINT('',(12.,0.,0.));
#2383=DIRECTION('',(-1.,0.,0.));
#2384=DIRECTION('',(0.,0.,1.));
#2385=AXIS2_PLACEMENT_3D('',#2382,#2383,#2384);
#2386=CYLINDRICAL_SURFACE('',#2385,84.13877);
#2387=ORIENTED_EDGE('',*,*,#1131,.F.);
#2388=ORIENTED_EDGE('',*,*,#2376,.F.);
#2389=ORIENTED_EDGE('',*,*,#580,.T.);
#2390=ORIENTED_EDGE('',*,*,#2359,.T.);
#2391=EDGE_LOOP('',(#2387,#2388,#2389,#2390));
#2392=FACE_BOUND('',#2391,.T.);
#2393=ADVANCED_FACE('F1697',(#2392),#2386,.F.);
#2394=CARTESIAN_POINT('',(12.,-23.1446053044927,65.9302980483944));
#2395=DIRECTION('',(-1.,0.,0.));
#2396=DIRECTION('',(0.,0.,1.));
#2397=AXIS2_PLACEMENT_3D('',#2394,#2395,#2396);
#2398=CYLINDRICAL_SURFACE('',#2397,38.1);
#2399=ORIENTED_EDGE('',*,*,#1809,.T.);
#2400=ORIENTED_EDGE('',*,*,#1171,.F.);
#2401=DIRECTION('',(-1.,0.,0.));
#2402=VECTOR('',#2401,1.);
#2403=CARTESIAN_POINT('',(12.,-60.5063448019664,58.4663566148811));
#2404=LINE('',#2403,#2402);
#2405=EDGE_CURVE('E982',#539,#1161,#2404,.T.);
#2406=ORIENTED_EDGE('',*,*,#2405,.F.);
#2407=ORIENTED_EDGE('',*,*,#540,.T.);
#2408=EDGE_LOOP('',(#2399,#2400,#2406,#2407));
#2409=FACE_BOUND('',#2408,.T.);
#2410=ADVANCED_FACE('F1681',(#2409),#2398,.F.);
#2411=CARTESIAN_POINT('',(12.,-65.9302980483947,23.144605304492));
#2412=DIRECTION('',(-1.,0.,0.));
#2413=DIRECTION('',(0.,0.,1.));
#2414=AXIS2_PLACEMENT_3D('',#2411,#2412,#2413);
#2415=CYLINDRICAL_SURFACE('',#2414,38.1);
#2416=ORIENTED_EDGE('',*,*,#1819,.T.);
#2417=ORIENTED_EDGE('',*,*,#558,.T.);
#2418=DIRECTION('',(-1.,0.,0.));
#2419=VECTOR('',#2418,1.);
#2420=CARTESIAN_POINT('',(12.,-58.4663566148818,60.5063448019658));
#2421=LINE('',#2420,#2419);
#2422=EDGE_CURVE('E975',#548,#1152,#2421,.T.);
#2423=ORIENTED_EDGE('',*,*,#2422,.T.);
#2424=ORIENTED_EDGE('',*,*,#1153,.T.);
#2425=EDGE_LOOP('',(#2416,#2417,#2423,#2424));
#2426=FACE_BOUND('',#2425,.T.);
#2427=ADVANCED_FACE('F1689',(#2426),#2415,.F.);
#2428=CARTESIAN_POINT('',(12.,0.,0.));
#2429=DIRECTION('',(-1.,0.,0.));
#2430=DIRECTION('',(0.,0.,1.));
#2431=AXIS2_PLACEMENT_3D('',#2428,#2429,#2430);
#2432=CYLINDRICAL_SURFACE('',#2431,84.13877);
#2433=ORIENTED_EDGE('',*,*,#1162,.F.);
#2434=ORIENTED_EDGE('',*,*,#2422,.F.);
#2435=ORIENTED_EDGE('',*,*,#549,.T.);
#2436=ORIENTED_EDGE('',*,*,#2405,.T.);
#2437=EDGE_LOOP('',(#2433,#2434,#2435,#2436));
#2438=FACE_BOUND('',#2437,.T.);
#2439=ADVANCED_FACE('F1686',(#2438),#2432,.F.);
#2440=CARTESIAN_POINT('',(12.,-39.4199887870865,57.6935129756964));
#2441=DIRECTION('',(-1.,0.,0.));
#2442=DIRECTION('',(0.,0.,1.));
#2443=AXIS2_PLACEMENT_3D('',#2440,#2441,#2442);
#2444=CYLINDRICAL_SURFACE('',#2443,38.1);
#2445=ORIENTED_EDGE('',*,*,#1792,.T.);
#2446=ORIENTED_EDGE('',*,*,#1202,.F.);
#2447=DIRECTION('',(-1.,0.,0.));
#2448=VECTOR('',#2447,1.);
#2449=CARTESIAN_POINT('',(12.,-73.5768476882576,40.8139694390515));
#2450=LINE('',#2449,#2448);
#2451=EDGE_CURVE('E958',#508,#1192,#2450,.T.);
#2452=ORIENTED_EDGE('',*,*,#2451,.F.);
#2453=ORIENTED_EDGE('',*,*,#509,.T.);
#2454=EDGE_LOOP('',(#2445,#2446,#2452,#2453));
#2455=FACE_BOUND('',#2454,.T.);
#2456=ADVANCED_FACE('F1670',(#2455),#2444,.F.);
#2457=CARTESIAN_POINT('',(12.,-69.6740422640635,5.29195521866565));
#2458=DIRECTION('',(-1.,0.,0.));
#2459=DIRECTION('',(0.,0.,1.));
#2460=AXIS2_PLACEMENT_3D('',#2457,#2458,#2459);
#2461=CYLINDRICAL_SURFACE('',#2460,38.1);
#2462=ORIENTED_EDGE('',*,*,#1802,.T.);
#2463=ORIENTED_EDGE('',*,*,#527,.T.);
#2464=DIRECTION('',(-1.,0.,0.));
#2465=VECTOR('',#2464,1.);
#2466=CARTESIAN_POINT('',(12.,-72.1343582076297,43.3124345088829));
#2467=LINE('',#2466,#2465);
#2468=EDGE_CURVE('E951',#517,#1183,#2467,.T.);
#2469=ORIENTED_EDGE('',*,*,#2468,.T.);
#2470=ORIENTED_EDGE('',*,*,#1184,.T.);
#2471=EDGE_LOOP('',(#2462,#2463,#2469,#2470));
#2472=FACE_BOUND('',#2471,.T.);
#2473=ADVANCED_FACE('F1678',(#2472),#2461,.F.);
#2474=CARTESIAN_POINT('',(12.,0.,0.));
#2475=DIRECTION('',(-1.,0.,0.));
#2476=DIRECTION('',(0.,0.,1.));
#2477=AXIS2_PLACEMENT_3D('',#2474,#2475,#2476);
#2478=CYLINDRICAL_SURFACE('',#2477,84.13877);
#2479=ORIENTED_EDGE('',*,*,#1193,.F.);
#2480=ORIENTED_EDGE('',*,*,#2468,.F.);
#2481=ORIENTED_EDGE('',*,*,#518,.T.);
#2482=ORIENTED_EDGE('',*,*,#2451,.T.);
#2483=EDGE_LOOP('',(#2479,#2480,#2481,#2482));
#2484=FACE_BOUND('',#2483,.T.);
#2485=ADVANCED_FACE('F1675',(#2484),#2478,.F.);
#2486=CARTESIAN_POINT('',(12.,-53.008965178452,45.5250103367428));
#2487=DIRECTION('',(-1.,0.,0.));
#2488=DIRECTION('',(0.,0.,1.));
#2489=AXIS2_PLACEMENT_3D('',#2486,#2487,#2488);
#2490=CYLINDRICAL_SURFACE('',#2489,38.1);
#2491=ORIENTED_EDGE('',*,*,#1775,.T.);
#2492=ORIENTED_EDGE('',*,*,#1233,.F.);
#2493=DIRECTION('',(-1.,0.,0.));
#2494=VECTOR('',#2493,1.);
#2495=CARTESIAN_POINT('',(12.,-81.633209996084,20.3801776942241));
#2496=LINE('',#2495,#2494);
#2497=EDGE_CURVE('E934',#477,#1223,#2496,.T.);
#2498=ORIENTED_EDGE('',*,*,#2497,.F.);
#2499=ORIENTED_EDGE('',*,*,#478,.T.);
#2500=EDGE_LOOP('',(#2491,#2492,#2498,#2499));
#2501=FACE_BOUND('',#2500,.T.);
#2502=ADVANCED_FACE('F1659',(#2501),#2490,.F.);
#2503=CARTESIAN_POINT('',(12.,-68.6696156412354,-12.9213328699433));
#2504=DIRECTION('',(-1.,0.,0.));
#2505=DIRECTION('',(0.,0.,1.));
#2506=AXIS2_PLACEMENT_3D('',#2503,#2504,#2505);
#2507=CYLINDRICAL_SURFACE('',#2506,38.1);
#2508=ORIENTED_EDGE('',*,*,#1785,.T.);
#2509=ORIENTED_EDGE('',*,*,#496,.T.);
#2510=DIRECTION('',(-1.,0.,0.));
#2511=VECTOR('',#2510,1.);
#2512=CARTESIAN_POINT('',(12.,-80.8865224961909,23.1668533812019));
#2513=LINE('',#2512,#2511);
#2514=EDGE_CURVE('E927',#486,#1214,#2513,.T.);
#2515=ORIENTED_EDGE('',*,*,#2514,.T.);
#2516=ORIENTED_EDGE('',*,*,#1215,.T.);
#2517=EDGE_LOOP('',(#2508,#2509,#2515,#2516));
#2518=FACE_BOUND('',#2517,.T.);
#2519=ADVANCED_FACE('F1667',(#2518),#2507,.F.);
#2520=CARTESIAN_POINT('',(12.,0.,0.));
#2521=DIRECTION('',(-1.,0.,0.));
#2522=DIRECTION('',(0.,0.,1.));
#2523=AXIS2_PLACEMENT_3D('',#2520,#2521,#2522);
#2524=CYLINDRICAL_SURFACE('',#2523,84.13877);
#2525=ORIENTED_EDGE('',*,*,#1224,.F.);
#2526=ORIENTED_EDGE('',*,*,#2514,.F.);
#2527=ORIENTED_EDGE('',*,*,#487,.T.);
#2528=ORIENTED_EDGE('',*,*,#2497,.T.);
#2529=EDGE_LOOP('',(#2525,#2526,#2527,#2528));
#2530=FACE_BOUND('',#2529,.T.);
#2531=ADVANCED_FACE('F1664',(#2530),#2524,.F.);
#2532=CARTESIAN_POINT('',(12.,-62.9854681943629,30.2540534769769));
#2533=DIRECTION('',(-1.,0.,0.));
#2534=DIRECTION('',(0.,0.,1.));
#2535=AXIS2_PLACEMENT_3D('',#2532,#2533,#2534);
#2536=CYLINDRICAL_SURFACE('',#2535,38.1);
#2537=ORIENTED_EDGE('',*,*,#1758,.T.);
#2538=ORIENTED_EDGE('',*,*,#1264,.F.);
#2539=DIRECTION('',(-1.,0.,0.));
#2540=VECTOR('',#2539,1.);
#2541=CARTESIAN_POINT('',(12.,-84.1264039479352,-1.44248948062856));
#2542=LINE('',#2541,#2540);
#2543=EDGE_CURVE('E910',#446,#1254,#2542,.T.);
#2544=ORIENTED_EDGE('',*,*,#2543,.F.);
#2545=ORIENTED_EDGE('',*,*,#447,.T.);
#2546=EDGE_LOOP('',(#2537,#2538,#2544,#2545));
#2547=FACE_BOUND('',#2546,.T.);
#2548=ADVANCED_FACE('F1648',(#2547),#2536,.F.);
#2549=CARTESIAN_POINT('',(12.,-62.9854681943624,-30.2540534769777));
#2550=DIRECTION('',(-1.,0.,0.));
#2551=DIRECTION('',(0.,0.,1.));
#2552=AXIS2_PLACEMENT_3D('',#2549,#2550,#2551);
#2553=CYLINDRICAL_SURFACE('',#2552,38.1);
#2554=ORIENTED_EDGE('',*,*,#1768,.T.);
#2555=ORIENTED_EDGE('',*,*,#465,.T.);
#2556=DIRECTION('',(-1.,0.,0.));
#2557=VECTOR('',#2556,1.);
#2558=CARTESIAN_POINT('',(12.,-84.1264039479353,1.44248948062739));
#2559=LINE('',#2558,#2557);
#2560=EDGE_CURVE('E903',#455,#1245,#2559,.T.);
#2561=ORIENTED_EDGE('',*,*,#2560,.T.);
#2562=ORIENTED_EDGE('',*,*,#1246,.T.);
#2563=EDGE_LOOP('',(#2554,#2555,#2561,#2562));
#2564=FACE_BOUND('',#2563,.T.);
#2565=ADVANCED_FACE('F1656',(#2564),#2553,.F.);
#2566=CARTESIAN_POINT('',(12.,0.,0.));
#2567=DIRECTION('',(-1.,0.,0.));
#2568=DIRECTION('',(0.,0.,1.));
#2569=AXIS2_PLACEMENT_3D('',#2566,#2567,#2568);
#2570=CYLINDRICAL_SURFACE('',#2569,84.13877);
#2571=ORIENTED_EDGE('',*,*,#1255,.F.);
#2572=ORIENTED_EDGE('',*,*,#2560,.F.);
#2573=ORIENTED_EDGE('',*,*,#456,.T.);
#2574=ORIENTED_EDGE('',*,*,#2543,.T.);
#2575=EDGE_LOOP('',(#2571,#2572,#2573,#2574));
#2576=FACE_BOUND('',#2575,.T.);
#2577=ADVANCED_FACE('F1653',(#2576),#2570,.F.);
#2578=CARTESIAN_POINT('',(12.,-68.6696156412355,12.9213328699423));
#2579=DIRECTION('',(-1.,0.,0.));
#2580=DIRECTION('',(0.,0.,1.));
#2581=AXIS2_PLACEMENT_3D('',#2578,#2579,#2580);
#2582=CYLINDRICAL_SURFACE('',#2581,38.1);
#2583=ORIENTED_EDGE('',*,*,#1741,.T.);
#2584=ORIENTED_EDGE('',*,*,#1295,.F.);
#2585=DIRECTION('',(-1.,0.,0.));
#2586=VECTOR('',#2585,1.);
#2587=CARTESIAN_POINT('',(12.,-80.8865224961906,-23.166853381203));
#2588=LINE('',#2587,#2586);
#2589=EDGE_CURVE('E886',#415,#1285,#2588,.T.);
#2590=ORIENTED_EDGE('',*,*,#2589,.F.);
#2591=ORIENTED_EDGE('',*,*,#416,.T.);
#2592=EDGE_LOOP('',(#2583,#2584,#2590,#2591));
#2593=FACE_BOUND('',#2592,.T.);
#2594=ADVANCED_FACE('F1637',(#2593),#2582,.F.);
#2595=CARTESIAN_POINT('',(12.,-53.0089651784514,-45.5250103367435));
#2596=DIRECTION('',(-1.,0.,0.));
#2597=DIRECTION('',(0.,0.,1.));
#2598=AXIS2_PLACEMENT_3D('',#2595,#2596,#2597);
#2599=CYLINDRICAL_SURFACE('',#2598,38.1);
#2600=ORIENTED_EDGE('',*,*,#1751,.T.);
#2601=ORIENTED_EDGE('',*,*,#434,.T.);
#2602=DIRECTION('',(-1.,0.,0.));
#2603=VECTOR('',#2602,1.);
#2604=CARTESIAN_POINT('',(12.,-81.6332099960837,-20.3801776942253));
#2605=LINE('',#2604,#2603);
#2606=EDGE_CURVE('E879',#424,#1276,#2605,.T.);
#2607=ORIENTED_EDGE('',*,*,#2606,.T.);
#2608=ORIENTED_EDGE('',*,*,#1277,.T.);
#2609=EDGE_LOOP('',(#2600,#2601,#2607,#2608));
#2610=FACE_BOUND('',#2609,.T.);
#2611=ADVANCED_FACE('F1645',(#2610),#2599,.F.);
#2612=CARTESIAN_POINT('',(12.,0.,0.));
#2613=DIRECTION('',(-1.,0.,0.));
#2614=DIRECTION('',(0.,0.,1.));
#2615=AXIS2_PLACEMENT_3D('',#2612,#2613,#2614);
#2616=CYLINDRICAL_SURFACE('',#2615,84.13877);
#2617=ORIENTED_EDGE('',*,*,#1286,.F.);
#2618=ORIENTED_EDGE('',*,*,#2606,.F.);
#2619=ORIENTED_EDGE('',*,*,#425,.T.);
#2620=ORIENTED_EDGE('',*,*,#2589,.T.);
#2621=EDGE_LOOP('',(#2617,#2618,#2619,#2620));
#2622=FACE_BOUND('',#2621,.T.);
#2623=ADVANCED_FACE('F1642',(#2622),#2616,.F.);
#2624=CARTESIAN_POINT('',(12.,-69.6740422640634,-5.29195521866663));
#2625=DIRECTION('',(-1.,0.,0.));
#2626=DIRECTION('',(0.,0.,1.));
#2627=AXIS2_PLACEMENT_3D('',#2624,#2625,#2626);
#2628=CYLINDRICAL_SURFACE('',#2627,38.1);
#2629=ORIENTED_EDGE('',*,*,#1724,.T.);
#2630=ORIENTED_EDGE('',*,*,#1326,.F.);
#2631=DIRECTION('',(-1.,0.,0.));
#2632=VECTOR('',#2631,1.);
#2633=CARTESIAN_POINT('',(12.,-72.1343582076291,-43.3124345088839));
#2634=LINE('',#2633,#2632);
#2635=EDGE_CURVE('E862',#384,#1316,#2634,.T.);
#2636=ORIENTED_EDGE('',*,*,#2635,.F.);
#2637=ORIENTED_EDGE('',*,*,#385,.T.);
#2638=EDGE_LOOP('',(#2629,#2630,#2636,#2637));
#2639=FACE_BOUND('',#2638,.T.);
#2640=ADVANCED_FACE('F1626',(#2639),#2628,.F.);
#2641=CARTESIAN_POINT('',(12.,-39.4199887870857,-57.6935129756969));
#2642=DIRECTION('',(-1.,0.,0.));
#2643=DIRECTION('',(0.,0.,1.));
#2644=AXIS2_PLACEMENT_3D('',#2641,#2642,#2643);
#2645=CYLINDRICAL_SURFACE('',#2644,38.1);
#2646=ORIENTED_EDGE('',*,*,#1734,.T.);
#2647=ORIENTED_EDGE('',*,*,#403,.T.);
#2648=DIRECTION('',(-1.,0.,0.));
#2649=VECTOR('',#2648,1.);
#2650=CARTESIAN_POINT('',(12.,-73.5768476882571,-40.8139694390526));
#2651=LINE('',#2650,#2649);
#2652=EDGE_CURVE('E855',#393,#1307,#2651,.T.);
#2653=ORIENTED_EDGE('',*,*,#2652,.T.);
#2654=ORIENTED_EDGE('',*,*,#1308,.T.);
#2655=EDGE_LOOP('',(#2646,#2647,#2653,#2654));
#2656=FACE_BOUND('',#2655,.T.);
#2657=ADVANCED_FACE('F1634',(#2656),#2645,.F.);
#2658=CARTESIAN_POINT('',(12.,0.,0.));
#2659=DIRECTION('',(-1.,0.,0.));
#2660=DIRECTION('',(0.,0.,1.));
#2661=AXIS2_PLACEMENT_3D('',#2658,#2659,#2660);
#2662=CYLINDRICAL_SURFACE('',#2661,84.13877);
#2663=ORIENTED_EDGE('',*,*,#1317,.F.);
#2664=ORIENTED_EDGE('',*,*,#2652,.F.);
#2665=ORIENTED_EDGE('',*,*,#394,.T.);
#2666=ORIENTED_EDGE('',*,*,#2635,.T.);
#2667=EDGE_LOOP('',(#2663,#2664,#2665,#2666));
#2668=FACE_BOUND('',#2667,.T.);
#2669=ADVANCED_FACE('F1631',(#2668),#2662,.F.);
#2670=CARTESIAN_POINT('',(12.,-65.9302980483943,-23.1446053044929));
#2671=DIRECTION('',(-1.,0.,0.));
#2672=DIRECTION('',(0.,0.,1.));
#2673=AXIS2_PLACEMENT_3D('',#2670,#2671,#2672);
#2674=CYLINDRICAL_SURFACE('',#2673,38.1);
#2675=ORIENTED_EDGE('',*,*,#1707,.T.);
#2676=ORIENTED_EDGE('',*,*,#1357,.F.);
#2677=DIRECTION('',(-1.,0.,0.));
#2678=VECTOR('',#2677,1.);
#2679=CARTESIAN_POINT('',(12.,-58.4663566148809,-60.5063448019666));
#2680=LINE('',#2679,#2678);
#2681=EDGE_CURVE('E838',#353,#1347,#2680,.T.);
#2682=ORIENTED_EDGE('',*,*,#2681,.F.);
#2683=ORIENTED_EDGE('',*,*,#354,.T.);
#2684=EDGE_LOOP('',(#2675,#2676,#2682,#2683));
#2685=FACE_BOUND('',#2684,.T.);
#2686=ADVANCED_FACE('F1615',(#2685),#2674,.F.);
#2687=CARTESIAN_POINT('',(12.,-23.1446053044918,-65.9302980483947));
#2688=DIRECTION('',(-1.,0.,0.));
#2689=DIRECTION('',(0.,0.,1.));
#2690=AXIS2_PLACEMENT_3D('',#2687,#2688,#2689);
#2691=CYLINDRICAL_SURFACE('',#2690,38.1);
#2692=ORIENTED_EDGE('',*,*,#1717,.T.);
#2693=ORIENTED_EDGE('',*,*,#372,.T.);
#2694=DIRECTION('',(-1.,0.,0.));
#2695=VECTOR('',#2694,1.);
#2696=CARTESIAN_POINT('',(12.,-60.5063448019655,-58.466356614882));
#2697=LINE('',#2696,#2695);
#2698=EDGE_CURVE('E831',#362,#1338,#2697,.T.);
#2699=ORIENTED_EDGE('',*,*,#2698,.T.);
#2700=ORIENTED_EDGE('',*,*,#1339,.T.);
#2701=EDGE_LOOP('',(#2692,#2693,#2699,#2700));
#2702=FACE_BOUND('',#2701,.T.);
#2703=ADVANCED_FACE('F1623',(#2702),#2691,.F.);
#2704=CARTESIAN_POINT('',(12.,0.,0.));
#2705=DIRECTION('',(-1.,0.,0.));
#2706=DIRECTION('',(0.,0.,1.));
#2707=AXIS2_PLACEMENT_3D('',#2704,#2705,#2706);
#2708=CYLINDRICAL_SURFACE('',#2707,84.13877);
#2709=ORIENTED_EDGE('',*,*,#1348,.F.);
#2710=ORIENTED_EDGE('',*,*,#2698,.F.);
#2711=ORIENTED_EDGE('',*,*,#363,.T.);
#2712=ORIENTED_EDGE('',*,*,#2681,.T.);
#2713=EDGE_LOOP('',(#2709,#2710,#2711,#2712));
#2714=FACE_BOUND('',#2713,.T.);
#2715=ADVANCED_FACE('F1620',(#2714),#2708,.F.);
#2716=CARTESIAN_POINT('',(12.,-57.6935129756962,-39.4199887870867));
#2717=DIRECTION('',(-1.,0.,0.));
#2718=DIRECTION('',(0.,0.,1.));
#2719=AXIS2_PLACEMENT_3D('',#2716,#2717,#2718);
#2720=CYLINDRICAL_SURFACE('',#2719,38.1);
#2721=ORIENTED_EDGE('',*,*,#1690,.T.);
#2722=ORIENTED_EDGE('',*,*,#1388,.F.);
#2723=DIRECTION('',(-1.,0.,0.));
#2724=VECTOR('',#2723,1.);
#2725=CARTESIAN_POINT('',(12.,-40.8139694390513,-73.5768476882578));
#2726=LINE('',#2725,#2724);
#2727=EDGE_CURVE('E814',#322,#1378,#2726,.T.);
#2728=ORIENTED_EDGE('',*,*,#2727,.F.);
#2729=ORIENTED_EDGE('',*,*,#323,.T.);
#2730=EDGE_LOOP('',(#2721,#2722,#2728,#2729));
#2731=FACE_BOUND('',#2730,.T.);
#2732=ADVANCED_FACE('F1604',(#2731),#2720,.F.);
#2733=CARTESIAN_POINT('',(12.,-5.29195521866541,-69.6740422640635));
#2734=DIRECTION('',(-1.,0.,0.));
#2735=DIRECTION('',(0.,0.,1.));
#2736=AXIS2_PLACEMENT_3D('',#2733,#2734,#2735);
#2737=CYLINDRICAL_SURFACE('',#2736,38.1);
#2738=ORIENTED_EDGE('',*,*,#1700,.T.);
#2739=ORIENTED_EDGE('',*,*,#341,.T.);
#2740=DIRECTION('',(-1.,0.,0.));
#2741=VECTOR('',#2740,1.);
#2742=CARTESIAN_POINT('',(12.,-43.3124345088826,-72.1343582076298));
#2743=LINE('',#2742,#2741);
#2744=EDGE_CURVE('E807',#331,#1369,#2743,.T.);
#2745=ORIENTED_EDGE('',*,*,#2744,.T.);
#2746=ORIENTED_EDGE('',*,*,#1370,.T.);
#2747=EDGE_LOOP('',(#2738,#2739,#2745,#2746));
#2748=FACE_BOUND('',#2747,.T.);
#2749=ADVANCED_FACE('F1612',(#2748),#2737,.F.);
#2750=CARTESIAN_POINT('',(12.,0.,0.));
#2751=DIRECTION('',(-1.,0.,0.));
#2752=DIRECTION('',(0.,0.,1.));
#2753=AXIS2_PLACEMENT_3D('',#2750,#2751,#2752);
#2754=CYLINDRICAL_SURFACE('',#2753,84.13877);
#2755=ORIENTED_EDGE('',*,*,#1379,.F.);
#2756=ORIENTED_EDGE('',*,*,#2744,.F.);
#2757=ORIENTED_EDGE('',*,*,#332,.T.);
#2758=ORIENTED_EDGE('',*,*,#2727,.T.);
#2759=EDGE_LOOP('',(#2755,#2756,#2757,#2758));
#2760=FACE_BOUND('',#2759,.T.);
#2761=ADVANCED_FACE('F1609',(#2760),#2754,.F.);
#2762=CARTESIAN_POINT('',(12.,-45.5250103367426,-53.0089651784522));
#2763=DIRECTION('',(-1.,0.,0.));
#2764=DIRECTION('',(0.,0.,1.));
#2765=AXIS2_PLACEMENT_3D('',#2762,#2763,#2764);
#2766=CYLINDRICAL_SURFACE('',#2765,38.1);
#2767=ORIENTED_EDGE('',*,*,#1673,.T.);
#2768=ORIENTED_EDGE('',*,*,#1419,.F.);
#2769=DIRECTION('',(-1.,0.,0.));
#2770=VECTOR('',#2769,1.);
#2771=CARTESIAN_POINT('',(12.,-20.3801776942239,-81.6332099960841));
#2772=LINE('',#2771,#2770);
#2773=EDGE_CURVE('E790',#291,#1409,#2772,.T.);
#2774=ORIENTED_EDGE('',*,*,#2773,.F.);
#2775=ORIENTED_EDGE('',*,*,#292,.T.);
#2776=EDGE_LOOP('',(#2767,#2768,#2774,#2775));
#2777=FACE_BOUND('',#2776,.T.);
#2778=ADVANCED_FACE('F1593',(#2777),#2766,.F.);
#2779=CARTESIAN_POINT('',(12.,12.9213328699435,-68.6696156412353));
#2780=DIRECTION('',(-1.,0.,0.));
#2781=DIRECTION('',(0.,0.,1.));
#2782=AXIS2_PLACEMENT_3D('',#2779,#2780,#2781);
#2783=CYLINDRICAL_SURFACE('',#2782,38.1);
#2784=ORIENTED_EDGE('',*,*,#1683,.T.);
#2785=ORIENTED_EDGE('',*,*,#310,.T.);
#2786=DIRECTION('',(-1.,0.,0.));
#2787=VECTOR('',#2786,1.);
#2788=CARTESIAN_POINT('',(12.,-23.1668533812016,-80.886522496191));
#2789=LINE('',#2788,#2787);
#2790=EDGE_CURVE('E783',#300,#1400,#2789,.T.);
#2791=ORIENTED_EDGE('',*,*,#2790,.T.);
#2792=ORIENTED_EDGE('',*,*,#1401,.T.);
#2793=EDGE_LOOP('',(#2784,#2785,#2791,#2792));
#2794=FACE_BOUND('',#2793,.T.);
#2795=ADVANCED_FACE('F1601',(#2794),#2783,.F.);
#2796=CARTESIAN_POINT('',(12.,0.,0.));
#2797=DIRECTION('',(-1.,0.,0.));
#2798=DIRECTION('',(0.,0.,1.));
#2799=AXIS2_PLACEMENT_3D('',#2796,#2797,#2798);
#2800=CYLINDRICAL_SURFACE('',#2799,84.13877);
#2801=ORIENTED_EDGE('',*,*,#1410,.F.);
#2802=ORIENTED_EDGE('',*,*,#2790,.F.);
#2803=ORIENTED_EDGE('',*,*,#301,.T.);
#2804=ORIENTED_EDGE('',*,*,#2773,.T.);
#2805=EDGE_LOOP('',(#2801,#2802,#2803,#2804));
#2806=FACE_BOUND('',#2805,.T.);
#2807=ADVANCED_FACE('F1598',(#2806),#2800,.F.);
#2808=CARTESIAN_POINT('',(12.,-30.2540534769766,-62.985468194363));
#2809=DIRECTION('',(-1.,0.,0.));
#2810=DIRECTION('',(0.,0.,1.));
#2811=AXIS2_PLACEMENT_3D('',#2808,#2809,#2810);
#2812=CYLINDRICAL_SURFACE('',#2811,38.1);
#2813=ORIENTED_EDGE('',*,*,#1656,.T.);
#2814=ORIENTED_EDGE('',*,*,#1450,.F.);
#2815=DIRECTION('',(-1.,0.,0.));
#2816=VECTOR('',#2815,1.);
#2817=CARTESIAN_POINT('',(12.,1.44248948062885,-84.1264039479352));
#2818=LINE('',#2817,#2816);
#2819=EDGE_CURVE('E766',#260,#1440,#2818,.T.);
#2820=ORIENTED_EDGE('',*,*,#2819,.F.);
#2821=ORIENTED_EDGE('',*,*,#261,.T.);
#2822=EDGE_LOOP('',(#2813,#2814,#2820,#2821));
#2823=FACE_BOUND('',#2822,.T.);
#2824=ADVANCED_FACE('F1582',(#2823),#2812,.F.);
#2825=CARTESIAN_POINT('',(12.,30.254053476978,-62.9854681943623));
#2826=DIRECTION('',(-1.,0.,0.));
#2827=DIRECTION('',(0.,0.,1.));
#2828=AXIS2_PLACEMENT_3D('',#2825,#2826,#2827);
#2829=CYLINDRICAL_SURFACE('',#2828,38.1);
#2830=ORIENTED_EDGE('',*,*,#1666,.T.);
#2831=ORIENTED_EDGE('',*,*,#279,.T.);
#2832=DIRECTION('',(-1.,0.,0.));
#2833=VECTOR('',#2832,1.);
#2834=CARTESIAN_POINT('',(12.,-1.44248948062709,-84.1264039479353));
#2835=LINE('',#2834,#2833);
#2836=EDGE_CURVE('E759',#269,#1431,#2835,.T.);
#2837=ORIENTED_EDGE('',*,*,#2836,.T.);
#2838=ORIENTED_EDGE('',*,*,#1432,.T.);
#2839=EDGE_LOOP('',(#2830,#2831,#2837,#2838));
#2840=FACE_BOUND('',#2839,.T.);
#2841=ADVANCED_FACE('F1590',(#2840),#2829,.F.);
#2842=CARTESIAN_POINT('',(12.,0.,0.));
#2843=DIRECTION('',(-1.,0.,0.));
#2844=DIRECTION('',(0.,0.,1.));
#2845=AXIS2_PLACEMENT_3D('',#2842,#2843,#2844);
#2846=CYLINDRICAL_SURFACE('',#2845,84.13877);
#2847=ORIENTED_EDGE('',*,*,#1441,.F.);
#2848=ORIENTED_EDGE('',*,*,#2836,.F.);
#2849=ORIENTED_EDGE('',*,*,#270,.T.);
#2850=ORIENTED_EDGE('',*,*,#2819,.T.);
#2851=EDGE_LOOP('',(#2847,#2848,#2849,#2850));
#2852=FACE_BOUND('',#2851,.T.);
#2853=ADVANCED_FACE('F1587',(#2852),#2846,.F.);
#2854=CARTESIAN_POINT('',(12.,-12.9213328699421,-68.6696156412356));
#2855=DIRECTION('',(-1.,0.,0.));
#2856=DIRECTION('',(0.,0.,1.));
#2857=AXIS2_PLACEMENT_3D('',#2854,#2855,#2856);
#2858=CYLINDRICAL_SURFACE('',#2857,38.1);
#2859=ORIENTED_EDGE('',*,*,#1639,.T.);
#2860=ORIENTED_EDGE('',*,*,#1481,.F.);
#2861=DIRECTION('',(-1.,0.,0.));
#2862=VECTOR('',#2861,1.);
#2863=CARTESIAN_POINT('',(12.,23.1668533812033,-80.8865224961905));
#2864=LINE('',#2863,#2862);
#2865=EDGE_CURVE('E742',#229,#1471,#2864,.T.);
#2866=ORIENTED_EDGE('',*,*,#2865,.F.);
#2867=ORIENTED_EDGE('',*,*,#230,.T.);
#2868=EDGE_LOOP('',(#2859,#2860,#2866,#2867));
#2869=FACE_BOUND('',#2868,.T.);
#2870=ADVANCED_FACE('F1572',(#2869),#2858,.F.);
#2871=CARTESIAN_POINT('',(12.,45.5250103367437,-53.0089651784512));
#2872=DIRECTION('',(-1.,0.,0.));
#2873=DIRECTION('',(0.,0.,1.));
#2874=AXIS2_PLACEMENT_3D('',#2871,#2872,#2873);
#2875=CYLINDRICAL_SURFACE('',#2874,38.1);
#2876=ORIENTED_EDGE('',*,*,#1649,.T.);
#2877=ORIENTED_EDGE('',*,*,#248,.T.);
#2878=DIRECTION('',(-1.,0.,0.));
#2879=VECTOR('',#2878,1.);
#2880=CARTESIAN_POINT('',(12.,20.3801776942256,-81.6332099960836));
#2881=LINE('',#2880,#2879);
#2882=EDGE_CURVE('E735',#238,#1462,#2881,.T.);
#2883=ORIENTED_EDGE('',*,*,#2882,.T.);
#2884=ORIENTED_EDGE('',*,*,#1463,.T.);
#2885=EDGE_LOOP('',(#2876,#2877,#2883,#2884));
#2886=FACE_BOUND('',#2885,.T.);
#2887=ADVANCED_FACE('F1580',(#2886),#2875,.F.);
#2888=CARTESIAN_POINT('',(12.,0.,0.));
#2889=DIRECTION('',(-1.,0.,0.));
#2890=DIRECTION('',(0.,0.,1.));
#2891=AXIS2_PLACEMENT_3D('',#2888,#2889,#2890);
#2892=CYLINDRICAL_SURFACE('',#2891,84.13877);
#2893=ORIENTED_EDGE('',*,*,#1472,.F.);
#2894=ORIENTED_EDGE('',*,*,#2882,.F.);
#2895=ORIENTED_EDGE('',*,*,#239,.T.);
#2896=ORIENTED_EDGE('',*,*,#2865,.T.);
#2897=EDGE_LOOP('',(#2893,#2894,#2895,#2896));
#2898=FACE_BOUND('',#2897,.T.);
#2899=ADVANCED_FACE('F1577',(#2898),#2892,.F.);
#2900=CARTESIAN_POINT('',(12.,5.29195521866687,-69.6740422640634));
#2901=DIRECTION('',(-1.,0.,0.));
#2902=DIRECTION('',(0.,0.,1.));
#2903=AXIS2_PLACEMENT_3D('',#2900,#2901,#2902);
#2904=CYLINDRICAL_SURFACE('',#2903,38.1);
#2905=ORIENTED_EDGE('',*,*,#1622,.T.);
#2906=ORIENTED_EDGE('',*,*,#1512,.F.);
#2907=DIRECTION('',(-1.,0.,0.));
#2908=VECTOR('',#2907,1.);
#2909=CARTESIAN_POINT('',(12.,43.3124345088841,-72.1343582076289));
#2910=LINE('',#2909,#2908);
#2911=EDGE_CURVE('E718',#198,#1502,#2910,.T.);
#2912=ORIENTED_EDGE('',*,*,#2911,.F.);
#2913=ORIENTED_EDGE('',*,*,#199,.T.);
#2914=EDGE_LOOP('',(#2905,#2906,#2912,#2913));
#2915=FACE_BOUND('',#2914,.T.);
#2916=ADVANCED_FACE('F1565',(#2915),#2904,.F.);
#2917=CARTESIAN_POINT('',(12.,57.6935129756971,-39.4199887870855));
#2918=DIRECTION('',(-1.,0.,0.));
#2919=DIRECTION('',(0.,0.,1.));
#2920=AXIS2_PLACEMENT_3D('',#2917,#2918,#2919);
#2921=CYLINDRICAL_SURFACE('',#2920,38.1);
#2922=ORIENTED_EDGE('',*,*,#1632,.T.);
#2923=ORIENTED_EDGE('',*,*,#217,.T.);
#2924=DIRECTION('',(-1.,0.,0.));
#2925=VECTOR('',#2924,1.);
#2926=CARTESIAN_POINT('',(12.,40.8139694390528,-73.5768476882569));
#2927=LINE('',#2926,#2925);
#2928=EDGE_CURVE('E711',#207,#1493,#2927,.T.);
#2929=ORIENTED_EDGE('',*,*,#2928,.T.);
#2930=ORIENTED_EDGE('',*,*,#1494,.T.);
#2931=EDGE_LOOP('',(#2922,#2923,#2929,#2930));
#2932=FACE_BOUND('',#2931,.T.);
#2933=ADVANCED_FACE('F2206',(#2932),#2921,.F.);
#2934=CARTESIAN_POINT('',(12.,0.,0.));
#2935=DIRECTION('',(-1.,0.,0.));
#2936=DIRECTION('',(0.,0.,1.));
#2937=AXIS2_PLACEMENT_3D('',#2934,#2935,#2936);
#2938=CYLINDRICAL_SURFACE('',#2937,84.13877);
#2939=ORIENTED_EDGE('',*,*,#1503,.F.);
#2940=ORIENTED_EDGE('',*,*,#2928,.F.);
#2941=ORIENTED_EDGE('',*,*,#208,.T.);
#2942=ORIENTED_EDGE('',*,*,#2911,.T.);
#2943=EDGE_LOOP('',(#2939,#2940,#2941,#2942));
#2944=FACE_BOUND('',#2943,.T.);
#2945=ADVANCED_FACE('F1567',(#2944),#2938,.F.);
#2946=CARTESIAN_POINT('',(12.,23.1446053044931,-65.9302980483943));
#2947=DIRECTION('',(-1.,0.,0.));
#2948=DIRECTION('',(0.,0.,1.));
#2949=AXIS2_PLACEMENT_3D('',#2946,#2947,#2948);
#2950=CYLINDRICAL_SURFACE('',#2949,38.1);
#2951=ORIENTED_EDGE('',*,*,#1605,.T.);
#2952=ORIENTED_EDGE('',*,*,#1543,.F.);
#2953=DIRECTION('',(-1.,0.,0.));
#2954=VECTOR('',#2953,1.);
#2955=CARTESIAN_POINT('',(12.,60.5063448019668,-58.4663566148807));
#2956=LINE('',#2955,#2954);
#2957=EDGE_CURVE('E694',#167,#1533,#2956,.T.);
#2958=ORIENTED_EDGE('',*,*,#2957,.F.);
#2959=ORIENTED_EDGE('',*,*,#168,.T.);
#2960=EDGE_LOOP('',(#2951,#2952,#2958,#2959));
#2961=FACE_BOUND('',#2960,.T.);
#2962=ADVANCED_FACE('F2223',(#2961),#2950,.F.);
#2963=CARTESIAN_POINT('',(12.,65.9302980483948,-23.1446053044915));
#2964=DIRECTION('',(-1.,0.,0.));
#2965=DIRECTION('',(0.,0.,1.));
#2966=AXIS2_PLACEMENT_3D('',#2963,#2964,#2965);
#2967=CYLINDRICAL_SURFACE('',#2966,38.1);
#2968=ORIENTED_EDGE('',*,*,#1615,.T.);
#2969=ORIENTED_EDGE('',*,*,#186,.T.);
#2970=DIRECTION('',(-1.,0.,0.));
#2971=VECTOR('',#2970,1.);
#2972=CARTESIAN_POINT('',(12.,58.4663566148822,-60.5063448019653));
#2973=LINE('',#2972,#2971);
#2974=EDGE_CURVE('E687',#176,#1524,#2973,.T.);
#2975=ORIENTED_EDGE('',*,*,#2974,.T.);
#2976=ORIENTED_EDGE('',*,*,#1525,.T.);
#2977=EDGE_LOOP('',(#2968,#2969,#2975,#2976));
#2978=FACE_BOUND('',#2977,.T.);
#2979=ADVANCED_FACE('F2232',(#2978),#2967,.F.);
#2980=CARTESIAN_POINT('',(12.,0.,0.));
#2981=DIRECTION('',(-1.,0.,0.));
#2982=DIRECTION('',(0.,0.,1.));
#2983=AXIS2_PLACEMENT_3D('',#2980,#2981,#2982);
#2984=CYLINDRICAL_SURFACE('',#2983,84.13877);
#2985=ORIENTED_EDGE('',*,*,#1534,.F.);
#2986=ORIENTED_EDGE('',*,*,#2974,.F.);
#2987=ORIENTED_EDGE('',*,*,#177,.T.);
#2988=ORIENTED_EDGE('',*,*,#2957,.T.);
#2989=EDGE_LOOP('',(#2985,#2986,#2987,#2988));
#2990=FACE_BOUND('',#2989,.T.);
#2991=ADVANCED_FACE('F2242',(#2990),#2984,.F.);
#2992=CARTESIAN_POINT('',(12.,39.4199887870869,-57.6935129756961));
#2993=DIRECTION('',(-1.,0.,0.));
#2994=DIRECTION('',(0.,0.,1.));
#2995=AXIS2_PLACEMENT_3D('',#2992,#2993,#2994);
#2996=CYLINDRICAL_SURFACE('',#2995,38.1);
#2997=ORIENTED_EDGE('',*,*,#81,.T.);
#2998=ORIENTED_EDGE('',*,*,#1572,.F.);
#2999=DIRECTION('',(-1.,0.,0.));
#3000=VECTOR('',#2999,1.);
#3001=CARTESIAN_POINT('',(12.,73.5768476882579,-40.813969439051));
#3002=LINE('',#3001,#3000);
#3003=EDGE_CURVE('E671',#136,#1564,#3002,.T.);
#3004=ORIENTED_EDGE('',*,*,#3003,.F.);
#3005=ORIENTED_EDGE('',*,*,#137,.T.);
#3006=EDGE_LOOP('',(#2997,#2998,#3004,#3005));
#3007=FACE_BOUND('',#3006,.T.);
#3008=ADVANCED_FACE('F2251',(#3007),#2996,.F.);
#3009=CARTESIAN_POINT('',(12.,69.6740422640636,-5.29195521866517));
#3010=DIRECTION('',(-1.,0.,0.));
#3011=DIRECTION('',(0.,0.,1.));
#3012=AXIS2_PLACEMENT_3D('',#3009,#3010,#3011);
#3013=CYLINDRICAL_SURFACE('',#3012,38.1);
#3014=ORIENTED_EDGE('',*,*,#1598,.T.);
#3015=ORIENTED_EDGE('',*,*,#155,.T.);
#3016=DIRECTION('',(-1.,0.,0.));
#3017=VECTOR('',#3016,1.);
#3018=CARTESIAN_POINT('',(12.,72.13435820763,-43.3124345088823));
#3019=LINE('',#3018,#3017);
#3020=EDGE_CURVE('E666',#145,#1555,#3019,.T.);
#3021=ORIENTED_EDGE('',*,*,#3020,.T.);
#3022=ORIENTED_EDGE('',*,*,#1556,.T.);
#3023=EDGE_LOOP('',(#3014,#3015,#3021,#3022));
#3024=FACE_BOUND('',#3023,.T.);
#3025=ADVANCED_FACE('F1266',(#3024),#3013,.F.);
#3026=CARTESIAN_POINT('',(12.,0.,0.));
#3027=DIRECTION('',(-1.,0.,0.));
#3028=DIRECTION('',(0.,0.,1.));
#3029=AXIS2_PLACEMENT_3D('',#3026,#3027,#3028);
#3030=CYLINDRICAL_SURFACE('',#3029,84.13877);
#3031=ORIENTED_EDGE('',*,*,#1565,.F.);
#3032=ORIENTED_EDGE('',*,*,#3020,.F.);
#3033=ORIENTED_EDGE('',*,*,#146,.T.);
#3034=ORIENTED_EDGE('',*,*,#3003,.T.);
#3035=EDGE_LOOP('',(#3031,#3032,#3033,#3034));
#3036=FACE_BOUND('',#3035,.T.);
#3037=ADVANCED_FACE('F2270',(#3036),#3030,.F.);
#3038=CARTESIAN_POINT('',(12.,53.0089651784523,-45.5250103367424));
#3039=DIRECTION('',(-1.,0.,0.));
#3040=DIRECTION('',(0.,0.,1.));
#3041=AXIS2_PLACEMENT_3D('',#3038,#3039,#3040);
#3042=CYLINDRICAL_SURFACE('',#3041,38.1);
#3043=ORIENTED_EDGE('',*,*,#32,.T.);
#3044=ORIENTED_EDGE('',*,*,#864,.F.);
#3045=DIRECTION('',(-1.,0.,0.));
#3046=VECTOR('',#3045,1.);
#3047=CARTESIAN_POINT('',(12.,81.6332099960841,-20.3801776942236));
#3048=LINE('',#3047,#3046);
#3049=EDGE_CURVE('E629',#110,#863,#3048,.T.);
#3050=ORIENTED_EDGE('',*,*,#3049,.F.);
#3051=ORIENTED_EDGE('',*,*,#111,.T.);
#3052=EDGE_LOOP('',(#3043,#3044,#3050,#3051));
#3053=FACE_BOUND('',#3052,.T.);
#3054=ADVANCED_FACE('F638',(#3053),#3042,.F.);
#3055=CARTESIAN_POINT('',(12.,68.6696156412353,12.9213328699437));
#3056=DIRECTION('',(-1.,0.,0.));
#3057=DIRECTION('',(0.,0.,1.));
#3058=AXIS2_PLACEMENT_3D('',#3055,#3056,#3057);
#3059=CYLINDRICAL_SURFACE('',#3058,38.1);
#3060=ORIENTED_EDGE('',*,*,#69,.T.);
#3061=ORIENTED_EDGE('',*,*,#127,.T.);
#3062=DIRECTION('',(-1.,0.,0.));
#3063=VECTOR('',#3062,1.);
#3064=CARTESIAN_POINT('',(12.,80.886522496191,-23.1668533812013));
#3065=LINE('',#3064,#3063);
#3066=EDGE_CURVE('E630',#119,#1581,#3065,.T.);
#3067=ORIENTED_EDGE('',*,*,#3066,.T.);
#3068=ORIENTED_EDGE('',*,*,#1582,.T.);
#3069=EDGE_LOOP('',(#3060,#3061,#3067,#3068));
#3070=FACE_BOUND('',#3069,.T.);
#3071=ADVANCED_FACE('F1402',(#3070),#3059,.F.);
#3072=CARTESIAN_POINT('',(12.,0.,0.));
#3073=DIRECTION('',(-1.,0.,0.));
#3074=DIRECTION('',(0.,0.,1.));
#3075=AXIS2_PLACEMENT_3D('',#3072,#3073,#3074);
#3076=CYLINDRICAL_SURFACE('',#3075,84.13877);
#3077=ORIENTED_EDGE('',*,*,#1589,.F.);
#3078=ORIENTED_EDGE('',*,*,#3066,.F.);
#3079=ORIENTED_EDGE('',*,*,#120,.T.);
#3080=ORIENTED_EDGE('',*,*,#3049,.T.);
#3081=EDGE_LOOP('',(#3077,#3078,#3079,#3080));
#3082=FACE_BOUND('',#3081,.T.);
#3083=ADVANCED_FACE('F628',(#3082),#3076,.F.);
#3084=CLOSED_SHELL('',(#60,#87,#840,#1593,#1610,#1627,#1644,#1661,#1678,#1695,#1712,#1729,#1746,
#1763,#1780,#1797,#1814,#1831,#1848,#1865,#1882,#1899,#1916,#1933,#1950,#1967,#1979,#1996,#2013,
#2025,#2042,#2059,#2071,#2088,#2105,#2117,#2134,#2151,#2163,#2180,#2197,#2209,#2226,#2243,#2255,
#2272,#2289,#2301,#2318,#2335,#2347,#2364,#2381,#2393,#2410,#2427,#2439,#2456,#2473,#2485,#2502,
#2519,#2531,#2548,#2565,#2577,#2594,#2611,#2623,#2640,#2657,#2669,#2686,#2703,#2715,#2732,#2749,
#2761,#2778,#2795,#2807,#2824,#2841,#2853,#2870,#2887,#2899,#2916,#2933,#2945,#2962,#2979,#2991,
#3008,#3025,#3037,#3054,#3071,#3083));
#3085=MANIFOLD_SOLID_BREP('B2',#3084);
#3086=ADVANCED_BREP_SHAPE_REPRESENTATION('',(#18,#3085),#14);
#3087=SHAPE_DEFINITION_REPRESENTATION(#9,#3086);
ENDSEC;
END-ISO-10303-21;
